# W5 partial readout tile: NOT an ARRAY-PORT replacement; decoder/phase/mux external.
VERSION 5.8 ;
BUSBITCHARS "[]" ;
DIVIDERCHAR "/" ;
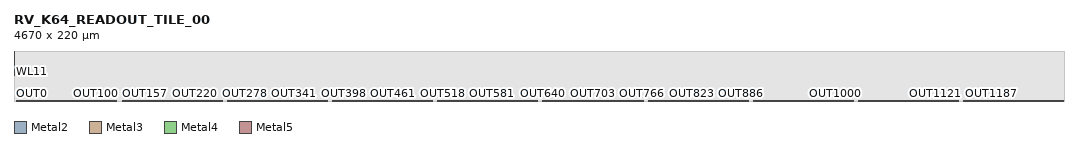
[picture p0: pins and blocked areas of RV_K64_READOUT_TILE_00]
MACRO RV_K64_READOUT_TILE_00
  CLASS BLOCK ;
  ORIGIN 0 0 ;
  SIZE 4670 BY 220 ;
  SYMMETRY X Y ;
  PIN OUT0
    DIRECTION OUTPUT ;
    USE SIGNAL ;
    PORT
      LAYER Metal2 ;
      RECT 12.720 0.000 13.080 0.500 ;
    END
  END OUT0
  PIN OUT1
    DIRECTION OUTPUT ;
    USE SIGNAL ;
    PORT
      LAYER Metal2 ;
      RECT 16.220 0.000 16.580 0.500 ;
    END
  END OUT1
  PIN OUT2
    DIRECTION OUTPUT ;
    USE SIGNAL ;
    PORT
      LAYER Metal2 ;
      RECT 19.720 0.000 20.080 0.500 ;
    END
  END OUT2
  PIN OUT3
    DIRECTION OUTPUT ;
    USE SIGNAL ;
    PORT
      LAYER Metal2 ;
      RECT 23.220 0.000 23.580 0.500 ;
    END
  END OUT3
  PIN OUT4
    DIRECTION OUTPUT ;
    USE SIGNAL ;
    PORT
      LAYER Metal2 ;
      RECT 26.720 0.000 27.080 0.500 ;
    END
  END OUT4
  PIN OUT5
    DIRECTION OUTPUT ;
    USE SIGNAL ;
    PORT
      LAYER Metal2 ;
      RECT 30.220 0.000 30.580 0.500 ;
    END
  END OUT5
  PIN OUT6
    DIRECTION OUTPUT ;
    USE SIGNAL ;
    PORT
      LAYER Metal2 ;
      RECT 33.720 0.000 34.080 0.500 ;
    END
  END OUT6
  PIN OUT7
    DIRECTION OUTPUT ;
    USE SIGNAL ;
    PORT
      LAYER Metal2 ;
      RECT 37.220 0.000 37.580 0.500 ;
    END
  END OUT7
  PIN OUT8
    DIRECTION OUTPUT ;
    USE SIGNAL ;
    PORT
      LAYER Metal2 ;
      RECT 40.720 0.000 41.080 0.500 ;
    END
  END OUT8
  PIN OUT9
    DIRECTION OUTPUT ;
    USE SIGNAL ;
    PORT
      LAYER Metal2 ;
      RECT 44.220 0.000 44.580 0.500 ;
    END
  END OUT9
  PIN OUT10
    DIRECTION OUTPUT ;
    USE SIGNAL ;
    PORT
      LAYER Metal2 ;
      RECT 47.720 0.000 48.080 0.500 ;
    END
  END OUT10
  PIN OUT11
    DIRECTION OUTPUT ;
    USE SIGNAL ;
    PORT
      LAYER Metal2 ;
      RECT 51.220 0.000 51.580 0.500 ;
    END
  END OUT11
  PIN OUT12
    DIRECTION OUTPUT ;
    USE SIGNAL ;
    PORT
      LAYER Metal2 ;
      RECT 54.720 0.000 55.080 0.500 ;
    END
  END OUT12
  PIN OUT13
    DIRECTION OUTPUT ;
    USE SIGNAL ;
    PORT
      LAYER Metal2 ;
      RECT 58.220 0.000 58.580 0.500 ;
    END
  END OUT13
  PIN OUT14
    DIRECTION OUTPUT ;
    USE SIGNAL ;
    PORT
      LAYER Metal2 ;
      RECT 61.720 0.000 62.080 0.500 ;
    END
  END OUT14
  PIN OUT15
    DIRECTION OUTPUT ;
    USE SIGNAL ;
    PORT
      LAYER Metal2 ;
      RECT 65.220 0.000 65.580 0.500 ;
    END
  END OUT15
  PIN OUT16
    DIRECTION OUTPUT ;
    USE SIGNAL ;
    PORT
      LAYER Metal2 ;
      RECT 68.720 0.000 69.080 0.500 ;
    END
  END OUT16
  PIN OUT17
    DIRECTION OUTPUT ;
    USE SIGNAL ;
    PORT
      LAYER Metal2 ;
      RECT 72.220 0.000 72.580 0.500 ;
    END
  END OUT17
  PIN OUT18
    DIRECTION OUTPUT ;
    USE SIGNAL ;
    PORT
      LAYER Metal2 ;
      RECT 75.720 0.000 76.080 0.500 ;
    END
  END OUT18
  PIN OUT19
    DIRECTION OUTPUT ;
    USE SIGNAL ;
    PORT
      LAYER Metal2 ;
      RECT 79.220 0.000 79.580 0.500 ;
    END
  END OUT19
  PIN OUT20
    DIRECTION OUTPUT ;
    USE SIGNAL ;
    PORT
      LAYER Metal2 ;
      RECT 82.720 0.000 83.080 0.500 ;
    END
  END OUT20
  PIN OUT21
    DIRECTION OUTPUT ;
    USE SIGNAL ;
    PORT
      LAYER Metal2 ;
      RECT 86.220 0.000 86.580 0.500 ;
    END
  END OUT21
  PIN OUT22
    DIRECTION OUTPUT ;
    USE SIGNAL ;
    PORT
      LAYER Metal2 ;
      RECT 89.720 0.000 90.080 0.500 ;
    END
  END OUT22
  PIN OUT23
    DIRECTION OUTPUT ;
    USE SIGNAL ;
    PORT
      LAYER Metal2 ;
      RECT 93.220 0.000 93.580 0.500 ;
    END
  END OUT23
  PIN OUT24
    DIRECTION OUTPUT ;
    USE SIGNAL ;
    PORT
      LAYER Metal2 ;
      RECT 96.720 0.000 97.080 0.500 ;
    END
  END OUT24
  PIN OUT25
    DIRECTION OUTPUT ;
    USE SIGNAL ;
    PORT
      LAYER Metal2 ;
      RECT 100.220 0.000 100.580 0.500 ;
    END
  END OUT25
  PIN OUT26
    DIRECTION OUTPUT ;
    USE SIGNAL ;
    PORT
      LAYER Metal2 ;
      RECT 103.720 0.000 104.080 0.500 ;
    END
  END OUT26
  PIN OUT27
    DIRECTION OUTPUT ;
    USE SIGNAL ;
    PORT
      LAYER Metal2 ;
      RECT 107.220 0.000 107.580 0.500 ;
    END
  END OUT27
  PIN OUT28
    DIRECTION OUTPUT ;
    USE SIGNAL ;
    PORT
      LAYER Metal2 ;
      RECT 110.720 0.000 111.080 0.500 ;
    END
  END OUT28
  PIN OUT29
    DIRECTION OUTPUT ;
    USE SIGNAL ;
    PORT
      LAYER Metal2 ;
      RECT 114.220 0.000 114.580 0.500 ;
    END
  END OUT29
  PIN OUT30
    DIRECTION OUTPUT ;
    USE SIGNAL ;
    PORT
      LAYER Metal2 ;
      RECT 117.720 0.000 118.080 0.500 ;
    END
  END OUT30
  PIN OUT31
    DIRECTION OUTPUT ;
    USE SIGNAL ;
    PORT
      LAYER Metal2 ;
      RECT 121.220 0.000 121.580 0.500 ;
    END
  END OUT31
  PIN OUT32
    DIRECTION OUTPUT ;
    USE SIGNAL ;
    PORT
      LAYER Metal2 ;
      RECT 124.720 0.000 125.080 0.500 ;
    END
  END OUT32
  PIN OUT33
    DIRECTION OUTPUT ;
    USE SIGNAL ;
    PORT
      LAYER Metal2 ;
      RECT 128.220 0.000 128.580 0.500 ;
    END
  END OUT33
  PIN OUT34
    DIRECTION OUTPUT ;
    USE SIGNAL ;
    PORT
      LAYER Metal2 ;
      RECT 131.720 0.000 132.080 0.500 ;
    END
  END OUT34
  PIN OUT35
    DIRECTION OUTPUT ;
    USE SIGNAL ;
    PORT
      LAYER Metal2 ;
      RECT 135.220 0.000 135.580 0.500 ;
    END
  END OUT35
  PIN OUT36
    DIRECTION OUTPUT ;
    USE SIGNAL ;
    PORT
      LAYER Metal2 ;
      RECT 138.720 0.000 139.080 0.500 ;
    END
  END OUT36
  PIN OUT37
    DIRECTION OUTPUT ;
    USE SIGNAL ;
    PORT
      LAYER Metal2 ;
      RECT 142.220 0.000 142.580 0.500 ;
    END
  END OUT37
  PIN OUT38
    DIRECTION OUTPUT ;
    USE SIGNAL ;
    PORT
      LAYER Metal2 ;
      RECT 145.720 0.000 146.080 0.500 ;
    END
  END OUT38
  PIN OUT39
    DIRECTION OUTPUT ;
    USE SIGNAL ;
    PORT
      LAYER Metal2 ;
      RECT 149.220 0.000 149.580 0.500 ;
    END
  END OUT39
  PIN OUT40
    DIRECTION OUTPUT ;
    USE SIGNAL ;
    PORT
      LAYER Metal2 ;
      RECT 152.720 0.000 153.080 0.500 ;
    END
  END OUT40
  PIN OUT41
    DIRECTION OUTPUT ;
    USE SIGNAL ;
    PORT
      LAYER Metal2 ;
      RECT 156.220 0.000 156.580 0.500 ;
    END
  END OUT41
  PIN OUT42
    DIRECTION OUTPUT ;
    USE SIGNAL ;
    PORT
      LAYER Metal2 ;
      RECT 159.720 0.000 160.080 0.500 ;
    END
  END OUT42
  PIN OUT43
    DIRECTION OUTPUT ;
    USE SIGNAL ;
    PORT
      LAYER Metal2 ;
      RECT 163.220 0.000 163.580 0.500 ;
    END
  END OUT43
  PIN OUT44
    DIRECTION OUTPUT ;
    USE SIGNAL ;
    PORT
      LAYER Metal2 ;
      RECT 166.720 0.000 167.080 0.500 ;
    END
  END OUT44
  PIN OUT45
    DIRECTION OUTPUT ;
    USE SIGNAL ;
    PORT
      LAYER Metal2 ;
      RECT 170.220 0.000 170.580 0.500 ;
    END
  END OUT45
  PIN OUT46
    DIRECTION OUTPUT ;
    USE SIGNAL ;
    PORT
      LAYER Metal2 ;
      RECT 173.720 0.000 174.080 0.500 ;
    END
  END OUT46
  PIN OUT47
    DIRECTION OUTPUT ;
    USE SIGNAL ;
    PORT
      LAYER Metal2 ;
      RECT 177.220 0.000 177.580 0.500 ;
    END
  END OUT47
  PIN OUT48
    DIRECTION OUTPUT ;
    USE SIGNAL ;
    PORT
      LAYER Metal2 ;
      RECT 180.720 0.000 181.080 0.500 ;
    END
  END OUT48
  PIN OUT49
    DIRECTION OUTPUT ;
    USE SIGNAL ;
    PORT
      LAYER Metal2 ;
      RECT 184.220 0.000 184.580 0.500 ;
    END
  END OUT49
  PIN OUT50
    DIRECTION OUTPUT ;
    USE SIGNAL ;
    PORT
      LAYER Metal2 ;
      RECT 187.720 0.000 188.080 0.500 ;
    END
  END OUT50
  PIN OUT51
    DIRECTION OUTPUT ;
    USE SIGNAL ;
    PORT
      LAYER Metal2 ;
      RECT 191.220 0.000 191.580 0.500 ;
    END
  END OUT51
  PIN OUT52
    DIRECTION OUTPUT ;
    USE SIGNAL ;
    PORT
      LAYER Metal2 ;
      RECT 194.720 0.000 195.080 0.500 ;
    END
  END OUT52
  PIN OUT53
    DIRECTION OUTPUT ;
    USE SIGNAL ;
    PORT
      LAYER Metal2 ;
      RECT 198.220 0.000 198.580 0.500 ;
    END
  END OUT53
  PIN OUT54
    DIRECTION OUTPUT ;
    USE SIGNAL ;
    PORT
      LAYER Metal2 ;
      RECT 201.720 0.000 202.080 0.500 ;
    END
  END OUT54
  PIN OUT55
    DIRECTION OUTPUT ;
    USE SIGNAL ;
    PORT
      LAYER Metal2 ;
      RECT 205.220 0.000 205.580 0.500 ;
    END
  END OUT55
  PIN OUT56
    DIRECTION OUTPUT ;
    USE SIGNAL ;
    PORT
      LAYER Metal2 ;
      RECT 208.720 0.000 209.080 0.500 ;
    END
  END OUT56
  PIN OUT57
    DIRECTION OUTPUT ;
    USE SIGNAL ;
    PORT
      LAYER Metal2 ;
      RECT 212.220 0.000 212.580 0.500 ;
    END
  END OUT57
  PIN OUT58
    DIRECTION OUTPUT ;
    USE SIGNAL ;
    PORT
      LAYER Metal2 ;
      RECT 215.720 0.000 216.080 0.500 ;
    END
  END OUT58
  PIN OUT59
    DIRECTION OUTPUT ;
    USE SIGNAL ;
    PORT
      LAYER Metal2 ;
      RECT 219.220 0.000 219.580 0.500 ;
    END
  END OUT59
  PIN OUT60
    DIRECTION OUTPUT ;
    USE SIGNAL ;
    PORT
      LAYER Metal2 ;
      RECT 222.720 0.000 223.080 0.500 ;
    END
  END OUT60
  PIN OUT61
    DIRECTION OUTPUT ;
    USE SIGNAL ;
    PORT
      LAYER Metal2 ;
      RECT 226.220 0.000 226.580 0.500 ;
    END
  END OUT61
  PIN OUT62
    DIRECTION OUTPUT ;
    USE SIGNAL ;
    PORT
      LAYER Metal2 ;
      RECT 229.720 0.000 230.080 0.500 ;
    END
  END OUT62
  PIN OUT63
    DIRECTION OUTPUT ;
    USE SIGNAL ;
    PORT
      LAYER Metal2 ;
      RECT 233.220 0.000 233.580 0.500 ;
    END
  END OUT63
  PIN OUT64
    DIRECTION OUTPUT ;
    USE SIGNAL ;
    PORT
      LAYER Metal2 ;
      RECT 236.720 0.000 237.080 0.500 ;
    END
  END OUT64
  PIN OUT65
    DIRECTION OUTPUT ;
    USE SIGNAL ;
    PORT
      LAYER Metal2 ;
      RECT 240.220 0.000 240.580 0.500 ;
    END
  END OUT65
  PIN OUT66
    DIRECTION OUTPUT ;
    USE SIGNAL ;
    PORT
      LAYER Metal2 ;
      RECT 243.720 0.000 244.080 0.500 ;
    END
  END OUT66
  PIN OUT67
    DIRECTION OUTPUT ;
    USE SIGNAL ;
    PORT
      LAYER Metal2 ;
      RECT 247.220 0.000 247.580 0.500 ;
    END
  END OUT67
  PIN OUT68
    DIRECTION OUTPUT ;
    USE SIGNAL ;
    PORT
      LAYER Metal2 ;
      RECT 250.720 0.000 251.080 0.500 ;
    END
  END OUT68
  PIN OUT69
    DIRECTION OUTPUT ;
    USE SIGNAL ;
    PORT
      LAYER Metal2 ;
      RECT 254.220 0.000 254.580 0.500 ;
    END
  END OUT69
  PIN OUT70
    DIRECTION OUTPUT ;
    USE SIGNAL ;
    PORT
      LAYER Metal2 ;
      RECT 257.720 0.000 258.080 0.500 ;
    END
  END OUT70
  PIN OUT71
    DIRECTION OUTPUT ;
    USE SIGNAL ;
    PORT
      LAYER Metal2 ;
      RECT 261.220 0.000 261.580 0.500 ;
    END
  END OUT71
  PIN OUT72
    DIRECTION OUTPUT ;
    USE SIGNAL ;
    PORT
      LAYER Metal2 ;
      RECT 264.720 0.000 265.080 0.500 ;
    END
  END OUT72
  PIN OUT73
    DIRECTION OUTPUT ;
    USE SIGNAL ;
    PORT
      LAYER Metal2 ;
      RECT 268.220 0.000 268.580 0.500 ;
    END
  END OUT73
  PIN OUT74
    DIRECTION OUTPUT ;
    USE SIGNAL ;
    PORT
      LAYER Metal2 ;
      RECT 271.720 0.000 272.080 0.500 ;
    END
  END OUT74
  PIN OUT75
    DIRECTION OUTPUT ;
    USE SIGNAL ;
    PORT
      LAYER Metal2 ;
      RECT 275.220 0.000 275.580 0.500 ;
    END
  END OUT75
  PIN OUT76
    DIRECTION OUTPUT ;
    USE SIGNAL ;
    PORT
      LAYER Metal2 ;
      RECT 278.720 0.000 279.080 0.500 ;
    END
  END OUT76
  PIN OUT77
    DIRECTION OUTPUT ;
    USE SIGNAL ;
    PORT
      LAYER Metal2 ;
      RECT 282.220 0.000 282.580 0.500 ;
    END
  END OUT77
  PIN OUT78
    DIRECTION OUTPUT ;
    USE SIGNAL ;
    PORT
      LAYER Metal2 ;
      RECT 285.720 0.000 286.080 0.500 ;
    END
  END OUT78
  PIN OUT79
    DIRECTION OUTPUT ;
    USE SIGNAL ;
    PORT
      LAYER Metal2 ;
      RECT 289.220 0.000 289.580 0.500 ;
    END
  END OUT79
  PIN OUT80
    DIRECTION OUTPUT ;
    USE SIGNAL ;
    PORT
      LAYER Metal2 ;
      RECT 292.720 0.000 293.080 0.500 ;
    END
  END OUT80
  PIN OUT81
    DIRECTION OUTPUT ;
    USE SIGNAL ;
    PORT
      LAYER Metal2 ;
      RECT 296.220 0.000 296.580 0.500 ;
    END
  END OUT81
  PIN OUT82
    DIRECTION OUTPUT ;
    USE SIGNAL ;
    PORT
      LAYER Metal2 ;
      RECT 299.720 0.000 300.080 0.500 ;
    END
  END OUT82
  PIN OUT83
    DIRECTION OUTPUT ;
    USE SIGNAL ;
    PORT
      LAYER Metal2 ;
      RECT 303.220 0.000 303.580 0.500 ;
    END
  END OUT83
  PIN OUT84
    DIRECTION OUTPUT ;
    USE SIGNAL ;
    PORT
      LAYER Metal2 ;
      RECT 306.720 0.000 307.080 0.500 ;
    END
  END OUT84
  PIN OUT85
    DIRECTION OUTPUT ;
    USE SIGNAL ;
    PORT
      LAYER Metal2 ;
      RECT 310.220 0.000 310.580 0.500 ;
    END
  END OUT85
  PIN OUT86
    DIRECTION OUTPUT ;
    USE SIGNAL ;
    PORT
      LAYER Metal2 ;
      RECT 313.720 0.000 314.080 0.500 ;
    END
  END OUT86
  PIN OUT87
    DIRECTION OUTPUT ;
    USE SIGNAL ;
    PORT
      LAYER Metal2 ;
      RECT 317.220 0.000 317.580 0.500 ;
    END
  END OUT87
  PIN OUT88
    DIRECTION OUTPUT ;
    USE SIGNAL ;
    PORT
      LAYER Metal2 ;
      RECT 320.720 0.000 321.080 0.500 ;
    END
  END OUT88
  PIN OUT89
    DIRECTION OUTPUT ;
    USE SIGNAL ;
    PORT
      LAYER Metal2 ;
      RECT 324.220 0.000 324.580 0.500 ;
    END
  END OUT89
  PIN OUT90
    DIRECTION OUTPUT ;
    USE SIGNAL ;
    PORT
      LAYER Metal2 ;
      RECT 327.720 0.000 328.080 0.500 ;
    END
  END OUT90
  PIN OUT91
    DIRECTION OUTPUT ;
    USE SIGNAL ;
    PORT
      LAYER Metal2 ;
      RECT 331.220 0.000 331.580 0.500 ;
    END
  END OUT91
  PIN OUT92
    DIRECTION OUTPUT ;
    USE SIGNAL ;
    PORT
      LAYER Metal2 ;
      RECT 334.720 0.000 335.080 0.500 ;
    END
  END OUT92
  PIN OUT93
    DIRECTION OUTPUT ;
    USE SIGNAL ;
    PORT
      LAYER Metal2 ;
      RECT 338.220 0.000 338.580 0.500 ;
    END
  END OUT93
  PIN OUT94
    DIRECTION OUTPUT ;
    USE SIGNAL ;
    PORT
      LAYER Metal2 ;
      RECT 341.720 0.000 342.080 0.500 ;
    END
  END OUT94
  PIN OUT95
    DIRECTION OUTPUT ;
    USE SIGNAL ;
    PORT
      LAYER Metal2 ;
      RECT 345.220 0.000 345.580 0.500 ;
    END
  END OUT95
  PIN OUT96
    DIRECTION OUTPUT ;
    USE SIGNAL ;
    PORT
      LAYER Metal2 ;
      RECT 348.720 0.000 349.080 0.500 ;
    END
  END OUT96
  PIN OUT97
    DIRECTION OUTPUT ;
    USE SIGNAL ;
    PORT
      LAYER Metal2 ;
      RECT 352.220 0.000 352.580 0.500 ;
    END
  END OUT97
  PIN OUT98
    DIRECTION OUTPUT ;
    USE SIGNAL ;
    PORT
      LAYER Metal2 ;
      RECT 355.720 0.000 356.080 0.500 ;
    END
  END OUT98
  PIN OUT99
    DIRECTION OUTPUT ;
    USE SIGNAL ;
    PORT
      LAYER Metal2 ;
      RECT 359.220 0.000 359.580 0.500 ;
    END
  END OUT99
  PIN OUT100
    DIRECTION OUTPUT ;
    USE SIGNAL ;
    PORT
      LAYER Metal2 ;
      RECT 362.720 0.000 363.080 0.500 ;
    END
  END OUT100
  PIN OUT101
    DIRECTION OUTPUT ;
    USE SIGNAL ;
    PORT
      LAYER Metal2 ;
      RECT 366.220 0.000 366.580 0.500 ;
    END
  END OUT101
  PIN OUT102
    DIRECTION OUTPUT ;
    USE SIGNAL ;
    PORT
      LAYER Metal2 ;
      RECT 369.720 0.000 370.080 0.500 ;
    END
  END OUT102
  PIN OUT103
    DIRECTION OUTPUT ;
    USE SIGNAL ;
    PORT
      LAYER Metal2 ;
      RECT 373.220 0.000 373.580 0.500 ;
    END
  END OUT103
  PIN OUT104
    DIRECTION OUTPUT ;
    USE SIGNAL ;
    PORT
      LAYER Metal2 ;
      RECT 376.720 0.000 377.080 0.500 ;
    END
  END OUT104
  PIN OUT105
    DIRECTION OUTPUT ;
    USE SIGNAL ;
    PORT
      LAYER Metal2 ;
      RECT 380.220 0.000 380.580 0.500 ;
    END
  END OUT105
  PIN OUT106
    DIRECTION OUTPUT ;
    USE SIGNAL ;
    PORT
      LAYER Metal2 ;
      RECT 383.720 0.000 384.080 0.500 ;
    END
  END OUT106
  PIN OUT107
    DIRECTION OUTPUT ;
    USE SIGNAL ;
    PORT
      LAYER Metal2 ;
      RECT 387.220 0.000 387.580 0.500 ;
    END
  END OUT107
  PIN OUT108
    DIRECTION OUTPUT ;
    USE SIGNAL ;
    PORT
      LAYER Metal2 ;
      RECT 390.720 0.000 391.080 0.500 ;
    END
  END OUT108
  PIN OUT109
    DIRECTION OUTPUT ;
    USE SIGNAL ;
    PORT
      LAYER Metal2 ;
      RECT 394.220 0.000 394.580 0.500 ;
    END
  END OUT109
  PIN OUT110
    DIRECTION OUTPUT ;
    USE SIGNAL ;
    PORT
      LAYER Metal2 ;
      RECT 397.720 0.000 398.080 0.500 ;
    END
  END OUT110
  PIN OUT111
    DIRECTION OUTPUT ;
    USE SIGNAL ;
    PORT
      LAYER Metal2 ;
      RECT 401.220 0.000 401.580 0.500 ;
    END
  END OUT111
  PIN OUT112
    DIRECTION OUTPUT ;
    USE SIGNAL ;
    PORT
      LAYER Metal2 ;
      RECT 404.720 0.000 405.080 0.500 ;
    END
  END OUT112
  PIN OUT113
    DIRECTION OUTPUT ;
    USE SIGNAL ;
    PORT
      LAYER Metal2 ;
      RECT 408.220 0.000 408.580 0.500 ;
    END
  END OUT113
  PIN OUT114
    DIRECTION OUTPUT ;
    USE SIGNAL ;
    PORT
      LAYER Metal2 ;
      RECT 411.720 0.000 412.080 0.500 ;
    END
  END OUT114
  PIN OUT115
    DIRECTION OUTPUT ;
    USE SIGNAL ;
    PORT
      LAYER Metal2 ;
      RECT 415.220 0.000 415.580 0.500 ;
    END
  END OUT115
  PIN OUT116
    DIRECTION OUTPUT ;
    USE SIGNAL ;
    PORT
      LAYER Metal2 ;
      RECT 418.720 0.000 419.080 0.500 ;
    END
  END OUT116
  PIN OUT117
    DIRECTION OUTPUT ;
    USE SIGNAL ;
    PORT
      LAYER Metal2 ;
      RECT 422.220 0.000 422.580 0.500 ;
    END
  END OUT117
  PIN OUT118
    DIRECTION OUTPUT ;
    USE SIGNAL ;
    PORT
      LAYER Metal2 ;
      RECT 425.720 0.000 426.080 0.500 ;
    END
  END OUT118
  PIN OUT119
    DIRECTION OUTPUT ;
    USE SIGNAL ;
    PORT
      LAYER Metal2 ;
      RECT 429.220 0.000 429.580 0.500 ;
    END
  END OUT119
  PIN OUT120
    DIRECTION OUTPUT ;
    USE SIGNAL ;
    PORT
      LAYER Metal2 ;
      RECT 432.720 0.000 433.080 0.500 ;
    END
  END OUT120
  PIN OUT121
    DIRECTION OUTPUT ;
    USE SIGNAL ;
    PORT
      LAYER Metal2 ;
      RECT 436.220 0.000 436.580 0.500 ;
    END
  END OUT121
  PIN OUT122
    DIRECTION OUTPUT ;
    USE SIGNAL ;
    PORT
      LAYER Metal2 ;
      RECT 439.720 0.000 440.080 0.500 ;
    END
  END OUT122
  PIN OUT123
    DIRECTION OUTPUT ;
    USE SIGNAL ;
    PORT
      LAYER Metal2 ;
      RECT 443.220 0.000 443.580 0.500 ;
    END
  END OUT123
  PIN OUT124
    DIRECTION OUTPUT ;
    USE SIGNAL ;
    PORT
      LAYER Metal2 ;
      RECT 446.720 0.000 447.080 0.500 ;
    END
  END OUT124
  PIN OUT125
    DIRECTION OUTPUT ;
    USE SIGNAL ;
    PORT
      LAYER Metal2 ;
      RECT 450.220 0.000 450.580 0.500 ;
    END
  END OUT125
  PIN OUT126
    DIRECTION OUTPUT ;
    USE SIGNAL ;
    PORT
      LAYER Metal2 ;
      RECT 453.720 0.000 454.080 0.500 ;
    END
  END OUT126
  PIN OUT127
    DIRECTION OUTPUT ;
    USE SIGNAL ;
    PORT
      LAYER Metal2 ;
      RECT 457.220 0.000 457.580 0.500 ;
    END
  END OUT127
  PIN OUT128
    DIRECTION OUTPUT ;
    USE SIGNAL ;
    PORT
      LAYER Metal2 ;
      RECT 480.720 0.000 481.080 0.500 ;
    END
  END OUT128
  PIN OUT129
    DIRECTION OUTPUT ;
    USE SIGNAL ;
    PORT
      LAYER Metal2 ;
      RECT 484.220 0.000 484.580 0.500 ;
    END
  END OUT129
  PIN OUT130
    DIRECTION OUTPUT ;
    USE SIGNAL ;
    PORT
      LAYER Metal2 ;
      RECT 487.720 0.000 488.080 0.500 ;
    END
  END OUT130
  PIN OUT131
    DIRECTION OUTPUT ;
    USE SIGNAL ;
    PORT
      LAYER Metal2 ;
      RECT 491.220 0.000 491.580 0.500 ;
    END
  END OUT131
  PIN OUT132
    DIRECTION OUTPUT ;
    USE SIGNAL ;
    PORT
      LAYER Metal2 ;
      RECT 494.720 0.000 495.080 0.500 ;
    END
  END OUT132
  PIN OUT133
    DIRECTION OUTPUT ;
    USE SIGNAL ;
    PORT
      LAYER Metal2 ;
      RECT 498.220 0.000 498.580 0.500 ;
    END
  END OUT133
  PIN OUT134
    DIRECTION OUTPUT ;
    USE SIGNAL ;
    PORT
      LAYER Metal2 ;
      RECT 501.720 0.000 502.080 0.500 ;
    END
  END OUT134
  PIN OUT135
    DIRECTION OUTPUT ;
    USE SIGNAL ;
    PORT
      LAYER Metal2 ;
      RECT 505.220 0.000 505.580 0.500 ;
    END
  END OUT135
  PIN OUT136
    DIRECTION OUTPUT ;
    USE SIGNAL ;
    PORT
      LAYER Metal2 ;
      RECT 508.720 0.000 509.080 0.500 ;
    END
  END OUT136
  PIN OUT137
    DIRECTION OUTPUT ;
    USE SIGNAL ;
    PORT
      LAYER Metal2 ;
      RECT 512.220 0.000 512.580 0.500 ;
    END
  END OUT137
  PIN OUT138
    DIRECTION OUTPUT ;
    USE SIGNAL ;
    PORT
      LAYER Metal2 ;
      RECT 515.720 0.000 516.080 0.500 ;
    END
  END OUT138
  PIN OUT139
    DIRECTION OUTPUT ;
    USE SIGNAL ;
    PORT
      LAYER Metal2 ;
      RECT 519.220 0.000 519.580 0.500 ;
    END
  END OUT139
  PIN OUT140
    DIRECTION OUTPUT ;
    USE SIGNAL ;
    PORT
      LAYER Metal2 ;
      RECT 522.720 0.000 523.080 0.500 ;
    END
  END OUT140
  PIN OUT141
    DIRECTION OUTPUT ;
    USE SIGNAL ;
    PORT
      LAYER Metal2 ;
      RECT 526.220 0.000 526.580 0.500 ;
    END
  END OUT141
  PIN OUT142
    DIRECTION OUTPUT ;
    USE SIGNAL ;
    PORT
      LAYER Metal2 ;
      RECT 529.720 0.000 530.080 0.500 ;
    END
  END OUT142
  PIN OUT143
    DIRECTION OUTPUT ;
    USE SIGNAL ;
    PORT
      LAYER Metal2 ;
      RECT 533.220 0.000 533.580 0.500 ;
    END
  END OUT143
  PIN OUT144
    DIRECTION OUTPUT ;
    USE SIGNAL ;
    PORT
      LAYER Metal2 ;
      RECT 536.720 0.000 537.080 0.500 ;
    END
  END OUT144
  PIN OUT145
    DIRECTION OUTPUT ;
    USE SIGNAL ;
    PORT
      LAYER Metal2 ;
      RECT 540.220 0.000 540.580 0.500 ;
    END
  END OUT145
  PIN OUT146
    DIRECTION OUTPUT ;
    USE SIGNAL ;
    PORT
      LAYER Metal2 ;
      RECT 543.720 0.000 544.080 0.500 ;
    END
  END OUT146
  PIN OUT147
    DIRECTION OUTPUT ;
    USE SIGNAL ;
    PORT
      LAYER Metal2 ;
      RECT 547.220 0.000 547.580 0.500 ;
    END
  END OUT147
  PIN OUT148
    DIRECTION OUTPUT ;
    USE SIGNAL ;
    PORT
      LAYER Metal2 ;
      RECT 550.720 0.000 551.080 0.500 ;
    END
  END OUT148
  PIN OUT149
    DIRECTION OUTPUT ;
    USE SIGNAL ;
    PORT
      LAYER Metal2 ;
      RECT 554.220 0.000 554.580 0.500 ;
    END
  END OUT149
  PIN OUT150
    DIRECTION OUTPUT ;
    USE SIGNAL ;
    PORT
      LAYER Metal2 ;
      RECT 557.720 0.000 558.080 0.500 ;
    END
  END OUT150
  PIN OUT151
    DIRECTION OUTPUT ;
    USE SIGNAL ;
    PORT
      LAYER Metal2 ;
      RECT 561.220 0.000 561.580 0.500 ;
    END
  END OUT151
  PIN OUT152
    DIRECTION OUTPUT ;
    USE SIGNAL ;
    PORT
      LAYER Metal2 ;
      RECT 564.720 0.000 565.080 0.500 ;
    END
  END OUT152
  PIN OUT153
    DIRECTION OUTPUT ;
    USE SIGNAL ;
    PORT
      LAYER Metal2 ;
      RECT 568.220 0.000 568.580 0.500 ;
    END
  END OUT153
  PIN OUT154
    DIRECTION OUTPUT ;
    USE SIGNAL ;
    PORT
      LAYER Metal2 ;
      RECT 571.720 0.000 572.080 0.500 ;
    END
  END OUT154
  PIN OUT155
    DIRECTION OUTPUT ;
    USE SIGNAL ;
    PORT
      LAYER Metal2 ;
      RECT 575.220 0.000 575.580 0.500 ;
    END
  END OUT155
  PIN OUT156
    DIRECTION OUTPUT ;
    USE SIGNAL ;
    PORT
      LAYER Metal2 ;
      RECT 578.720 0.000 579.080 0.500 ;
    END
  END OUT156
  PIN OUT157
    DIRECTION OUTPUT ;
    USE SIGNAL ;
    PORT
      LAYER Metal2 ;
      RECT 582.220 0.000 582.580 0.500 ;
    END
  END OUT157
  PIN OUT158
    DIRECTION OUTPUT ;
    USE SIGNAL ;
    PORT
      LAYER Metal2 ;
      RECT 585.720 0.000 586.080 0.500 ;
    END
  END OUT158
  PIN OUT159
    DIRECTION OUTPUT ;
    USE SIGNAL ;
    PORT
      LAYER Metal2 ;
      RECT 589.220 0.000 589.580 0.500 ;
    END
  END OUT159
  PIN OUT160
    DIRECTION OUTPUT ;
    USE SIGNAL ;
    PORT
      LAYER Metal2 ;
      RECT 592.720 0.000 593.080 0.500 ;
    END
  END OUT160
  PIN OUT161
    DIRECTION OUTPUT ;
    USE SIGNAL ;
    PORT
      LAYER Metal2 ;
      RECT 596.220 0.000 596.580 0.500 ;
    END
  END OUT161
  PIN OUT162
    DIRECTION OUTPUT ;
    USE SIGNAL ;
    PORT
      LAYER Metal2 ;
      RECT 599.720 0.000 600.080 0.500 ;
    END
  END OUT162
  PIN OUT163
    DIRECTION OUTPUT ;
    USE SIGNAL ;
    PORT
      LAYER Metal2 ;
      RECT 603.220 0.000 603.580 0.500 ;
    END
  END OUT163
  PIN OUT164
    DIRECTION OUTPUT ;
    USE SIGNAL ;
    PORT
      LAYER Metal2 ;
      RECT 606.720 0.000 607.080 0.500 ;
    END
  END OUT164
  PIN OUT165
    DIRECTION OUTPUT ;
    USE SIGNAL ;
    PORT
      LAYER Metal2 ;
      RECT 610.220 0.000 610.580 0.500 ;
    END
  END OUT165
  PIN OUT166
    DIRECTION OUTPUT ;
    USE SIGNAL ;
    PORT
      LAYER Metal2 ;
      RECT 613.720 0.000 614.080 0.500 ;
    END
  END OUT166
  PIN OUT167
    DIRECTION OUTPUT ;
    USE SIGNAL ;
    PORT
      LAYER Metal2 ;
      RECT 617.220 0.000 617.580 0.500 ;
    END
  END OUT167
  PIN OUT168
    DIRECTION OUTPUT ;
    USE SIGNAL ;
    PORT
      LAYER Metal2 ;
      RECT 620.720 0.000 621.080 0.500 ;
    END
  END OUT168
  PIN OUT169
    DIRECTION OUTPUT ;
    USE SIGNAL ;
    PORT
      LAYER Metal2 ;
      RECT 624.220 0.000 624.580 0.500 ;
    END
  END OUT169
  PIN OUT170
    DIRECTION OUTPUT ;
    USE SIGNAL ;
    PORT
      LAYER Metal2 ;
      RECT 627.720 0.000 628.080 0.500 ;
    END
  END OUT170
  PIN OUT171
    DIRECTION OUTPUT ;
    USE SIGNAL ;
    PORT
      LAYER Metal2 ;
      RECT 631.220 0.000 631.580 0.500 ;
    END
  END OUT171
  PIN OUT172
    DIRECTION OUTPUT ;
    USE SIGNAL ;
    PORT
      LAYER Metal2 ;
      RECT 634.720 0.000 635.080 0.500 ;
    END
  END OUT172
  PIN OUT173
    DIRECTION OUTPUT ;
    USE SIGNAL ;
    PORT
      LAYER Metal2 ;
      RECT 638.220 0.000 638.580 0.500 ;
    END
  END OUT173
  PIN OUT174
    DIRECTION OUTPUT ;
    USE SIGNAL ;
    PORT
      LAYER Metal2 ;
      RECT 641.720 0.000 642.080 0.500 ;
    END
  END OUT174
  PIN OUT175
    DIRECTION OUTPUT ;
    USE SIGNAL ;
    PORT
      LAYER Metal2 ;
      RECT 645.220 0.000 645.580 0.500 ;
    END
  END OUT175
  PIN OUT176
    DIRECTION OUTPUT ;
    USE SIGNAL ;
    PORT
      LAYER Metal2 ;
      RECT 648.720 0.000 649.080 0.500 ;
    END
  END OUT176
  PIN OUT177
    DIRECTION OUTPUT ;
    USE SIGNAL ;
    PORT
      LAYER Metal2 ;
      RECT 652.220 0.000 652.580 0.500 ;
    END
  END OUT177
  PIN OUT178
    DIRECTION OUTPUT ;
    USE SIGNAL ;
    PORT
      LAYER Metal2 ;
      RECT 655.720 0.000 656.080 0.500 ;
    END
  END OUT178
  PIN OUT179
    DIRECTION OUTPUT ;
    USE SIGNAL ;
    PORT
      LAYER Metal2 ;
      RECT 659.220 0.000 659.580 0.500 ;
    END
  END OUT179
  PIN OUT180
    DIRECTION OUTPUT ;
    USE SIGNAL ;
    PORT
      LAYER Metal2 ;
      RECT 662.720 0.000 663.080 0.500 ;
    END
  END OUT180
  PIN OUT181
    DIRECTION OUTPUT ;
    USE SIGNAL ;
    PORT
      LAYER Metal2 ;
      RECT 666.220 0.000 666.580 0.500 ;
    END
  END OUT181
  PIN OUT182
    DIRECTION OUTPUT ;
    USE SIGNAL ;
    PORT
      LAYER Metal2 ;
      RECT 669.720 0.000 670.080 0.500 ;
    END
  END OUT182
  PIN OUT183
    DIRECTION OUTPUT ;
    USE SIGNAL ;
    PORT
      LAYER Metal2 ;
      RECT 673.220 0.000 673.580 0.500 ;
    END
  END OUT183
  PIN OUT184
    DIRECTION OUTPUT ;
    USE SIGNAL ;
    PORT
      LAYER Metal2 ;
      RECT 676.720 0.000 677.080 0.500 ;
    END
  END OUT184
  PIN OUT185
    DIRECTION OUTPUT ;
    USE SIGNAL ;
    PORT
      LAYER Metal2 ;
      RECT 680.220 0.000 680.580 0.500 ;
    END
  END OUT185
  PIN OUT186
    DIRECTION OUTPUT ;
    USE SIGNAL ;
    PORT
      LAYER Metal2 ;
      RECT 683.720 0.000 684.080 0.500 ;
    END
  END OUT186
  PIN OUT187
    DIRECTION OUTPUT ;
    USE SIGNAL ;
    PORT
      LAYER Metal2 ;
      RECT 687.220 0.000 687.580 0.500 ;
    END
  END OUT187
  PIN OUT188
    DIRECTION OUTPUT ;
    USE SIGNAL ;
    PORT
      LAYER Metal2 ;
      RECT 690.720 0.000 691.080 0.500 ;
    END
  END OUT188
  PIN OUT189
    DIRECTION OUTPUT ;
    USE SIGNAL ;
    PORT
      LAYER Metal2 ;
      RECT 694.220 0.000 694.580 0.500 ;
    END
  END OUT189
  PIN OUT190
    DIRECTION OUTPUT ;
    USE SIGNAL ;
    PORT
      LAYER Metal2 ;
      RECT 697.720 0.000 698.080 0.500 ;
    END
  END OUT190
  PIN OUT191
    DIRECTION OUTPUT ;
    USE SIGNAL ;
    PORT
      LAYER Metal2 ;
      RECT 701.220 0.000 701.580 0.500 ;
    END
  END OUT191
  PIN OUT192
    DIRECTION OUTPUT ;
    USE SIGNAL ;
    PORT
      LAYER Metal2 ;
      RECT 704.720 0.000 705.080 0.500 ;
    END
  END OUT192
  PIN OUT193
    DIRECTION OUTPUT ;
    USE SIGNAL ;
    PORT
      LAYER Metal2 ;
      RECT 708.220 0.000 708.580 0.500 ;
    END
  END OUT193
  PIN OUT194
    DIRECTION OUTPUT ;
    USE SIGNAL ;
    PORT
      LAYER Metal2 ;
      RECT 711.720 0.000 712.080 0.500 ;
    END
  END OUT194
  PIN OUT195
    DIRECTION OUTPUT ;
    USE SIGNAL ;
    PORT
      LAYER Metal2 ;
      RECT 715.220 0.000 715.580 0.500 ;
    END
  END OUT195
  PIN OUT196
    DIRECTION OUTPUT ;
    USE SIGNAL ;
    PORT
      LAYER Metal2 ;
      RECT 718.720 0.000 719.080 0.500 ;
    END
  END OUT196
  PIN OUT197
    DIRECTION OUTPUT ;
    USE SIGNAL ;
    PORT
      LAYER Metal2 ;
      RECT 722.220 0.000 722.580 0.500 ;
    END
  END OUT197
  PIN OUT198
    DIRECTION OUTPUT ;
    USE SIGNAL ;
    PORT
      LAYER Metal2 ;
      RECT 725.720 0.000 726.080 0.500 ;
    END
  END OUT198
  PIN OUT199
    DIRECTION OUTPUT ;
    USE SIGNAL ;
    PORT
      LAYER Metal2 ;
      RECT 729.220 0.000 729.580 0.500 ;
    END
  END OUT199
  PIN OUT200
    DIRECTION OUTPUT ;
    USE SIGNAL ;
    PORT
      LAYER Metal2 ;
      RECT 732.720 0.000 733.080 0.500 ;
    END
  END OUT200
  PIN OUT201
    DIRECTION OUTPUT ;
    USE SIGNAL ;
    PORT
      LAYER Metal2 ;
      RECT 736.220 0.000 736.580 0.500 ;
    END
  END OUT201
  PIN OUT202
    DIRECTION OUTPUT ;
    USE SIGNAL ;
    PORT
      LAYER Metal2 ;
      RECT 739.720 0.000 740.080 0.500 ;
    END
  END OUT202
  PIN OUT203
    DIRECTION OUTPUT ;
    USE SIGNAL ;
    PORT
      LAYER Metal2 ;
      RECT 743.220 0.000 743.580 0.500 ;
    END
  END OUT203
  PIN OUT204
    DIRECTION OUTPUT ;
    USE SIGNAL ;
    PORT
      LAYER Metal2 ;
      RECT 746.720 0.000 747.080 0.500 ;
    END
  END OUT204
  PIN OUT205
    DIRECTION OUTPUT ;
    USE SIGNAL ;
    PORT
      LAYER Metal2 ;
      RECT 750.220 0.000 750.580 0.500 ;
    END
  END OUT205
  PIN OUT206
    DIRECTION OUTPUT ;
    USE SIGNAL ;
    PORT
      LAYER Metal2 ;
      RECT 753.720 0.000 754.080 0.500 ;
    END
  END OUT206
  PIN OUT207
    DIRECTION OUTPUT ;
    USE SIGNAL ;
    PORT
      LAYER Metal2 ;
      RECT 757.220 0.000 757.580 0.500 ;
    END
  END OUT207
  PIN OUT208
    DIRECTION OUTPUT ;
    USE SIGNAL ;
    PORT
      LAYER Metal2 ;
      RECT 760.720 0.000 761.080 0.500 ;
    END
  END OUT208
  PIN OUT209
    DIRECTION OUTPUT ;
    USE SIGNAL ;
    PORT
      LAYER Metal2 ;
      RECT 764.220 0.000 764.580 0.500 ;
    END
  END OUT209
  PIN OUT210
    DIRECTION OUTPUT ;
    USE SIGNAL ;
    PORT
      LAYER Metal2 ;
      RECT 767.720 0.000 768.080 0.500 ;
    END
  END OUT210
  PIN OUT211
    DIRECTION OUTPUT ;
    USE SIGNAL ;
    PORT
      LAYER Metal2 ;
      RECT 771.220 0.000 771.580 0.500 ;
    END
  END OUT211
  PIN OUT212
    DIRECTION OUTPUT ;
    USE SIGNAL ;
    PORT
      LAYER Metal2 ;
      RECT 774.720 0.000 775.080 0.500 ;
    END
  END OUT212
  PIN OUT213
    DIRECTION OUTPUT ;
    USE SIGNAL ;
    PORT
      LAYER Metal2 ;
      RECT 778.220 0.000 778.580 0.500 ;
    END
  END OUT213
  PIN OUT214
    DIRECTION OUTPUT ;
    USE SIGNAL ;
    PORT
      LAYER Metal2 ;
      RECT 781.720 0.000 782.080 0.500 ;
    END
  END OUT214
  PIN OUT215
    DIRECTION OUTPUT ;
    USE SIGNAL ;
    PORT
      LAYER Metal2 ;
      RECT 785.220 0.000 785.580 0.500 ;
    END
  END OUT215
  PIN OUT216
    DIRECTION OUTPUT ;
    USE SIGNAL ;
    PORT
      LAYER Metal2 ;
      RECT 788.720 0.000 789.080 0.500 ;
    END
  END OUT216
  PIN OUT217
    DIRECTION OUTPUT ;
    USE SIGNAL ;
    PORT
      LAYER Metal2 ;
      RECT 792.220 0.000 792.580 0.500 ;
    END
  END OUT217
  PIN OUT218
    DIRECTION OUTPUT ;
    USE SIGNAL ;
    PORT
      LAYER Metal2 ;
      RECT 795.720 0.000 796.080 0.500 ;
    END
  END OUT218
  PIN OUT219
    DIRECTION OUTPUT ;
    USE SIGNAL ;
    PORT
      LAYER Metal2 ;
      RECT 799.220 0.000 799.580 0.500 ;
    END
  END OUT219
  PIN OUT220
    DIRECTION OUTPUT ;
    USE SIGNAL ;
    PORT
      LAYER Metal2 ;
      RECT 802.720 0.000 803.080 0.500 ;
    END
  END OUT220
  PIN OUT221
    DIRECTION OUTPUT ;
    USE SIGNAL ;
    PORT
      LAYER Metal2 ;
      RECT 806.220 0.000 806.580 0.500 ;
    END
  END OUT221
  PIN OUT222
    DIRECTION OUTPUT ;
    USE SIGNAL ;
    PORT
      LAYER Metal2 ;
      RECT 809.720 0.000 810.080 0.500 ;
    END
  END OUT222
  PIN OUT223
    DIRECTION OUTPUT ;
    USE SIGNAL ;
    PORT
      LAYER Metal2 ;
      RECT 813.220 0.000 813.580 0.500 ;
    END
  END OUT223
  PIN OUT224
    DIRECTION OUTPUT ;
    USE SIGNAL ;
    PORT
      LAYER Metal2 ;
      RECT 816.720 0.000 817.080 0.500 ;
    END
  END OUT224
  PIN OUT225
    DIRECTION OUTPUT ;
    USE SIGNAL ;
    PORT
      LAYER Metal2 ;
      RECT 820.220 0.000 820.580 0.500 ;
    END
  END OUT225
  PIN OUT226
    DIRECTION OUTPUT ;
    USE SIGNAL ;
    PORT
      LAYER Metal2 ;
      RECT 823.720 0.000 824.080 0.500 ;
    END
  END OUT226
  PIN OUT227
    DIRECTION OUTPUT ;
    USE SIGNAL ;
    PORT
      LAYER Metal2 ;
      RECT 827.220 0.000 827.580 0.500 ;
    END
  END OUT227
  PIN OUT228
    DIRECTION OUTPUT ;
    USE SIGNAL ;
    PORT
      LAYER Metal2 ;
      RECT 830.720 0.000 831.080 0.500 ;
    END
  END OUT228
  PIN OUT229
    DIRECTION OUTPUT ;
    USE SIGNAL ;
    PORT
      LAYER Metal2 ;
      RECT 834.220 0.000 834.580 0.500 ;
    END
  END OUT229
  PIN OUT230
    DIRECTION OUTPUT ;
    USE SIGNAL ;
    PORT
      LAYER Metal2 ;
      RECT 837.720 0.000 838.080 0.500 ;
    END
  END OUT230
  PIN OUT231
    DIRECTION OUTPUT ;
    USE SIGNAL ;
    PORT
      LAYER Metal2 ;
      RECT 841.220 0.000 841.580 0.500 ;
    END
  END OUT231
  PIN OUT232
    DIRECTION OUTPUT ;
    USE SIGNAL ;
    PORT
      LAYER Metal2 ;
      RECT 844.720 0.000 845.080 0.500 ;
    END
  END OUT232
  PIN OUT233
    DIRECTION OUTPUT ;
    USE SIGNAL ;
    PORT
      LAYER Metal2 ;
      RECT 848.220 0.000 848.580 0.500 ;
    END
  END OUT233
  PIN OUT234
    DIRECTION OUTPUT ;
    USE SIGNAL ;
    PORT
      LAYER Metal2 ;
      RECT 851.720 0.000 852.080 0.500 ;
    END
  END OUT234
  PIN OUT235
    DIRECTION OUTPUT ;
    USE SIGNAL ;
    PORT
      LAYER Metal2 ;
      RECT 855.220 0.000 855.580 0.500 ;
    END
  END OUT235
  PIN OUT236
    DIRECTION OUTPUT ;
    USE SIGNAL ;
    PORT
      LAYER Metal2 ;
      RECT 858.720 0.000 859.080 0.500 ;
    END
  END OUT236
  PIN OUT237
    DIRECTION OUTPUT ;
    USE SIGNAL ;
    PORT
      LAYER Metal2 ;
      RECT 862.220 0.000 862.580 0.500 ;
    END
  END OUT237
  PIN OUT238
    DIRECTION OUTPUT ;
    USE SIGNAL ;
    PORT
      LAYER Metal2 ;
      RECT 865.720 0.000 866.080 0.500 ;
    END
  END OUT238
  PIN OUT239
    DIRECTION OUTPUT ;
    USE SIGNAL ;
    PORT
      LAYER Metal2 ;
      RECT 869.220 0.000 869.580 0.500 ;
    END
  END OUT239
  PIN OUT240
    DIRECTION OUTPUT ;
    USE SIGNAL ;
    PORT
      LAYER Metal2 ;
      RECT 872.720 0.000 873.080 0.500 ;
    END
  END OUT240
  PIN OUT241
    DIRECTION OUTPUT ;
    USE SIGNAL ;
    PORT
      LAYER Metal2 ;
      RECT 876.220 0.000 876.580 0.500 ;
    END
  END OUT241
  PIN OUT242
    DIRECTION OUTPUT ;
    USE SIGNAL ;
    PORT
      LAYER Metal2 ;
      RECT 879.720 0.000 880.080 0.500 ;
    END
  END OUT242
  PIN OUT243
    DIRECTION OUTPUT ;
    USE SIGNAL ;
    PORT
      LAYER Metal2 ;
      RECT 883.220 0.000 883.580 0.500 ;
    END
  END OUT243
  PIN OUT244
    DIRECTION OUTPUT ;
    USE SIGNAL ;
    PORT
      LAYER Metal2 ;
      RECT 886.720 0.000 887.080 0.500 ;
    END
  END OUT244
  PIN OUT245
    DIRECTION OUTPUT ;
    USE SIGNAL ;
    PORT
      LAYER Metal2 ;
      RECT 890.220 0.000 890.580 0.500 ;
    END
  END OUT245
  PIN OUT246
    DIRECTION OUTPUT ;
    USE SIGNAL ;
    PORT
      LAYER Metal2 ;
      RECT 893.720 0.000 894.080 0.500 ;
    END
  END OUT246
  PIN OUT247
    DIRECTION OUTPUT ;
    USE SIGNAL ;
    PORT
      LAYER Metal2 ;
      RECT 897.220 0.000 897.580 0.500 ;
    END
  END OUT247
  PIN OUT248
    DIRECTION OUTPUT ;
    USE SIGNAL ;
    PORT
      LAYER Metal2 ;
      RECT 900.720 0.000 901.080 0.500 ;
    END
  END OUT248
  PIN OUT249
    DIRECTION OUTPUT ;
    USE SIGNAL ;
    PORT
      LAYER Metal2 ;
      RECT 904.220 0.000 904.580 0.500 ;
    END
  END OUT249
  PIN OUT250
    DIRECTION OUTPUT ;
    USE SIGNAL ;
    PORT
      LAYER Metal2 ;
      RECT 907.720 0.000 908.080 0.500 ;
    END
  END OUT250
  PIN OUT251
    DIRECTION OUTPUT ;
    USE SIGNAL ;
    PORT
      LAYER Metal2 ;
      RECT 911.220 0.000 911.580 0.500 ;
    END
  END OUT251
  PIN OUT252
    DIRECTION OUTPUT ;
    USE SIGNAL ;
    PORT
      LAYER Metal2 ;
      RECT 914.720 0.000 915.080 0.500 ;
    END
  END OUT252
  PIN OUT253
    DIRECTION OUTPUT ;
    USE SIGNAL ;
    PORT
      LAYER Metal2 ;
      RECT 918.220 0.000 918.580 0.500 ;
    END
  END OUT253
  PIN OUT254
    DIRECTION OUTPUT ;
    USE SIGNAL ;
    PORT
      LAYER Metal2 ;
      RECT 921.720 0.000 922.080 0.500 ;
    END
  END OUT254
  PIN OUT255
    DIRECTION OUTPUT ;
    USE SIGNAL ;
    PORT
      LAYER Metal2 ;
      RECT 925.220 0.000 925.580 0.500 ;
    END
  END OUT255
  PIN OUT256
    DIRECTION OUTPUT ;
    USE SIGNAL ;
    PORT
      LAYER Metal2 ;
      RECT 948.720 0.000 949.080 0.500 ;
    END
  END OUT256
  PIN OUT257
    DIRECTION OUTPUT ;
    USE SIGNAL ;
    PORT
      LAYER Metal2 ;
      RECT 952.220 0.000 952.580 0.500 ;
    END
  END OUT257
  PIN OUT258
    DIRECTION OUTPUT ;
    USE SIGNAL ;
    PORT
      LAYER Metal2 ;
      RECT 955.720 0.000 956.080 0.500 ;
    END
  END OUT258
  PIN OUT259
    DIRECTION OUTPUT ;
    USE SIGNAL ;
    PORT
      LAYER Metal2 ;
      RECT 959.220 0.000 959.580 0.500 ;
    END
  END OUT259
  PIN OUT260
    DIRECTION OUTPUT ;
    USE SIGNAL ;
    PORT
      LAYER Metal2 ;
      RECT 962.720 0.000 963.080 0.500 ;
    END
  END OUT260
  PIN OUT261
    DIRECTION OUTPUT ;
    USE SIGNAL ;
    PORT
      LAYER Metal2 ;
      RECT 966.220 0.000 966.580 0.500 ;
    END
  END OUT261
  PIN OUT262
    DIRECTION OUTPUT ;
    USE SIGNAL ;
    PORT
      LAYER Metal2 ;
      RECT 969.720 0.000 970.080 0.500 ;
    END
  END OUT262
  PIN OUT263
    DIRECTION OUTPUT ;
    USE SIGNAL ;
    PORT
      LAYER Metal2 ;
      RECT 973.220 0.000 973.580 0.500 ;
    END
  END OUT263
  PIN OUT264
    DIRECTION OUTPUT ;
    USE SIGNAL ;
    PORT
      LAYER Metal2 ;
      RECT 976.720 0.000 977.080 0.500 ;
    END
  END OUT264
  PIN OUT265
    DIRECTION OUTPUT ;
    USE SIGNAL ;
    PORT
      LAYER Metal2 ;
      RECT 980.220 0.000 980.580 0.500 ;
    END
  END OUT265
  PIN OUT266
    DIRECTION OUTPUT ;
    USE SIGNAL ;
    PORT
      LAYER Metal2 ;
      RECT 983.720 0.000 984.080 0.500 ;
    END
  END OUT266
  PIN OUT267
    DIRECTION OUTPUT ;
    USE SIGNAL ;
    PORT
      LAYER Metal2 ;
      RECT 987.220 0.000 987.580 0.500 ;
    END
  END OUT267
  PIN OUT268
    DIRECTION OUTPUT ;
    USE SIGNAL ;
    PORT
      LAYER Metal2 ;
      RECT 990.720 0.000 991.080 0.500 ;
    END
  END OUT268
  PIN OUT269
    DIRECTION OUTPUT ;
    USE SIGNAL ;
    PORT
      LAYER Metal2 ;
      RECT 994.220 0.000 994.580 0.500 ;
    END
  END OUT269
  PIN OUT270
    DIRECTION OUTPUT ;
    USE SIGNAL ;
    PORT
      LAYER Metal2 ;
      RECT 997.720 0.000 998.080 0.500 ;
    END
  END OUT270
  PIN OUT271
    DIRECTION OUTPUT ;
    USE SIGNAL ;
    PORT
      LAYER Metal2 ;
      RECT 1001.220 0.000 1001.580 0.500 ;
    END
  END OUT271
  PIN OUT272
    DIRECTION OUTPUT ;
    USE SIGNAL ;
    PORT
      LAYER Metal2 ;
      RECT 1004.720 0.000 1005.080 0.500 ;
    END
  END OUT272
  PIN OUT273
    DIRECTION OUTPUT ;
    USE SIGNAL ;
    PORT
      LAYER Metal2 ;
      RECT 1008.220 0.000 1008.580 0.500 ;
    END
  END OUT273
  PIN OUT274
    DIRECTION OUTPUT ;
    USE SIGNAL ;
    PORT
      LAYER Metal2 ;
      RECT 1011.720 0.000 1012.080 0.500 ;
    END
  END OUT274
  PIN OUT275
    DIRECTION OUTPUT ;
    USE SIGNAL ;
    PORT
      LAYER Metal2 ;
      RECT 1015.220 0.000 1015.580 0.500 ;
    END
  END OUT275
  PIN OUT276
    DIRECTION OUTPUT ;
    USE SIGNAL ;
    PORT
      LAYER Metal2 ;
      RECT 1018.720 0.000 1019.080 0.500 ;
    END
  END OUT276
  PIN OUT277
    DIRECTION OUTPUT ;
    USE SIGNAL ;
    PORT
      LAYER Metal2 ;
      RECT 1022.220 0.000 1022.580 0.500 ;
    END
  END OUT277
  PIN OUT278
    DIRECTION OUTPUT ;
    USE SIGNAL ;
    PORT
      LAYER Metal2 ;
      RECT 1025.720 0.000 1026.080 0.500 ;
    END
  END OUT278
  PIN OUT279
    DIRECTION OUTPUT ;
    USE SIGNAL ;
    PORT
      LAYER Metal2 ;
      RECT 1029.220 0.000 1029.580 0.500 ;
    END
  END OUT279
  PIN OUT280
    DIRECTION OUTPUT ;
    USE SIGNAL ;
    PORT
      LAYER Metal2 ;
      RECT 1032.720 0.000 1033.080 0.500 ;
    END
  END OUT280
  PIN OUT281
    DIRECTION OUTPUT ;
    USE SIGNAL ;
    PORT
      LAYER Metal2 ;
      RECT 1036.220 0.000 1036.580 0.500 ;
    END
  END OUT281
  PIN OUT282
    DIRECTION OUTPUT ;
    USE SIGNAL ;
    PORT
      LAYER Metal2 ;
      RECT 1039.720 0.000 1040.080 0.500 ;
    END
  END OUT282
  PIN OUT283
    DIRECTION OUTPUT ;
    USE SIGNAL ;
    PORT
      LAYER Metal2 ;
      RECT 1043.220 0.000 1043.580 0.500 ;
    END
  END OUT283
  PIN OUT284
    DIRECTION OUTPUT ;
    USE SIGNAL ;
    PORT
      LAYER Metal2 ;
      RECT 1046.720 0.000 1047.080 0.500 ;
    END
  END OUT284
  PIN OUT285
    DIRECTION OUTPUT ;
    USE SIGNAL ;
    PORT
      LAYER Metal2 ;
      RECT 1050.220 0.000 1050.580 0.500 ;
    END
  END OUT285
  PIN OUT286
    DIRECTION OUTPUT ;
    USE SIGNAL ;
    PORT
      LAYER Metal2 ;
      RECT 1053.720 0.000 1054.080 0.500 ;
    END
  END OUT286
  PIN OUT287
    DIRECTION OUTPUT ;
    USE SIGNAL ;
    PORT
      LAYER Metal2 ;
      RECT 1057.220 0.000 1057.580 0.500 ;
    END
  END OUT287
  PIN OUT288
    DIRECTION OUTPUT ;
    USE SIGNAL ;
    PORT
      LAYER Metal2 ;
      RECT 1060.720 0.000 1061.080 0.500 ;
    END
  END OUT288
  PIN OUT289
    DIRECTION OUTPUT ;
    USE SIGNAL ;
    PORT
      LAYER Metal2 ;
      RECT 1064.220 0.000 1064.580 0.500 ;
    END
  END OUT289
  PIN OUT290
    DIRECTION OUTPUT ;
    USE SIGNAL ;
    PORT
      LAYER Metal2 ;
      RECT 1067.720 0.000 1068.080 0.500 ;
    END
  END OUT290
  PIN OUT291
    DIRECTION OUTPUT ;
    USE SIGNAL ;
    PORT
      LAYER Metal2 ;
      RECT 1071.220 0.000 1071.580 0.500 ;
    END
  END OUT291
  PIN OUT292
    DIRECTION OUTPUT ;
    USE SIGNAL ;
    PORT
      LAYER Metal2 ;
      RECT 1074.720 0.000 1075.080 0.500 ;
    END
  END OUT292
  PIN OUT293
    DIRECTION OUTPUT ;
    USE SIGNAL ;
    PORT
      LAYER Metal2 ;
      RECT 1078.220 0.000 1078.580 0.500 ;
    END
  END OUT293
  PIN OUT294
    DIRECTION OUTPUT ;
    USE SIGNAL ;
    PORT
      LAYER Metal2 ;
      RECT 1081.720 0.000 1082.080 0.500 ;
    END
  END OUT294
  PIN OUT295
    DIRECTION OUTPUT ;
    USE SIGNAL ;
    PORT
      LAYER Metal2 ;
      RECT 1085.220 0.000 1085.580 0.500 ;
    END
  END OUT295
  PIN OUT296
    DIRECTION OUTPUT ;
    USE SIGNAL ;
    PORT
      LAYER Metal2 ;
      RECT 1088.720 0.000 1089.080 0.500 ;
    END
  END OUT296
  PIN OUT297
    DIRECTION OUTPUT ;
    USE SIGNAL ;
    PORT
      LAYER Metal2 ;
      RECT 1092.220 0.000 1092.580 0.500 ;
    END
  END OUT297
  PIN OUT298
    DIRECTION OUTPUT ;
    USE SIGNAL ;
    PORT
      LAYER Metal2 ;
      RECT 1095.720 0.000 1096.080 0.500 ;
    END
  END OUT298
  PIN OUT299
    DIRECTION OUTPUT ;
    USE SIGNAL ;
    PORT
      LAYER Metal2 ;
      RECT 1099.220 0.000 1099.580 0.500 ;
    END
  END OUT299
  PIN OUT300
    DIRECTION OUTPUT ;
    USE SIGNAL ;
    PORT
      LAYER Metal2 ;
      RECT 1102.720 0.000 1103.080 0.500 ;
    END
  END OUT300
  PIN OUT301
    DIRECTION OUTPUT ;
    USE SIGNAL ;
    PORT
      LAYER Metal2 ;
      RECT 1106.220 0.000 1106.580 0.500 ;
    END
  END OUT301
  PIN OUT302
    DIRECTION OUTPUT ;
    USE SIGNAL ;
    PORT
      LAYER Metal2 ;
      RECT 1109.720 0.000 1110.080 0.500 ;
    END
  END OUT302
  PIN OUT303
    DIRECTION OUTPUT ;
    USE SIGNAL ;
    PORT
      LAYER Metal2 ;
      RECT 1113.220 0.000 1113.580 0.500 ;
    END
  END OUT303
  PIN OUT304
    DIRECTION OUTPUT ;
    USE SIGNAL ;
    PORT
      LAYER Metal2 ;
      RECT 1116.720 0.000 1117.080 0.500 ;
    END
  END OUT304
  PIN OUT305
    DIRECTION OUTPUT ;
    USE SIGNAL ;
    PORT
      LAYER Metal2 ;
      RECT 1120.220 0.000 1120.580 0.500 ;
    END
  END OUT305
  PIN OUT306
    DIRECTION OUTPUT ;
    USE SIGNAL ;
    PORT
      LAYER Metal2 ;
      RECT 1123.720 0.000 1124.080 0.500 ;
    END
  END OUT306
  PIN OUT307
    DIRECTION OUTPUT ;
    USE SIGNAL ;
    PORT
      LAYER Metal2 ;
      RECT 1127.220 0.000 1127.580 0.500 ;
    END
  END OUT307
  PIN OUT308
    DIRECTION OUTPUT ;
    USE SIGNAL ;
    PORT
      LAYER Metal2 ;
      RECT 1130.720 0.000 1131.080 0.500 ;
    END
  END OUT308
  PIN OUT309
    DIRECTION OUTPUT ;
    USE SIGNAL ;
    PORT
      LAYER Metal2 ;
      RECT 1134.220 0.000 1134.580 0.500 ;
    END
  END OUT309
  PIN OUT310
    DIRECTION OUTPUT ;
    USE SIGNAL ;
    PORT
      LAYER Metal2 ;
      RECT 1137.720 0.000 1138.080 0.500 ;
    END
  END OUT310
  PIN OUT311
    DIRECTION OUTPUT ;
    USE SIGNAL ;
    PORT
      LAYER Metal2 ;
      RECT 1141.220 0.000 1141.580 0.500 ;
    END
  END OUT311
  PIN OUT312
    DIRECTION OUTPUT ;
    USE SIGNAL ;
    PORT
      LAYER Metal2 ;
      RECT 1144.720 0.000 1145.080 0.500 ;
    END
  END OUT312
  PIN OUT313
    DIRECTION OUTPUT ;
    USE SIGNAL ;
    PORT
      LAYER Metal2 ;
      RECT 1148.220 0.000 1148.580 0.500 ;
    END
  END OUT313
  PIN OUT314
    DIRECTION OUTPUT ;
    USE SIGNAL ;
    PORT
      LAYER Metal2 ;
      RECT 1151.720 0.000 1152.080 0.500 ;
    END
  END OUT314
  PIN OUT315
    DIRECTION OUTPUT ;
    USE SIGNAL ;
    PORT
      LAYER Metal2 ;
      RECT 1155.220 0.000 1155.580 0.500 ;
    END
  END OUT315
  PIN OUT316
    DIRECTION OUTPUT ;
    USE SIGNAL ;
    PORT
      LAYER Metal2 ;
      RECT 1158.720 0.000 1159.080 0.500 ;
    END
  END OUT316
  PIN OUT317
    DIRECTION OUTPUT ;
    USE SIGNAL ;
    PORT
      LAYER Metal2 ;
      RECT 1162.220 0.000 1162.580 0.500 ;
    END
  END OUT317
  PIN OUT318
    DIRECTION OUTPUT ;
    USE SIGNAL ;
    PORT
      LAYER Metal2 ;
      RECT 1165.720 0.000 1166.080 0.500 ;
    END
  END OUT318
  PIN OUT319
    DIRECTION OUTPUT ;
    USE SIGNAL ;
    PORT
      LAYER Metal2 ;
      RECT 1169.220 0.000 1169.580 0.500 ;
    END
  END OUT319
  PIN OUT320
    DIRECTION OUTPUT ;
    USE SIGNAL ;
    PORT
      LAYER Metal2 ;
      RECT 1172.720 0.000 1173.080 0.500 ;
    END
  END OUT320
  PIN OUT321
    DIRECTION OUTPUT ;
    USE SIGNAL ;
    PORT
      LAYER Metal2 ;
      RECT 1176.220 0.000 1176.580 0.500 ;
    END
  END OUT321
  PIN OUT322
    DIRECTION OUTPUT ;
    USE SIGNAL ;
    PORT
      LAYER Metal2 ;
      RECT 1179.720 0.000 1180.080 0.500 ;
    END
  END OUT322
  PIN OUT323
    DIRECTION OUTPUT ;
    USE SIGNAL ;
    PORT
      LAYER Metal2 ;
      RECT 1183.220 0.000 1183.580 0.500 ;
    END
  END OUT323
  PIN OUT324
    DIRECTION OUTPUT ;
    USE SIGNAL ;
    PORT
      LAYER Metal2 ;
      RECT 1186.720 0.000 1187.080 0.500 ;
    END
  END OUT324
  PIN OUT325
    DIRECTION OUTPUT ;
    USE SIGNAL ;
    PORT
      LAYER Metal2 ;
      RECT 1190.220 0.000 1190.580 0.500 ;
    END
  END OUT325
  PIN OUT326
    DIRECTION OUTPUT ;
    USE SIGNAL ;
    PORT
      LAYER Metal2 ;
      RECT 1193.720 0.000 1194.080 0.500 ;
    END
  END OUT326
  PIN OUT327
    DIRECTION OUTPUT ;
    USE SIGNAL ;
    PORT
      LAYER Metal2 ;
      RECT 1197.220 0.000 1197.580 0.500 ;
    END
  END OUT327
  PIN OUT328
    DIRECTION OUTPUT ;
    USE SIGNAL ;
    PORT
      LAYER Metal2 ;
      RECT 1200.720 0.000 1201.080 0.500 ;
    END
  END OUT328
  PIN OUT329
    DIRECTION OUTPUT ;
    USE SIGNAL ;
    PORT
      LAYER Metal2 ;
      RECT 1204.220 0.000 1204.580 0.500 ;
    END
  END OUT329
  PIN OUT330
    DIRECTION OUTPUT ;
    USE SIGNAL ;
    PORT
      LAYER Metal2 ;
      RECT 1207.720 0.000 1208.080 0.500 ;
    END
  END OUT330
  PIN OUT331
    DIRECTION OUTPUT ;
    USE SIGNAL ;
    PORT
      LAYER Metal2 ;
      RECT 1211.220 0.000 1211.580 0.500 ;
    END
  END OUT331
  PIN OUT332
    DIRECTION OUTPUT ;
    USE SIGNAL ;
    PORT
      LAYER Metal2 ;
      RECT 1214.720 0.000 1215.080 0.500 ;
    END
  END OUT332
  PIN OUT333
    DIRECTION OUTPUT ;
    USE SIGNAL ;
    PORT
      LAYER Metal2 ;
      RECT 1218.220 0.000 1218.580 0.500 ;
    END
  END OUT333
  PIN OUT334
    DIRECTION OUTPUT ;
    USE SIGNAL ;
    PORT
      LAYER Metal2 ;
      RECT 1221.720 0.000 1222.080 0.500 ;
    END
  END OUT334
  PIN OUT335
    DIRECTION OUTPUT ;
    USE SIGNAL ;
    PORT
      LAYER Metal2 ;
      RECT 1225.220 0.000 1225.580 0.500 ;
    END
  END OUT335
  PIN OUT336
    DIRECTION OUTPUT ;
    USE SIGNAL ;
    PORT
      LAYER Metal2 ;
      RECT 1228.720 0.000 1229.080 0.500 ;
    END
  END OUT336
  PIN OUT337
    DIRECTION OUTPUT ;
    USE SIGNAL ;
    PORT
      LAYER Metal2 ;
      RECT 1232.220 0.000 1232.580 0.500 ;
    END
  END OUT337
  PIN OUT338
    DIRECTION OUTPUT ;
    USE SIGNAL ;
    PORT
      LAYER Metal2 ;
      RECT 1235.720 0.000 1236.080 0.500 ;
    END
  END OUT338
  PIN OUT339
    DIRECTION OUTPUT ;
    USE SIGNAL ;
    PORT
      LAYER Metal2 ;
      RECT 1239.220 0.000 1239.580 0.500 ;
    END
  END OUT339
  PIN OUT340
    DIRECTION OUTPUT ;
    USE SIGNAL ;
    PORT
      LAYER Metal2 ;
      RECT 1242.720 0.000 1243.080 0.500 ;
    END
  END OUT340
  PIN OUT341
    DIRECTION OUTPUT ;
    USE SIGNAL ;
    PORT
      LAYER Metal2 ;
      RECT 1246.220 0.000 1246.580 0.500 ;
    END
  END OUT341
  PIN OUT342
    DIRECTION OUTPUT ;
    USE SIGNAL ;
    PORT
      LAYER Metal2 ;
      RECT 1249.720 0.000 1250.080 0.500 ;
    END
  END OUT342
  PIN OUT343
    DIRECTION OUTPUT ;
    USE SIGNAL ;
    PORT
      LAYER Metal2 ;
      RECT 1253.220 0.000 1253.580 0.500 ;
    END
  END OUT343
  PIN OUT344
    DIRECTION OUTPUT ;
    USE SIGNAL ;
    PORT
      LAYER Metal2 ;
      RECT 1256.720 0.000 1257.080 0.500 ;
    END
  END OUT344
  PIN OUT345
    DIRECTION OUTPUT ;
    USE SIGNAL ;
    PORT
      LAYER Metal2 ;
      RECT 1260.220 0.000 1260.580 0.500 ;
    END
  END OUT345
  PIN OUT346
    DIRECTION OUTPUT ;
    USE SIGNAL ;
    PORT
      LAYER Metal2 ;
      RECT 1263.720 0.000 1264.080 0.500 ;
    END
  END OUT346
  PIN OUT347
    DIRECTION OUTPUT ;
    USE SIGNAL ;
    PORT
      LAYER Metal2 ;
      RECT 1267.220 0.000 1267.580 0.500 ;
    END
  END OUT347
  PIN OUT348
    DIRECTION OUTPUT ;
    USE SIGNAL ;
    PORT
      LAYER Metal2 ;
      RECT 1270.720 0.000 1271.080 0.500 ;
    END
  END OUT348
  PIN OUT349
    DIRECTION OUTPUT ;
    USE SIGNAL ;
    PORT
      LAYER Metal2 ;
      RECT 1274.220 0.000 1274.580 0.500 ;
    END
  END OUT349
  PIN OUT350
    DIRECTION OUTPUT ;
    USE SIGNAL ;
    PORT
      LAYER Metal2 ;
      RECT 1277.720 0.000 1278.080 0.500 ;
    END
  END OUT350
  PIN OUT351
    DIRECTION OUTPUT ;
    USE SIGNAL ;
    PORT
      LAYER Metal2 ;
      RECT 1281.220 0.000 1281.580 0.500 ;
    END
  END OUT351
  PIN OUT352
    DIRECTION OUTPUT ;
    USE SIGNAL ;
    PORT
      LAYER Metal2 ;
      RECT 1284.720 0.000 1285.080 0.500 ;
    END
  END OUT352
  PIN OUT353
    DIRECTION OUTPUT ;
    USE SIGNAL ;
    PORT
      LAYER Metal2 ;
      RECT 1288.220 0.000 1288.580 0.500 ;
    END
  END OUT353
  PIN OUT354
    DIRECTION OUTPUT ;
    USE SIGNAL ;
    PORT
      LAYER Metal2 ;
      RECT 1291.720 0.000 1292.080 0.500 ;
    END
  END OUT354
  PIN OUT355
    DIRECTION OUTPUT ;
    USE SIGNAL ;
    PORT
      LAYER Metal2 ;
      RECT 1295.220 0.000 1295.580 0.500 ;
    END
  END OUT355
  PIN OUT356
    DIRECTION OUTPUT ;
    USE SIGNAL ;
    PORT
      LAYER Metal2 ;
      RECT 1298.720 0.000 1299.080 0.500 ;
    END
  END OUT356
  PIN OUT357
    DIRECTION OUTPUT ;
    USE SIGNAL ;
    PORT
      LAYER Metal2 ;
      RECT 1302.220 0.000 1302.580 0.500 ;
    END
  END OUT357
  PIN OUT358
    DIRECTION OUTPUT ;
    USE SIGNAL ;
    PORT
      LAYER Metal2 ;
      RECT 1305.720 0.000 1306.080 0.500 ;
    END
  END OUT358
  PIN OUT359
    DIRECTION OUTPUT ;
    USE SIGNAL ;
    PORT
      LAYER Metal2 ;
      RECT 1309.220 0.000 1309.580 0.500 ;
    END
  END OUT359
  PIN OUT360
    DIRECTION OUTPUT ;
    USE SIGNAL ;
    PORT
      LAYER Metal2 ;
      RECT 1312.720 0.000 1313.080 0.500 ;
    END
  END OUT360
  PIN OUT361
    DIRECTION OUTPUT ;
    USE SIGNAL ;
    PORT
      LAYER Metal2 ;
      RECT 1316.220 0.000 1316.580 0.500 ;
    END
  END OUT361
  PIN OUT362
    DIRECTION OUTPUT ;
    USE SIGNAL ;
    PORT
      LAYER Metal2 ;
      RECT 1319.720 0.000 1320.080 0.500 ;
    END
  END OUT362
  PIN OUT363
    DIRECTION OUTPUT ;
    USE SIGNAL ;
    PORT
      LAYER Metal2 ;
      RECT 1323.220 0.000 1323.580 0.500 ;
    END
  END OUT363
  PIN OUT364
    DIRECTION OUTPUT ;
    USE SIGNAL ;
    PORT
      LAYER Metal2 ;
      RECT 1326.720 0.000 1327.080 0.500 ;
    END
  END OUT364
  PIN OUT365
    DIRECTION OUTPUT ;
    USE SIGNAL ;
    PORT
      LAYER Metal2 ;
      RECT 1330.220 0.000 1330.580 0.500 ;
    END
  END OUT365
  PIN OUT366
    DIRECTION OUTPUT ;
    USE SIGNAL ;
    PORT
      LAYER Metal2 ;
      RECT 1333.720 0.000 1334.080 0.500 ;
    END
  END OUT366
  PIN OUT367
    DIRECTION OUTPUT ;
    USE SIGNAL ;
    PORT
      LAYER Metal2 ;
      RECT 1337.220 0.000 1337.580 0.500 ;
    END
  END OUT367
  PIN OUT368
    DIRECTION OUTPUT ;
    USE SIGNAL ;
    PORT
      LAYER Metal2 ;
      RECT 1340.720 0.000 1341.080 0.500 ;
    END
  END OUT368
  PIN OUT369
    DIRECTION OUTPUT ;
    USE SIGNAL ;
    PORT
      LAYER Metal2 ;
      RECT 1344.220 0.000 1344.580 0.500 ;
    END
  END OUT369
  PIN OUT370
    DIRECTION OUTPUT ;
    USE SIGNAL ;
    PORT
      LAYER Metal2 ;
      RECT 1347.720 0.000 1348.080 0.500 ;
    END
  END OUT370
  PIN OUT371
    DIRECTION OUTPUT ;
    USE SIGNAL ;
    PORT
      LAYER Metal2 ;
      RECT 1351.220 0.000 1351.580 0.500 ;
    END
  END OUT371
  PIN OUT372
    DIRECTION OUTPUT ;
    USE SIGNAL ;
    PORT
      LAYER Metal2 ;
      RECT 1354.720 0.000 1355.080 0.500 ;
    END
  END OUT372
  PIN OUT373
    DIRECTION OUTPUT ;
    USE SIGNAL ;
    PORT
      LAYER Metal2 ;
      RECT 1358.220 0.000 1358.580 0.500 ;
    END
  END OUT373
  PIN OUT374
    DIRECTION OUTPUT ;
    USE SIGNAL ;
    PORT
      LAYER Metal2 ;
      RECT 1361.720 0.000 1362.080 0.500 ;
    END
  END OUT374
  PIN OUT375
    DIRECTION OUTPUT ;
    USE SIGNAL ;
    PORT
      LAYER Metal2 ;
      RECT 1365.220 0.000 1365.580 0.500 ;
    END
  END OUT375
  PIN OUT376
    DIRECTION OUTPUT ;
    USE SIGNAL ;
    PORT
      LAYER Metal2 ;
      RECT 1368.720 0.000 1369.080 0.500 ;
    END
  END OUT376
  PIN OUT377
    DIRECTION OUTPUT ;
    USE SIGNAL ;
    PORT
      LAYER Metal2 ;
      RECT 1372.220 0.000 1372.580 0.500 ;
    END
  END OUT377
  PIN OUT378
    DIRECTION OUTPUT ;
    USE SIGNAL ;
    PORT
      LAYER Metal2 ;
      RECT 1375.720 0.000 1376.080 0.500 ;
    END
  END OUT378
  PIN OUT379
    DIRECTION OUTPUT ;
    USE SIGNAL ;
    PORT
      LAYER Metal2 ;
      RECT 1379.220 0.000 1379.580 0.500 ;
    END
  END OUT379
  PIN OUT380
    DIRECTION OUTPUT ;
    USE SIGNAL ;
    PORT
      LAYER Metal2 ;
      RECT 1382.720 0.000 1383.080 0.500 ;
    END
  END OUT380
  PIN OUT381
    DIRECTION OUTPUT ;
    USE SIGNAL ;
    PORT
      LAYER Metal2 ;
      RECT 1386.220 0.000 1386.580 0.500 ;
    END
  END OUT381
  PIN OUT382
    DIRECTION OUTPUT ;
    USE SIGNAL ;
    PORT
      LAYER Metal2 ;
      RECT 1389.720 0.000 1390.080 0.500 ;
    END
  END OUT382
  PIN OUT383
    DIRECTION OUTPUT ;
    USE SIGNAL ;
    PORT
      LAYER Metal2 ;
      RECT 1393.220 0.000 1393.580 0.500 ;
    END
  END OUT383
  PIN OUT384
    DIRECTION OUTPUT ;
    USE SIGNAL ;
    PORT
      LAYER Metal2 ;
      RECT 1416.720 0.000 1417.080 0.500 ;
    END
  END OUT384
  PIN OUT385
    DIRECTION OUTPUT ;
    USE SIGNAL ;
    PORT
      LAYER Metal2 ;
      RECT 1420.220 0.000 1420.580 0.500 ;
    END
  END OUT385
  PIN OUT386
    DIRECTION OUTPUT ;
    USE SIGNAL ;
    PORT
      LAYER Metal2 ;
      RECT 1423.720 0.000 1424.080 0.500 ;
    END
  END OUT386
  PIN OUT387
    DIRECTION OUTPUT ;
    USE SIGNAL ;
    PORT
      LAYER Metal2 ;
      RECT 1427.220 0.000 1427.580 0.500 ;
    END
  END OUT387
  PIN OUT388
    DIRECTION OUTPUT ;
    USE SIGNAL ;
    PORT
      LAYER Metal2 ;
      RECT 1430.720 0.000 1431.080 0.500 ;
    END
  END OUT388
  PIN OUT389
    DIRECTION OUTPUT ;
    USE SIGNAL ;
    PORT
      LAYER Metal2 ;
      RECT 1434.220 0.000 1434.580 0.500 ;
    END
  END OUT389
  PIN OUT390
    DIRECTION OUTPUT ;
    USE SIGNAL ;
    PORT
      LAYER Metal2 ;
      RECT 1437.720 0.000 1438.080 0.500 ;
    END
  END OUT390
  PIN OUT391
    DIRECTION OUTPUT ;
    USE SIGNAL ;
    PORT
      LAYER Metal2 ;
      RECT 1441.220 0.000 1441.580 0.500 ;
    END
  END OUT391
  PIN OUT392
    DIRECTION OUTPUT ;
    USE SIGNAL ;
    PORT
      LAYER Metal2 ;
      RECT 1444.720 0.000 1445.080 0.500 ;
    END
  END OUT392
  PIN OUT393
    DIRECTION OUTPUT ;
    USE SIGNAL ;
    PORT
      LAYER Metal2 ;
      RECT 1448.220 0.000 1448.580 0.500 ;
    END
  END OUT393
  PIN OUT394
    DIRECTION OUTPUT ;
    USE SIGNAL ;
    PORT
      LAYER Metal2 ;
      RECT 1451.720 0.000 1452.080 0.500 ;
    END
  END OUT394
  PIN OUT395
    DIRECTION OUTPUT ;
    USE SIGNAL ;
    PORT
      LAYER Metal2 ;
      RECT 1455.220 0.000 1455.580 0.500 ;
    END
  END OUT395
  PIN OUT396
    DIRECTION OUTPUT ;
    USE SIGNAL ;
    PORT
      LAYER Metal2 ;
      RECT 1458.720 0.000 1459.080 0.500 ;
    END
  END OUT396
  PIN OUT397
    DIRECTION OUTPUT ;
    USE SIGNAL ;
    PORT
      LAYER Metal2 ;
      RECT 1462.220 0.000 1462.580 0.500 ;
    END
  END OUT397
  PIN OUT398
    DIRECTION OUTPUT ;
    USE SIGNAL ;
    PORT
      LAYER Metal2 ;
      RECT 1465.720 0.000 1466.080 0.500 ;
    END
  END OUT398
  PIN OUT399
    DIRECTION OUTPUT ;
    USE SIGNAL ;
    PORT
      LAYER Metal2 ;
      RECT 1469.220 0.000 1469.580 0.500 ;
    END
  END OUT399
  PIN OUT400
    DIRECTION OUTPUT ;
    USE SIGNAL ;
    PORT
      LAYER Metal2 ;
      RECT 1472.720 0.000 1473.080 0.500 ;
    END
  END OUT400
  PIN OUT401
    DIRECTION OUTPUT ;
    USE SIGNAL ;
    PORT
      LAYER Metal2 ;
      RECT 1476.220 0.000 1476.580 0.500 ;
    END
  END OUT401
  PIN OUT402
    DIRECTION OUTPUT ;
    USE SIGNAL ;
    PORT
      LAYER Metal2 ;
      RECT 1479.720 0.000 1480.080 0.500 ;
    END
  END OUT402
  PIN OUT403
    DIRECTION OUTPUT ;
    USE SIGNAL ;
    PORT
      LAYER Metal2 ;
      RECT 1483.220 0.000 1483.580 0.500 ;
    END
  END OUT403
  PIN OUT404
    DIRECTION OUTPUT ;
    USE SIGNAL ;
    PORT
      LAYER Metal2 ;
      RECT 1486.720 0.000 1487.080 0.500 ;
    END
  END OUT404
  PIN OUT405
    DIRECTION OUTPUT ;
    USE SIGNAL ;
    PORT
      LAYER Metal2 ;
      RECT 1490.220 0.000 1490.580 0.500 ;
    END
  END OUT405
  PIN OUT406
    DIRECTION OUTPUT ;
    USE SIGNAL ;
    PORT
      LAYER Metal2 ;
      RECT 1493.720 0.000 1494.080 0.500 ;
    END
  END OUT406
  PIN OUT407
    DIRECTION OUTPUT ;
    USE SIGNAL ;
    PORT
      LAYER Metal2 ;
      RECT 1497.220 0.000 1497.580 0.500 ;
    END
  END OUT407
  PIN OUT408
    DIRECTION OUTPUT ;
    USE SIGNAL ;
    PORT
      LAYER Metal2 ;
      RECT 1500.720 0.000 1501.080 0.500 ;
    END
  END OUT408
  PIN OUT409
    DIRECTION OUTPUT ;
    USE SIGNAL ;
    PORT
      LAYER Metal2 ;
      RECT 1504.220 0.000 1504.580 0.500 ;
    END
  END OUT409
  PIN OUT410
    DIRECTION OUTPUT ;
    USE SIGNAL ;
    PORT
      LAYER Metal2 ;
      RECT 1507.720 0.000 1508.080 0.500 ;
    END
  END OUT410
  PIN OUT411
    DIRECTION OUTPUT ;
    USE SIGNAL ;
    PORT
      LAYER Metal2 ;
      RECT 1511.220 0.000 1511.580 0.500 ;
    END
  END OUT411
  PIN OUT412
    DIRECTION OUTPUT ;
    USE SIGNAL ;
    PORT
      LAYER Metal2 ;
      RECT 1514.720 0.000 1515.080 0.500 ;
    END
  END OUT412
  PIN OUT413
    DIRECTION OUTPUT ;
    USE SIGNAL ;
    PORT
      LAYER Metal2 ;
      RECT 1518.220 0.000 1518.580 0.500 ;
    END
  END OUT413
  PIN OUT414
    DIRECTION OUTPUT ;
    USE SIGNAL ;
    PORT
      LAYER Metal2 ;
      RECT 1521.720 0.000 1522.080 0.500 ;
    END
  END OUT414
  PIN OUT415
    DIRECTION OUTPUT ;
    USE SIGNAL ;
    PORT
      LAYER Metal2 ;
      RECT 1525.220 0.000 1525.580 0.500 ;
    END
  END OUT415
  PIN OUT416
    DIRECTION OUTPUT ;
    USE SIGNAL ;
    PORT
      LAYER Metal2 ;
      RECT 1528.720 0.000 1529.080 0.500 ;
    END
  END OUT416
  PIN OUT417
    DIRECTION OUTPUT ;
    USE SIGNAL ;
    PORT
      LAYER Metal2 ;
      RECT 1532.220 0.000 1532.580 0.500 ;
    END
  END OUT417
  PIN OUT418
    DIRECTION OUTPUT ;
    USE SIGNAL ;
    PORT
      LAYER Metal2 ;
      RECT 1535.720 0.000 1536.080 0.500 ;
    END
  END OUT418
  PIN OUT419
    DIRECTION OUTPUT ;
    USE SIGNAL ;
    PORT
      LAYER Metal2 ;
      RECT 1539.220 0.000 1539.580 0.500 ;
    END
  END OUT419
  PIN OUT420
    DIRECTION OUTPUT ;
    USE SIGNAL ;
    PORT
      LAYER Metal2 ;
      RECT 1542.720 0.000 1543.080 0.500 ;
    END
  END OUT420
  PIN OUT421
    DIRECTION OUTPUT ;
    USE SIGNAL ;
    PORT
      LAYER Metal2 ;
      RECT 1546.220 0.000 1546.580 0.500 ;
    END
  END OUT421
  PIN OUT422
    DIRECTION OUTPUT ;
    USE SIGNAL ;
    PORT
      LAYER Metal2 ;
      RECT 1549.720 0.000 1550.080 0.500 ;
    END
  END OUT422
  PIN OUT423
    DIRECTION OUTPUT ;
    USE SIGNAL ;
    PORT
      LAYER Metal2 ;
      RECT 1553.220 0.000 1553.580 0.500 ;
    END
  END OUT423
  PIN OUT424
    DIRECTION OUTPUT ;
    USE SIGNAL ;
    PORT
      LAYER Metal2 ;
      RECT 1556.720 0.000 1557.080 0.500 ;
    END
  END OUT424
  PIN OUT425
    DIRECTION OUTPUT ;
    USE SIGNAL ;
    PORT
      LAYER Metal2 ;
      RECT 1560.220 0.000 1560.580 0.500 ;
    END
  END OUT425
  PIN OUT426
    DIRECTION OUTPUT ;
    USE SIGNAL ;
    PORT
      LAYER Metal2 ;
      RECT 1563.720 0.000 1564.080 0.500 ;
    END
  END OUT426
  PIN OUT427
    DIRECTION OUTPUT ;
    USE SIGNAL ;
    PORT
      LAYER Metal2 ;
      RECT 1567.220 0.000 1567.580 0.500 ;
    END
  END OUT427
  PIN OUT428
    DIRECTION OUTPUT ;
    USE SIGNAL ;
    PORT
      LAYER Metal2 ;
      RECT 1570.720 0.000 1571.080 0.500 ;
    END
  END OUT428
  PIN OUT429
    DIRECTION OUTPUT ;
    USE SIGNAL ;
    PORT
      LAYER Metal2 ;
      RECT 1574.220 0.000 1574.580 0.500 ;
    END
  END OUT429
  PIN OUT430
    DIRECTION OUTPUT ;
    USE SIGNAL ;
    PORT
      LAYER Metal2 ;
      RECT 1577.720 0.000 1578.080 0.500 ;
    END
  END OUT430
  PIN OUT431
    DIRECTION OUTPUT ;
    USE SIGNAL ;
    PORT
      LAYER Metal2 ;
      RECT 1581.220 0.000 1581.580 0.500 ;
    END
  END OUT431
  PIN OUT432
    DIRECTION OUTPUT ;
    USE SIGNAL ;
    PORT
      LAYER Metal2 ;
      RECT 1584.720 0.000 1585.080 0.500 ;
    END
  END OUT432
  PIN OUT433
    DIRECTION OUTPUT ;
    USE SIGNAL ;
    PORT
      LAYER Metal2 ;
      RECT 1588.220 0.000 1588.580 0.500 ;
    END
  END OUT433
  PIN OUT434
    DIRECTION OUTPUT ;
    USE SIGNAL ;
    PORT
      LAYER Metal2 ;
      RECT 1591.720 0.000 1592.080 0.500 ;
    END
  END OUT434
  PIN OUT435
    DIRECTION OUTPUT ;
    USE SIGNAL ;
    PORT
      LAYER Metal2 ;
      RECT 1595.220 0.000 1595.580 0.500 ;
    END
  END OUT435
  PIN OUT436
    DIRECTION OUTPUT ;
    USE SIGNAL ;
    PORT
      LAYER Metal2 ;
      RECT 1598.720 0.000 1599.080 0.500 ;
    END
  END OUT436
  PIN OUT437
    DIRECTION OUTPUT ;
    USE SIGNAL ;
    PORT
      LAYER Metal2 ;
      RECT 1602.220 0.000 1602.580 0.500 ;
    END
  END OUT437
  PIN OUT438
    DIRECTION OUTPUT ;
    USE SIGNAL ;
    PORT
      LAYER Metal2 ;
      RECT 1605.720 0.000 1606.080 0.500 ;
    END
  END OUT438
  PIN OUT439
    DIRECTION OUTPUT ;
    USE SIGNAL ;
    PORT
      LAYER Metal2 ;
      RECT 1609.220 0.000 1609.580 0.500 ;
    END
  END OUT439
  PIN OUT440
    DIRECTION OUTPUT ;
    USE SIGNAL ;
    PORT
      LAYER Metal2 ;
      RECT 1612.720 0.000 1613.080 0.500 ;
    END
  END OUT440
  PIN OUT441
    DIRECTION OUTPUT ;
    USE SIGNAL ;
    PORT
      LAYER Metal2 ;
      RECT 1616.220 0.000 1616.580 0.500 ;
    END
  END OUT441
  PIN OUT442
    DIRECTION OUTPUT ;
    USE SIGNAL ;
    PORT
      LAYER Metal2 ;
      RECT 1619.720 0.000 1620.080 0.500 ;
    END
  END OUT442
  PIN OUT443
    DIRECTION OUTPUT ;
    USE SIGNAL ;
    PORT
      LAYER Metal2 ;
      RECT 1623.220 0.000 1623.580 0.500 ;
    END
  END OUT443
  PIN OUT444
    DIRECTION OUTPUT ;
    USE SIGNAL ;
    PORT
      LAYER Metal2 ;
      RECT 1626.720 0.000 1627.080 0.500 ;
    END
  END OUT444
  PIN OUT445
    DIRECTION OUTPUT ;
    USE SIGNAL ;
    PORT
      LAYER Metal2 ;
      RECT 1630.220 0.000 1630.580 0.500 ;
    END
  END OUT445
  PIN OUT446
    DIRECTION OUTPUT ;
    USE SIGNAL ;
    PORT
      LAYER Metal2 ;
      RECT 1633.720 0.000 1634.080 0.500 ;
    END
  END OUT446
  PIN OUT447
    DIRECTION OUTPUT ;
    USE SIGNAL ;
    PORT
      LAYER Metal2 ;
      RECT 1637.220 0.000 1637.580 0.500 ;
    END
  END OUT447
  PIN OUT448
    DIRECTION OUTPUT ;
    USE SIGNAL ;
    PORT
      LAYER Metal2 ;
      RECT 1640.720 0.000 1641.080 0.500 ;
    END
  END OUT448
  PIN OUT449
    DIRECTION OUTPUT ;
    USE SIGNAL ;
    PORT
      LAYER Metal2 ;
      RECT 1644.220 0.000 1644.580 0.500 ;
    END
  END OUT449
  PIN OUT450
    DIRECTION OUTPUT ;
    USE SIGNAL ;
    PORT
      LAYER Metal2 ;
      RECT 1647.720 0.000 1648.080 0.500 ;
    END
  END OUT450
  PIN OUT451
    DIRECTION OUTPUT ;
    USE SIGNAL ;
    PORT
      LAYER Metal2 ;
      RECT 1651.220 0.000 1651.580 0.500 ;
    END
  END OUT451
  PIN OUT452
    DIRECTION OUTPUT ;
    USE SIGNAL ;
    PORT
      LAYER Metal2 ;
      RECT 1654.720 0.000 1655.080 0.500 ;
    END
  END OUT452
  PIN OUT453
    DIRECTION OUTPUT ;
    USE SIGNAL ;
    PORT
      LAYER Metal2 ;
      RECT 1658.220 0.000 1658.580 0.500 ;
    END
  END OUT453
  PIN OUT454
    DIRECTION OUTPUT ;
    USE SIGNAL ;
    PORT
      LAYER Metal2 ;
      RECT 1661.720 0.000 1662.080 0.500 ;
    END
  END OUT454
  PIN OUT455
    DIRECTION OUTPUT ;
    USE SIGNAL ;
    PORT
      LAYER Metal2 ;
      RECT 1665.220 0.000 1665.580 0.500 ;
    END
  END OUT455
  PIN OUT456
    DIRECTION OUTPUT ;
    USE SIGNAL ;
    PORT
      LAYER Metal2 ;
      RECT 1668.720 0.000 1669.080 0.500 ;
    END
  END OUT456
  PIN OUT457
    DIRECTION OUTPUT ;
    USE SIGNAL ;
    PORT
      LAYER Metal2 ;
      RECT 1672.220 0.000 1672.580 0.500 ;
    END
  END OUT457
  PIN OUT458
    DIRECTION OUTPUT ;
    USE SIGNAL ;
    PORT
      LAYER Metal2 ;
      RECT 1675.720 0.000 1676.080 0.500 ;
    END
  END OUT458
  PIN OUT459
    DIRECTION OUTPUT ;
    USE SIGNAL ;
    PORT
      LAYER Metal2 ;
      RECT 1679.220 0.000 1679.580 0.500 ;
    END
  END OUT459
  PIN OUT460
    DIRECTION OUTPUT ;
    USE SIGNAL ;
    PORT
      LAYER Metal2 ;
      RECT 1682.720 0.000 1683.080 0.500 ;
    END
  END OUT460
  PIN OUT461
    DIRECTION OUTPUT ;
    USE SIGNAL ;
    PORT
      LAYER Metal2 ;
      RECT 1686.220 0.000 1686.580 0.500 ;
    END
  END OUT461
  PIN OUT462
    DIRECTION OUTPUT ;
    USE SIGNAL ;
    PORT
      LAYER Metal2 ;
      RECT 1689.720 0.000 1690.080 0.500 ;
    END
  END OUT462
  PIN OUT463
    DIRECTION OUTPUT ;
    USE SIGNAL ;
    PORT
      LAYER Metal2 ;
      RECT 1693.220 0.000 1693.580 0.500 ;
    END
  END OUT463
  PIN OUT464
    DIRECTION OUTPUT ;
    USE SIGNAL ;
    PORT
      LAYER Metal2 ;
      RECT 1696.720 0.000 1697.080 0.500 ;
    END
  END OUT464
  PIN OUT465
    DIRECTION OUTPUT ;
    USE SIGNAL ;
    PORT
      LAYER Metal2 ;
      RECT 1700.220 0.000 1700.580 0.500 ;
    END
  END OUT465
  PIN OUT466
    DIRECTION OUTPUT ;
    USE SIGNAL ;
    PORT
      LAYER Metal2 ;
      RECT 1703.720 0.000 1704.080 0.500 ;
    END
  END OUT466
  PIN OUT467
    DIRECTION OUTPUT ;
    USE SIGNAL ;
    PORT
      LAYER Metal2 ;
      RECT 1707.220 0.000 1707.580 0.500 ;
    END
  END OUT467
  PIN OUT468
    DIRECTION OUTPUT ;
    USE SIGNAL ;
    PORT
      LAYER Metal2 ;
      RECT 1710.720 0.000 1711.080 0.500 ;
    END
  END OUT468
  PIN OUT469
    DIRECTION OUTPUT ;
    USE SIGNAL ;
    PORT
      LAYER Metal2 ;
      RECT 1714.220 0.000 1714.580 0.500 ;
    END
  END OUT469
  PIN OUT470
    DIRECTION OUTPUT ;
    USE SIGNAL ;
    PORT
      LAYER Metal2 ;
      RECT 1717.720 0.000 1718.080 0.500 ;
    END
  END OUT470
  PIN OUT471
    DIRECTION OUTPUT ;
    USE SIGNAL ;
    PORT
      LAYER Metal2 ;
      RECT 1721.220 0.000 1721.580 0.500 ;
    END
  END OUT471
  PIN OUT472
    DIRECTION OUTPUT ;
    USE SIGNAL ;
    PORT
      LAYER Metal2 ;
      RECT 1724.720 0.000 1725.080 0.500 ;
    END
  END OUT472
  PIN OUT473
    DIRECTION OUTPUT ;
    USE SIGNAL ;
    PORT
      LAYER Metal2 ;
      RECT 1728.220 0.000 1728.580 0.500 ;
    END
  END OUT473
  PIN OUT474
    DIRECTION OUTPUT ;
    USE SIGNAL ;
    PORT
      LAYER Metal2 ;
      RECT 1731.720 0.000 1732.080 0.500 ;
    END
  END OUT474
  PIN OUT475
    DIRECTION OUTPUT ;
    USE SIGNAL ;
    PORT
      LAYER Metal2 ;
      RECT 1735.220 0.000 1735.580 0.500 ;
    END
  END OUT475
  PIN OUT476
    DIRECTION OUTPUT ;
    USE SIGNAL ;
    PORT
      LAYER Metal2 ;
      RECT 1738.720 0.000 1739.080 0.500 ;
    END
  END OUT476
  PIN OUT477
    DIRECTION OUTPUT ;
    USE SIGNAL ;
    PORT
      LAYER Metal2 ;
      RECT 1742.220 0.000 1742.580 0.500 ;
    END
  END OUT477
  PIN OUT478
    DIRECTION OUTPUT ;
    USE SIGNAL ;
    PORT
      LAYER Metal2 ;
      RECT 1745.720 0.000 1746.080 0.500 ;
    END
  END OUT478
  PIN OUT479
    DIRECTION OUTPUT ;
    USE SIGNAL ;
    PORT
      LAYER Metal2 ;
      RECT 1749.220 0.000 1749.580 0.500 ;
    END
  END OUT479
  PIN OUT480
    DIRECTION OUTPUT ;
    USE SIGNAL ;
    PORT
      LAYER Metal2 ;
      RECT 1752.720 0.000 1753.080 0.500 ;
    END
  END OUT480
  PIN OUT481
    DIRECTION OUTPUT ;
    USE SIGNAL ;
    PORT
      LAYER Metal2 ;
      RECT 1756.220 0.000 1756.580 0.500 ;
    END
  END OUT481
  PIN OUT482
    DIRECTION OUTPUT ;
    USE SIGNAL ;
    PORT
      LAYER Metal2 ;
      RECT 1759.720 0.000 1760.080 0.500 ;
    END
  END OUT482
  PIN OUT483
    DIRECTION OUTPUT ;
    USE SIGNAL ;
    PORT
      LAYER Metal2 ;
      RECT 1763.220 0.000 1763.580 0.500 ;
    END
  END OUT483
  PIN OUT484
    DIRECTION OUTPUT ;
    USE SIGNAL ;
    PORT
      LAYER Metal2 ;
      RECT 1766.720 0.000 1767.080 0.500 ;
    END
  END OUT484
  PIN OUT485
    DIRECTION OUTPUT ;
    USE SIGNAL ;
    PORT
      LAYER Metal2 ;
      RECT 1770.220 0.000 1770.580 0.500 ;
    END
  END OUT485
  PIN OUT486
    DIRECTION OUTPUT ;
    USE SIGNAL ;
    PORT
      LAYER Metal2 ;
      RECT 1773.720 0.000 1774.080 0.500 ;
    END
  END OUT486
  PIN OUT487
    DIRECTION OUTPUT ;
    USE SIGNAL ;
    PORT
      LAYER Metal2 ;
      RECT 1777.220 0.000 1777.580 0.500 ;
    END
  END OUT487
  PIN OUT488
    DIRECTION OUTPUT ;
    USE SIGNAL ;
    PORT
      LAYER Metal2 ;
      RECT 1780.720 0.000 1781.080 0.500 ;
    END
  END OUT488
  PIN OUT489
    DIRECTION OUTPUT ;
    USE SIGNAL ;
    PORT
      LAYER Metal2 ;
      RECT 1784.220 0.000 1784.580 0.500 ;
    END
  END OUT489
  PIN OUT490
    DIRECTION OUTPUT ;
    USE SIGNAL ;
    PORT
      LAYER Metal2 ;
      RECT 1787.720 0.000 1788.080 0.500 ;
    END
  END OUT490
  PIN OUT491
    DIRECTION OUTPUT ;
    USE SIGNAL ;
    PORT
      LAYER Metal2 ;
      RECT 1791.220 0.000 1791.580 0.500 ;
    END
  END OUT491
  PIN OUT492
    DIRECTION OUTPUT ;
    USE SIGNAL ;
    PORT
      LAYER Metal2 ;
      RECT 1794.720 0.000 1795.080 0.500 ;
    END
  END OUT492
  PIN OUT493
    DIRECTION OUTPUT ;
    USE SIGNAL ;
    PORT
      LAYER Metal2 ;
      RECT 1798.220 0.000 1798.580 0.500 ;
    END
  END OUT493
  PIN OUT494
    DIRECTION OUTPUT ;
    USE SIGNAL ;
    PORT
      LAYER Metal2 ;
      RECT 1801.720 0.000 1802.080 0.500 ;
    END
  END OUT494
  PIN OUT495
    DIRECTION OUTPUT ;
    USE SIGNAL ;
    PORT
      LAYER Metal2 ;
      RECT 1805.220 0.000 1805.580 0.500 ;
    END
  END OUT495
  PIN OUT496
    DIRECTION OUTPUT ;
    USE SIGNAL ;
    PORT
      LAYER Metal2 ;
      RECT 1808.720 0.000 1809.080 0.500 ;
    END
  END OUT496
  PIN OUT497
    DIRECTION OUTPUT ;
    USE SIGNAL ;
    PORT
      LAYER Metal2 ;
      RECT 1812.220 0.000 1812.580 0.500 ;
    END
  END OUT497
  PIN OUT498
    DIRECTION OUTPUT ;
    USE SIGNAL ;
    PORT
      LAYER Metal2 ;
      RECT 1815.720 0.000 1816.080 0.500 ;
    END
  END OUT498
  PIN OUT499
    DIRECTION OUTPUT ;
    USE SIGNAL ;
    PORT
      LAYER Metal2 ;
      RECT 1819.220 0.000 1819.580 0.500 ;
    END
  END OUT499
  PIN OUT500
    DIRECTION OUTPUT ;
    USE SIGNAL ;
    PORT
      LAYER Metal2 ;
      RECT 1822.720 0.000 1823.080 0.500 ;
    END
  END OUT500
  PIN OUT501
    DIRECTION OUTPUT ;
    USE SIGNAL ;
    PORT
      LAYER Metal2 ;
      RECT 1826.220 0.000 1826.580 0.500 ;
    END
  END OUT501
  PIN OUT502
    DIRECTION OUTPUT ;
    USE SIGNAL ;
    PORT
      LAYER Metal2 ;
      RECT 1829.720 0.000 1830.080 0.500 ;
    END
  END OUT502
  PIN OUT503
    DIRECTION OUTPUT ;
    USE SIGNAL ;
    PORT
      LAYER Metal2 ;
      RECT 1833.220 0.000 1833.580 0.500 ;
    END
  END OUT503
  PIN OUT504
    DIRECTION OUTPUT ;
    USE SIGNAL ;
    PORT
      LAYER Metal2 ;
      RECT 1836.720 0.000 1837.080 0.500 ;
    END
  END OUT504
  PIN OUT505
    DIRECTION OUTPUT ;
    USE SIGNAL ;
    PORT
      LAYER Metal2 ;
      RECT 1840.220 0.000 1840.580 0.500 ;
    END
  END OUT505
  PIN OUT506
    DIRECTION OUTPUT ;
    USE SIGNAL ;
    PORT
      LAYER Metal2 ;
      RECT 1843.720 0.000 1844.080 0.500 ;
    END
  END OUT506
  PIN OUT507
    DIRECTION OUTPUT ;
    USE SIGNAL ;
    PORT
      LAYER Metal2 ;
      RECT 1847.220 0.000 1847.580 0.500 ;
    END
  END OUT507
  PIN OUT508
    DIRECTION OUTPUT ;
    USE SIGNAL ;
    PORT
      LAYER Metal2 ;
      RECT 1850.720 0.000 1851.080 0.500 ;
    END
  END OUT508
  PIN OUT509
    DIRECTION OUTPUT ;
    USE SIGNAL ;
    PORT
      LAYER Metal2 ;
      RECT 1854.220 0.000 1854.580 0.500 ;
    END
  END OUT509
  PIN OUT510
    DIRECTION OUTPUT ;
    USE SIGNAL ;
    PORT
      LAYER Metal2 ;
      RECT 1857.720 0.000 1858.080 0.500 ;
    END
  END OUT510
  PIN OUT511
    DIRECTION OUTPUT ;
    USE SIGNAL ;
    PORT
      LAYER Metal2 ;
      RECT 1861.220 0.000 1861.580 0.500 ;
    END
  END OUT511
  PIN OUT512
    DIRECTION OUTPUT ;
    USE SIGNAL ;
    PORT
      LAYER Metal2 ;
      RECT 1884.720 0.000 1885.080 0.500 ;
    END
  END OUT512
  PIN OUT513
    DIRECTION OUTPUT ;
    USE SIGNAL ;
    PORT
      LAYER Metal2 ;
      RECT 1888.220 0.000 1888.580 0.500 ;
    END
  END OUT513
  PIN OUT514
    DIRECTION OUTPUT ;
    USE SIGNAL ;
    PORT
      LAYER Metal2 ;
      RECT 1891.720 0.000 1892.080 0.500 ;
    END
  END OUT514
  PIN OUT515
    DIRECTION OUTPUT ;
    USE SIGNAL ;
    PORT
      LAYER Metal2 ;
      RECT 1895.220 0.000 1895.580 0.500 ;
    END
  END OUT515
  PIN OUT516
    DIRECTION OUTPUT ;
    USE SIGNAL ;
    PORT
      LAYER Metal2 ;
      RECT 1898.720 0.000 1899.080 0.500 ;
    END
  END OUT516
  PIN OUT517
    DIRECTION OUTPUT ;
    USE SIGNAL ;
    PORT
      LAYER Metal2 ;
      RECT 1902.220 0.000 1902.580 0.500 ;
    END
  END OUT517
  PIN OUT518
    DIRECTION OUTPUT ;
    USE SIGNAL ;
    PORT
      LAYER Metal2 ;
      RECT 1905.720 0.000 1906.080 0.500 ;
    END
  END OUT518
  PIN OUT519
    DIRECTION OUTPUT ;
    USE SIGNAL ;
    PORT
      LAYER Metal2 ;
      RECT 1909.220 0.000 1909.580 0.500 ;
    END
  END OUT519
  PIN OUT520
    DIRECTION OUTPUT ;
    USE SIGNAL ;
    PORT
      LAYER Metal2 ;
      RECT 1912.720 0.000 1913.080 0.500 ;
    END
  END OUT520
  PIN OUT521
    DIRECTION OUTPUT ;
    USE SIGNAL ;
    PORT
      LAYER Metal2 ;
      RECT 1916.220 0.000 1916.580 0.500 ;
    END
  END OUT521
  PIN OUT522
    DIRECTION OUTPUT ;
    USE SIGNAL ;
    PORT
      LAYER Metal2 ;
      RECT 1919.720 0.000 1920.080 0.500 ;
    END
  END OUT522
  PIN OUT523
    DIRECTION OUTPUT ;
    USE SIGNAL ;
    PORT
      LAYER Metal2 ;
      RECT 1923.220 0.000 1923.580 0.500 ;
    END
  END OUT523
  PIN OUT524
    DIRECTION OUTPUT ;
    USE SIGNAL ;
    PORT
      LAYER Metal2 ;
      RECT 1926.720 0.000 1927.080 0.500 ;
    END
  END OUT524
  PIN OUT525
    DIRECTION OUTPUT ;
    USE SIGNAL ;
    PORT
      LAYER Metal2 ;
      RECT 1930.220 0.000 1930.580 0.500 ;
    END
  END OUT525
  PIN OUT526
    DIRECTION OUTPUT ;
    USE SIGNAL ;
    PORT
      LAYER Metal2 ;
      RECT 1933.720 0.000 1934.080 0.500 ;
    END
  END OUT526
  PIN OUT527
    DIRECTION OUTPUT ;
    USE SIGNAL ;
    PORT
      LAYER Metal2 ;
      RECT 1937.220 0.000 1937.580 0.500 ;
    END
  END OUT527
  PIN OUT528
    DIRECTION OUTPUT ;
    USE SIGNAL ;
    PORT
      LAYER Metal2 ;
      RECT 1940.720 0.000 1941.080 0.500 ;
    END
  END OUT528
  PIN OUT529
    DIRECTION OUTPUT ;
    USE SIGNAL ;
    PORT
      LAYER Metal2 ;
      RECT 1944.220 0.000 1944.580 0.500 ;
    END
  END OUT529
  PIN OUT530
    DIRECTION OUTPUT ;
    USE SIGNAL ;
    PORT
      LAYER Metal2 ;
      RECT 1947.720 0.000 1948.080 0.500 ;
    END
  END OUT530
  PIN OUT531
    DIRECTION OUTPUT ;
    USE SIGNAL ;
    PORT
      LAYER Metal2 ;
      RECT 1951.220 0.000 1951.580 0.500 ;
    END
  END OUT531
  PIN OUT532
    DIRECTION OUTPUT ;
    USE SIGNAL ;
    PORT
      LAYER Metal2 ;
      RECT 1954.720 0.000 1955.080 0.500 ;
    END
  END OUT532
  PIN OUT533
    DIRECTION OUTPUT ;
    USE SIGNAL ;
    PORT
      LAYER Metal2 ;
      RECT 1958.220 0.000 1958.580 0.500 ;
    END
  END OUT533
  PIN OUT534
    DIRECTION OUTPUT ;
    USE SIGNAL ;
    PORT
      LAYER Metal2 ;
      RECT 1961.720 0.000 1962.080 0.500 ;
    END
  END OUT534
  PIN OUT535
    DIRECTION OUTPUT ;
    USE SIGNAL ;
    PORT
      LAYER Metal2 ;
      RECT 1965.220 0.000 1965.580 0.500 ;
    END
  END OUT535
  PIN OUT536
    DIRECTION OUTPUT ;
    USE SIGNAL ;
    PORT
      LAYER Metal2 ;
      RECT 1968.720 0.000 1969.080 0.500 ;
    END
  END OUT536
  PIN OUT537
    DIRECTION OUTPUT ;
    USE SIGNAL ;
    PORT
      LAYER Metal2 ;
      RECT 1972.220 0.000 1972.580 0.500 ;
    END
  END OUT537
  PIN OUT538
    DIRECTION OUTPUT ;
    USE SIGNAL ;
    PORT
      LAYER Metal2 ;
      RECT 1975.720 0.000 1976.080 0.500 ;
    END
  END OUT538
  PIN OUT539
    DIRECTION OUTPUT ;
    USE SIGNAL ;
    PORT
      LAYER Metal2 ;
      RECT 1979.220 0.000 1979.580 0.500 ;
    END
  END OUT539
  PIN OUT540
    DIRECTION OUTPUT ;
    USE SIGNAL ;
    PORT
      LAYER Metal2 ;
      RECT 1982.720 0.000 1983.080 0.500 ;
    END
  END OUT540
  PIN OUT541
    DIRECTION OUTPUT ;
    USE SIGNAL ;
    PORT
      LAYER Metal2 ;
      RECT 1986.220 0.000 1986.580 0.500 ;
    END
  END OUT541
  PIN OUT542
    DIRECTION OUTPUT ;
    USE SIGNAL ;
    PORT
      LAYER Metal2 ;
      RECT 1989.720 0.000 1990.080 0.500 ;
    END
  END OUT542
  PIN OUT543
    DIRECTION OUTPUT ;
    USE SIGNAL ;
    PORT
      LAYER Metal2 ;
      RECT 1993.220 0.000 1993.580 0.500 ;
    END
  END OUT543
  PIN OUT544
    DIRECTION OUTPUT ;
    USE SIGNAL ;
    PORT
      LAYER Metal2 ;
      RECT 1996.720 0.000 1997.080 0.500 ;
    END
  END OUT544
  PIN OUT545
    DIRECTION OUTPUT ;
    USE SIGNAL ;
    PORT
      LAYER Metal2 ;
      RECT 2000.220 0.000 2000.580 0.500 ;
    END
  END OUT545
  PIN OUT546
    DIRECTION OUTPUT ;
    USE SIGNAL ;
    PORT
      LAYER Metal2 ;
      RECT 2003.720 0.000 2004.080 0.500 ;
    END
  END OUT546
  PIN OUT547
    DIRECTION OUTPUT ;
    USE SIGNAL ;
    PORT
      LAYER Metal2 ;
      RECT 2007.220 0.000 2007.580 0.500 ;
    END
  END OUT547
  PIN OUT548
    DIRECTION OUTPUT ;
    USE SIGNAL ;
    PORT
      LAYER Metal2 ;
      RECT 2010.720 0.000 2011.080 0.500 ;
    END
  END OUT548
  PIN OUT549
    DIRECTION OUTPUT ;
    USE SIGNAL ;
    PORT
      LAYER Metal2 ;
      RECT 2014.220 0.000 2014.580 0.500 ;
    END
  END OUT549
  PIN OUT550
    DIRECTION OUTPUT ;
    USE SIGNAL ;
    PORT
      LAYER Metal2 ;
      RECT 2017.720 0.000 2018.080 0.500 ;
    END
  END OUT550
  PIN OUT551
    DIRECTION OUTPUT ;
    USE SIGNAL ;
    PORT
      LAYER Metal2 ;
      RECT 2021.220 0.000 2021.580 0.500 ;
    END
  END OUT551
  PIN OUT552
    DIRECTION OUTPUT ;
    USE SIGNAL ;
    PORT
      LAYER Metal2 ;
      RECT 2024.720 0.000 2025.080 0.500 ;
    END
  END OUT552
  PIN OUT553
    DIRECTION OUTPUT ;
    USE SIGNAL ;
    PORT
      LAYER Metal2 ;
      RECT 2028.220 0.000 2028.580 0.500 ;
    END
  END OUT553
  PIN OUT554
    DIRECTION OUTPUT ;
    USE SIGNAL ;
    PORT
      LAYER Metal2 ;
      RECT 2031.720 0.000 2032.080 0.500 ;
    END
  END OUT554
  PIN OUT555
    DIRECTION OUTPUT ;
    USE SIGNAL ;
    PORT
      LAYER Metal2 ;
      RECT 2035.220 0.000 2035.580 0.500 ;
    END
  END OUT555
  PIN OUT556
    DIRECTION OUTPUT ;
    USE SIGNAL ;
    PORT
      LAYER Metal2 ;
      RECT 2038.720 0.000 2039.080 0.500 ;
    END
  END OUT556
  PIN OUT557
    DIRECTION OUTPUT ;
    USE SIGNAL ;
    PORT
      LAYER Metal2 ;
      RECT 2042.220 0.000 2042.580 0.500 ;
    END
  END OUT557
  PIN OUT558
    DIRECTION OUTPUT ;
    USE SIGNAL ;
    PORT
      LAYER Metal2 ;
      RECT 2045.720 0.000 2046.080 0.500 ;
    END
  END OUT558
  PIN OUT559
    DIRECTION OUTPUT ;
    USE SIGNAL ;
    PORT
      LAYER Metal2 ;
      RECT 2049.220 0.000 2049.580 0.500 ;
    END
  END OUT559
  PIN OUT560
    DIRECTION OUTPUT ;
    USE SIGNAL ;
    PORT
      LAYER Metal2 ;
      RECT 2052.720 0.000 2053.080 0.500 ;
    END
  END OUT560
  PIN OUT561
    DIRECTION OUTPUT ;
    USE SIGNAL ;
    PORT
      LAYER Metal2 ;
      RECT 2056.220 0.000 2056.580 0.500 ;
    END
  END OUT561
  PIN OUT562
    DIRECTION OUTPUT ;
    USE SIGNAL ;
    PORT
      LAYER Metal2 ;
      RECT 2059.720 0.000 2060.080 0.500 ;
    END
  END OUT562
  PIN OUT563
    DIRECTION OUTPUT ;
    USE SIGNAL ;
    PORT
      LAYER Metal2 ;
      RECT 2063.220 0.000 2063.580 0.500 ;
    END
  END OUT563
  PIN OUT564
    DIRECTION OUTPUT ;
    USE SIGNAL ;
    PORT
      LAYER Metal2 ;
      RECT 2066.720 0.000 2067.080 0.500 ;
    END
  END OUT564
  PIN OUT565
    DIRECTION OUTPUT ;
    USE SIGNAL ;
    PORT
      LAYER Metal2 ;
      RECT 2070.220 0.000 2070.580 0.500 ;
    END
  END OUT565
  PIN OUT566
    DIRECTION OUTPUT ;
    USE SIGNAL ;
    PORT
      LAYER Metal2 ;
      RECT 2073.720 0.000 2074.080 0.500 ;
    END
  END OUT566
  PIN OUT567
    DIRECTION OUTPUT ;
    USE SIGNAL ;
    PORT
      LAYER Metal2 ;
      RECT 2077.220 0.000 2077.580 0.500 ;
    END
  END OUT567
  PIN OUT568
    DIRECTION OUTPUT ;
    USE SIGNAL ;
    PORT
      LAYER Metal2 ;
      RECT 2080.720 0.000 2081.080 0.500 ;
    END
  END OUT568
  PIN OUT569
    DIRECTION OUTPUT ;
    USE SIGNAL ;
    PORT
      LAYER Metal2 ;
      RECT 2084.220 0.000 2084.580 0.500 ;
    END
  END OUT569
  PIN OUT570
    DIRECTION OUTPUT ;
    USE SIGNAL ;
    PORT
      LAYER Metal2 ;
      RECT 2087.720 0.000 2088.080 0.500 ;
    END
  END OUT570
  PIN OUT571
    DIRECTION OUTPUT ;
    USE SIGNAL ;
    PORT
      LAYER Metal2 ;
      RECT 2091.220 0.000 2091.580 0.500 ;
    END
  END OUT571
  PIN OUT572
    DIRECTION OUTPUT ;
    USE SIGNAL ;
    PORT
      LAYER Metal2 ;
      RECT 2094.720 0.000 2095.080 0.500 ;
    END
  END OUT572
  PIN OUT573
    DIRECTION OUTPUT ;
    USE SIGNAL ;
    PORT
      LAYER Metal2 ;
      RECT 2098.220 0.000 2098.580 0.500 ;
    END
  END OUT573
  PIN OUT574
    DIRECTION OUTPUT ;
    USE SIGNAL ;
    PORT
      LAYER Metal2 ;
      RECT 2101.720 0.000 2102.080 0.500 ;
    END
  END OUT574
  PIN OUT575
    DIRECTION OUTPUT ;
    USE SIGNAL ;
    PORT
      LAYER Metal2 ;
      RECT 2105.220 0.000 2105.580 0.500 ;
    END
  END OUT575
  PIN OUT576
    DIRECTION OUTPUT ;
    USE SIGNAL ;
    PORT
      LAYER Metal2 ;
      RECT 2108.720 0.000 2109.080 0.500 ;
    END
  END OUT576
  PIN OUT577
    DIRECTION OUTPUT ;
    USE SIGNAL ;
    PORT
      LAYER Metal2 ;
      RECT 2112.220 0.000 2112.580 0.500 ;
    END
  END OUT577
  PIN OUT578
    DIRECTION OUTPUT ;
    USE SIGNAL ;
    PORT
      LAYER Metal2 ;
      RECT 2115.720 0.000 2116.080 0.500 ;
    END
  END OUT578
  PIN OUT579
    DIRECTION OUTPUT ;
    USE SIGNAL ;
    PORT
      LAYER Metal2 ;
      RECT 2119.220 0.000 2119.580 0.500 ;
    END
  END OUT579
  PIN OUT580
    DIRECTION OUTPUT ;
    USE SIGNAL ;
    PORT
      LAYER Metal2 ;
      RECT 2122.720 0.000 2123.080 0.500 ;
    END
  END OUT580
  PIN OUT581
    DIRECTION OUTPUT ;
    USE SIGNAL ;
    PORT
      LAYER Metal2 ;
      RECT 2126.220 0.000 2126.580 0.500 ;
    END
  END OUT581
  PIN OUT582
    DIRECTION OUTPUT ;
    USE SIGNAL ;
    PORT
      LAYER Metal2 ;
      RECT 2129.720 0.000 2130.080 0.500 ;
    END
  END OUT582
  PIN OUT583
    DIRECTION OUTPUT ;
    USE SIGNAL ;
    PORT
      LAYER Metal2 ;
      RECT 2133.220 0.000 2133.580 0.500 ;
    END
  END OUT583
  PIN OUT584
    DIRECTION OUTPUT ;
    USE SIGNAL ;
    PORT
      LAYER Metal2 ;
      RECT 2136.720 0.000 2137.080 0.500 ;
    END
  END OUT584
  PIN OUT585
    DIRECTION OUTPUT ;
    USE SIGNAL ;
    PORT
      LAYER Metal2 ;
      RECT 2140.220 0.000 2140.580 0.500 ;
    END
  END OUT585
  PIN OUT586
    DIRECTION OUTPUT ;
    USE SIGNAL ;
    PORT
      LAYER Metal2 ;
      RECT 2143.720 0.000 2144.080 0.500 ;
    END
  END OUT586
  PIN OUT587
    DIRECTION OUTPUT ;
    USE SIGNAL ;
    PORT
      LAYER Metal2 ;
      RECT 2147.220 0.000 2147.580 0.500 ;
    END
  END OUT587
  PIN OUT588
    DIRECTION OUTPUT ;
    USE SIGNAL ;
    PORT
      LAYER Metal2 ;
      RECT 2150.720 0.000 2151.080 0.500 ;
    END
  END OUT588
  PIN OUT589
    DIRECTION OUTPUT ;
    USE SIGNAL ;
    PORT
      LAYER Metal2 ;
      RECT 2154.220 0.000 2154.580 0.500 ;
    END
  END OUT589
  PIN OUT590
    DIRECTION OUTPUT ;
    USE SIGNAL ;
    PORT
      LAYER Metal2 ;
      RECT 2157.720 0.000 2158.080 0.500 ;
    END
  END OUT590
  PIN OUT591
    DIRECTION OUTPUT ;
    USE SIGNAL ;
    PORT
      LAYER Metal2 ;
      RECT 2161.220 0.000 2161.580 0.500 ;
    END
  END OUT591
  PIN OUT592
    DIRECTION OUTPUT ;
    USE SIGNAL ;
    PORT
      LAYER Metal2 ;
      RECT 2164.720 0.000 2165.080 0.500 ;
    END
  END OUT592
  PIN OUT593
    DIRECTION OUTPUT ;
    USE SIGNAL ;
    PORT
      LAYER Metal2 ;
      RECT 2168.220 0.000 2168.580 0.500 ;
    END
  END OUT593
  PIN OUT594
    DIRECTION OUTPUT ;
    USE SIGNAL ;
    PORT
      LAYER Metal2 ;
      RECT 2171.720 0.000 2172.080 0.500 ;
    END
  END OUT594
  PIN OUT595
    DIRECTION OUTPUT ;
    USE SIGNAL ;
    PORT
      LAYER Metal2 ;
      RECT 2175.220 0.000 2175.580 0.500 ;
    END
  END OUT595
  PIN OUT596
    DIRECTION OUTPUT ;
    USE SIGNAL ;
    PORT
      LAYER Metal2 ;
      RECT 2178.720 0.000 2179.080 0.500 ;
    END
  END OUT596
  PIN OUT597
    DIRECTION OUTPUT ;
    USE SIGNAL ;
    PORT
      LAYER Metal2 ;
      RECT 2182.220 0.000 2182.580 0.500 ;
    END
  END OUT597
  PIN OUT598
    DIRECTION OUTPUT ;
    USE SIGNAL ;
    PORT
      LAYER Metal2 ;
      RECT 2185.720 0.000 2186.080 0.500 ;
    END
  END OUT598
  PIN OUT599
    DIRECTION OUTPUT ;
    USE SIGNAL ;
    PORT
      LAYER Metal2 ;
      RECT 2189.220 0.000 2189.580 0.500 ;
    END
  END OUT599
  PIN OUT600
    DIRECTION OUTPUT ;
    USE SIGNAL ;
    PORT
      LAYER Metal2 ;
      RECT 2192.720 0.000 2193.080 0.500 ;
    END
  END OUT600
  PIN OUT601
    DIRECTION OUTPUT ;
    USE SIGNAL ;
    PORT
      LAYER Metal2 ;
      RECT 2196.220 0.000 2196.580 0.500 ;
    END
  END OUT601
  PIN OUT602
    DIRECTION OUTPUT ;
    USE SIGNAL ;
    PORT
      LAYER Metal2 ;
      RECT 2199.720 0.000 2200.080 0.500 ;
    END
  END OUT602
  PIN OUT603
    DIRECTION OUTPUT ;
    USE SIGNAL ;
    PORT
      LAYER Metal2 ;
      RECT 2203.220 0.000 2203.580 0.500 ;
    END
  END OUT603
  PIN OUT604
    DIRECTION OUTPUT ;
    USE SIGNAL ;
    PORT
      LAYER Metal2 ;
      RECT 2206.720 0.000 2207.080 0.500 ;
    END
  END OUT604
  PIN OUT605
    DIRECTION OUTPUT ;
    USE SIGNAL ;
    PORT
      LAYER Metal2 ;
      RECT 2210.220 0.000 2210.580 0.500 ;
    END
  END OUT605
  PIN OUT606
    DIRECTION OUTPUT ;
    USE SIGNAL ;
    PORT
      LAYER Metal2 ;
      RECT 2213.720 0.000 2214.080 0.500 ;
    END
  END OUT606
  PIN OUT607
    DIRECTION OUTPUT ;
    USE SIGNAL ;
    PORT
      LAYER Metal2 ;
      RECT 2217.220 0.000 2217.580 0.500 ;
    END
  END OUT607
  PIN OUT608
    DIRECTION OUTPUT ;
    USE SIGNAL ;
    PORT
      LAYER Metal2 ;
      RECT 2220.720 0.000 2221.080 0.500 ;
    END
  END OUT608
  PIN OUT609
    DIRECTION OUTPUT ;
    USE SIGNAL ;
    PORT
      LAYER Metal2 ;
      RECT 2224.220 0.000 2224.580 0.500 ;
    END
  END OUT609
  PIN OUT610
    DIRECTION OUTPUT ;
    USE SIGNAL ;
    PORT
      LAYER Metal2 ;
      RECT 2227.720 0.000 2228.080 0.500 ;
    END
  END OUT610
  PIN OUT611
    DIRECTION OUTPUT ;
    USE SIGNAL ;
    PORT
      LAYER Metal2 ;
      RECT 2231.220 0.000 2231.580 0.500 ;
    END
  END OUT611
  PIN OUT612
    DIRECTION OUTPUT ;
    USE SIGNAL ;
    PORT
      LAYER Metal2 ;
      RECT 2234.720 0.000 2235.080 0.500 ;
    END
  END OUT612
  PIN OUT613
    DIRECTION OUTPUT ;
    USE SIGNAL ;
    PORT
      LAYER Metal2 ;
      RECT 2238.220 0.000 2238.580 0.500 ;
    END
  END OUT613
  PIN OUT614
    DIRECTION OUTPUT ;
    USE SIGNAL ;
    PORT
      LAYER Metal2 ;
      RECT 2241.720 0.000 2242.080 0.500 ;
    END
  END OUT614
  PIN OUT615
    DIRECTION OUTPUT ;
    USE SIGNAL ;
    PORT
      LAYER Metal2 ;
      RECT 2245.220 0.000 2245.580 0.500 ;
    END
  END OUT615
  PIN OUT616
    DIRECTION OUTPUT ;
    USE SIGNAL ;
    PORT
      LAYER Metal2 ;
      RECT 2248.720 0.000 2249.080 0.500 ;
    END
  END OUT616
  PIN OUT617
    DIRECTION OUTPUT ;
    USE SIGNAL ;
    PORT
      LAYER Metal2 ;
      RECT 2252.220 0.000 2252.580 0.500 ;
    END
  END OUT617
  PIN OUT618
    DIRECTION OUTPUT ;
    USE SIGNAL ;
    PORT
      LAYER Metal2 ;
      RECT 2255.720 0.000 2256.080 0.500 ;
    END
  END OUT618
  PIN OUT619
    DIRECTION OUTPUT ;
    USE SIGNAL ;
    PORT
      LAYER Metal2 ;
      RECT 2259.220 0.000 2259.580 0.500 ;
    END
  END OUT619
  PIN OUT620
    DIRECTION OUTPUT ;
    USE SIGNAL ;
    PORT
      LAYER Metal2 ;
      RECT 2262.720 0.000 2263.080 0.500 ;
    END
  END OUT620
  PIN OUT621
    DIRECTION OUTPUT ;
    USE SIGNAL ;
    PORT
      LAYER Metal2 ;
      RECT 2266.220 0.000 2266.580 0.500 ;
    END
  END OUT621
  PIN OUT622
    DIRECTION OUTPUT ;
    USE SIGNAL ;
    PORT
      LAYER Metal2 ;
      RECT 2269.720 0.000 2270.080 0.500 ;
    END
  END OUT622
  PIN OUT623
    DIRECTION OUTPUT ;
    USE SIGNAL ;
    PORT
      LAYER Metal2 ;
      RECT 2273.220 0.000 2273.580 0.500 ;
    END
  END OUT623
  PIN OUT624
    DIRECTION OUTPUT ;
    USE SIGNAL ;
    PORT
      LAYER Metal2 ;
      RECT 2276.720 0.000 2277.080 0.500 ;
    END
  END OUT624
  PIN OUT625
    DIRECTION OUTPUT ;
    USE SIGNAL ;
    PORT
      LAYER Metal2 ;
      RECT 2280.220 0.000 2280.580 0.500 ;
    END
  END OUT625
  PIN OUT626
    DIRECTION OUTPUT ;
    USE SIGNAL ;
    PORT
      LAYER Metal2 ;
      RECT 2283.720 0.000 2284.080 0.500 ;
    END
  END OUT626
  PIN OUT627
    DIRECTION OUTPUT ;
    USE SIGNAL ;
    PORT
      LAYER Metal2 ;
      RECT 2287.220 0.000 2287.580 0.500 ;
    END
  END OUT627
  PIN OUT628
    DIRECTION OUTPUT ;
    USE SIGNAL ;
    PORT
      LAYER Metal2 ;
      RECT 2290.720 0.000 2291.080 0.500 ;
    END
  END OUT628
  PIN OUT629
    DIRECTION OUTPUT ;
    USE SIGNAL ;
    PORT
      LAYER Metal2 ;
      RECT 2294.220 0.000 2294.580 0.500 ;
    END
  END OUT629
  PIN OUT630
    DIRECTION OUTPUT ;
    USE SIGNAL ;
    PORT
      LAYER Metal2 ;
      RECT 2297.720 0.000 2298.080 0.500 ;
    END
  END OUT630
  PIN OUT631
    DIRECTION OUTPUT ;
    USE SIGNAL ;
    PORT
      LAYER Metal2 ;
      RECT 2301.220 0.000 2301.580 0.500 ;
    END
  END OUT631
  PIN OUT632
    DIRECTION OUTPUT ;
    USE SIGNAL ;
    PORT
      LAYER Metal2 ;
      RECT 2304.720 0.000 2305.080 0.500 ;
    END
  END OUT632
  PIN OUT633
    DIRECTION OUTPUT ;
    USE SIGNAL ;
    PORT
      LAYER Metal2 ;
      RECT 2308.220 0.000 2308.580 0.500 ;
    END
  END OUT633
  PIN OUT634
    DIRECTION OUTPUT ;
    USE SIGNAL ;
    PORT
      LAYER Metal2 ;
      RECT 2311.720 0.000 2312.080 0.500 ;
    END
  END OUT634
  PIN OUT635
    DIRECTION OUTPUT ;
    USE SIGNAL ;
    PORT
      LAYER Metal2 ;
      RECT 2315.220 0.000 2315.580 0.500 ;
    END
  END OUT635
  PIN OUT636
    DIRECTION OUTPUT ;
    USE SIGNAL ;
    PORT
      LAYER Metal2 ;
      RECT 2318.720 0.000 2319.080 0.500 ;
    END
  END OUT636
  PIN OUT637
    DIRECTION OUTPUT ;
    USE SIGNAL ;
    PORT
      LAYER Metal2 ;
      RECT 2322.220 0.000 2322.580 0.500 ;
    END
  END OUT637
  PIN OUT638
    DIRECTION OUTPUT ;
    USE SIGNAL ;
    PORT
      LAYER Metal2 ;
      RECT 2325.720 0.000 2326.080 0.500 ;
    END
  END OUT638
  PIN OUT639
    DIRECTION OUTPUT ;
    USE SIGNAL ;
    PORT
      LAYER Metal2 ;
      RECT 2329.220 0.000 2329.580 0.500 ;
    END
  END OUT639
  PIN OUT640
    DIRECTION OUTPUT ;
    USE SIGNAL ;
    PORT
      LAYER Metal2 ;
      RECT 2352.720 0.000 2353.080 0.500 ;
    END
  END OUT640
  PIN OUT641
    DIRECTION OUTPUT ;
    USE SIGNAL ;
    PORT
      LAYER Metal2 ;
      RECT 2356.220 0.000 2356.580 0.500 ;
    END
  END OUT641
  PIN OUT642
    DIRECTION OUTPUT ;
    USE SIGNAL ;
    PORT
      LAYER Metal2 ;
      RECT 2359.720 0.000 2360.080 0.500 ;
    END
  END OUT642
  PIN OUT643
    DIRECTION OUTPUT ;
    USE SIGNAL ;
    PORT
      LAYER Metal2 ;
      RECT 2363.220 0.000 2363.580 0.500 ;
    END
  END OUT643
  PIN OUT644
    DIRECTION OUTPUT ;
    USE SIGNAL ;
    PORT
      LAYER Metal2 ;
      RECT 2366.720 0.000 2367.080 0.500 ;
    END
  END OUT644
  PIN OUT645
    DIRECTION OUTPUT ;
    USE SIGNAL ;
    PORT
      LAYER Metal2 ;
      RECT 2370.220 0.000 2370.580 0.500 ;
    END
  END OUT645
  PIN OUT646
    DIRECTION OUTPUT ;
    USE SIGNAL ;
    PORT
      LAYER Metal2 ;
      RECT 2373.720 0.000 2374.080 0.500 ;
    END
  END OUT646
  PIN OUT647
    DIRECTION OUTPUT ;
    USE SIGNAL ;
    PORT
      LAYER Metal2 ;
      RECT 2377.220 0.000 2377.580 0.500 ;
    END
  END OUT647
  PIN OUT648
    DIRECTION OUTPUT ;
    USE SIGNAL ;
    PORT
      LAYER Metal2 ;
      RECT 2380.720 0.000 2381.080 0.500 ;
    END
  END OUT648
  PIN OUT649
    DIRECTION OUTPUT ;
    USE SIGNAL ;
    PORT
      LAYER Metal2 ;
      RECT 2384.220 0.000 2384.580 0.500 ;
    END
  END OUT649
  PIN OUT650
    DIRECTION OUTPUT ;
    USE SIGNAL ;
    PORT
      LAYER Metal2 ;
      RECT 2387.720 0.000 2388.080 0.500 ;
    END
  END OUT650
  PIN OUT651
    DIRECTION OUTPUT ;
    USE SIGNAL ;
    PORT
      LAYER Metal2 ;
      RECT 2391.220 0.000 2391.580 0.500 ;
    END
  END OUT651
  PIN OUT652
    DIRECTION OUTPUT ;
    USE SIGNAL ;
    PORT
      LAYER Metal2 ;
      RECT 2394.720 0.000 2395.080 0.500 ;
    END
  END OUT652
  PIN OUT653
    DIRECTION OUTPUT ;
    USE SIGNAL ;
    PORT
      LAYER Metal2 ;
      RECT 2398.220 0.000 2398.580 0.500 ;
    END
  END OUT653
  PIN OUT654
    DIRECTION OUTPUT ;
    USE SIGNAL ;
    PORT
      LAYER Metal2 ;
      RECT 2401.720 0.000 2402.080 0.500 ;
    END
  END OUT654
  PIN OUT655
    DIRECTION OUTPUT ;
    USE SIGNAL ;
    PORT
      LAYER Metal2 ;
      RECT 2405.220 0.000 2405.580 0.500 ;
    END
  END OUT655
  PIN OUT656
    DIRECTION OUTPUT ;
    USE SIGNAL ;
    PORT
      LAYER Metal2 ;
      RECT 2408.720 0.000 2409.080 0.500 ;
    END
  END OUT656
  PIN OUT657
    DIRECTION OUTPUT ;
    USE SIGNAL ;
    PORT
      LAYER Metal2 ;
      RECT 2412.220 0.000 2412.580 0.500 ;
    END
  END OUT657
  PIN OUT658
    DIRECTION OUTPUT ;
    USE SIGNAL ;
    PORT
      LAYER Metal2 ;
      RECT 2415.720 0.000 2416.080 0.500 ;
    END
  END OUT658
  PIN OUT659
    DIRECTION OUTPUT ;
    USE SIGNAL ;
    PORT
      LAYER Metal2 ;
      RECT 2419.220 0.000 2419.580 0.500 ;
    END
  END OUT659
  PIN OUT660
    DIRECTION OUTPUT ;
    USE SIGNAL ;
    PORT
      LAYER Metal2 ;
      RECT 2422.720 0.000 2423.080 0.500 ;
    END
  END OUT660
  PIN OUT661
    DIRECTION OUTPUT ;
    USE SIGNAL ;
    PORT
      LAYER Metal2 ;
      RECT 2426.220 0.000 2426.580 0.500 ;
    END
  END OUT661
  PIN OUT662
    DIRECTION OUTPUT ;
    USE SIGNAL ;
    PORT
      LAYER Metal2 ;
      RECT 2429.720 0.000 2430.080 0.500 ;
    END
  END OUT662
  PIN OUT663
    DIRECTION OUTPUT ;
    USE SIGNAL ;
    PORT
      LAYER Metal2 ;
      RECT 2433.220 0.000 2433.580 0.500 ;
    END
  END OUT663
  PIN OUT664
    DIRECTION OUTPUT ;
    USE SIGNAL ;
    PORT
      LAYER Metal2 ;
      RECT 2436.720 0.000 2437.080 0.500 ;
    END
  END OUT664
  PIN OUT665
    DIRECTION OUTPUT ;
    USE SIGNAL ;
    PORT
      LAYER Metal2 ;
      RECT 2440.220 0.000 2440.580 0.500 ;
    END
  END OUT665
  PIN OUT666
    DIRECTION OUTPUT ;
    USE SIGNAL ;
    PORT
      LAYER Metal2 ;
      RECT 2443.720 0.000 2444.080 0.500 ;
    END
  END OUT666
  PIN OUT667
    DIRECTION OUTPUT ;
    USE SIGNAL ;
    PORT
      LAYER Metal2 ;
      RECT 2447.220 0.000 2447.580 0.500 ;
    END
  END OUT667
  PIN OUT668
    DIRECTION OUTPUT ;
    USE SIGNAL ;
    PORT
      LAYER Metal2 ;
      RECT 2450.720 0.000 2451.080 0.500 ;
    END
  END OUT668
  PIN OUT669
    DIRECTION OUTPUT ;
    USE SIGNAL ;
    PORT
      LAYER Metal2 ;
      RECT 2454.220 0.000 2454.580 0.500 ;
    END
  END OUT669
  PIN OUT670
    DIRECTION OUTPUT ;
    USE SIGNAL ;
    PORT
      LAYER Metal2 ;
      RECT 2457.720 0.000 2458.080 0.500 ;
    END
  END OUT670
  PIN OUT671
    DIRECTION OUTPUT ;
    USE SIGNAL ;
    PORT
      LAYER Metal2 ;
      RECT 2461.220 0.000 2461.580 0.500 ;
    END
  END OUT671
  PIN OUT672
    DIRECTION OUTPUT ;
    USE SIGNAL ;
    PORT
      LAYER Metal2 ;
      RECT 2464.720 0.000 2465.080 0.500 ;
    END
  END OUT672
  PIN OUT673
    DIRECTION OUTPUT ;
    USE SIGNAL ;
    PORT
      LAYER Metal2 ;
      RECT 2468.220 0.000 2468.580 0.500 ;
    END
  END OUT673
  PIN OUT674
    DIRECTION OUTPUT ;
    USE SIGNAL ;
    PORT
      LAYER Metal2 ;
      RECT 2471.720 0.000 2472.080 0.500 ;
    END
  END OUT674
  PIN OUT675
    DIRECTION OUTPUT ;
    USE SIGNAL ;
    PORT
      LAYER Metal2 ;
      RECT 2475.220 0.000 2475.580 0.500 ;
    END
  END OUT675
  PIN OUT676
    DIRECTION OUTPUT ;
    USE SIGNAL ;
    PORT
      LAYER Metal2 ;
      RECT 2478.720 0.000 2479.080 0.500 ;
    END
  END OUT676
  PIN OUT677
    DIRECTION OUTPUT ;
    USE SIGNAL ;
    PORT
      LAYER Metal2 ;
      RECT 2482.220 0.000 2482.580 0.500 ;
    END
  END OUT677
  PIN OUT678
    DIRECTION OUTPUT ;
    USE SIGNAL ;
    PORT
      LAYER Metal2 ;
      RECT 2485.720 0.000 2486.080 0.500 ;
    END
  END OUT678
  PIN OUT679
    DIRECTION OUTPUT ;
    USE SIGNAL ;
    PORT
      LAYER Metal2 ;
      RECT 2489.220 0.000 2489.580 0.500 ;
    END
  END OUT679
  PIN OUT680
    DIRECTION OUTPUT ;
    USE SIGNAL ;
    PORT
      LAYER Metal2 ;
      RECT 2492.720 0.000 2493.080 0.500 ;
    END
  END OUT680
  PIN OUT681
    DIRECTION OUTPUT ;
    USE SIGNAL ;
    PORT
      LAYER Metal2 ;
      RECT 2496.220 0.000 2496.580 0.500 ;
    END
  END OUT681
  PIN OUT682
    DIRECTION OUTPUT ;
    USE SIGNAL ;
    PORT
      LAYER Metal2 ;
      RECT 2499.720 0.000 2500.080 0.500 ;
    END
  END OUT682
  PIN OUT683
    DIRECTION OUTPUT ;
    USE SIGNAL ;
    PORT
      LAYER Metal2 ;
      RECT 2503.220 0.000 2503.580 0.500 ;
    END
  END OUT683
  PIN OUT684
    DIRECTION OUTPUT ;
    USE SIGNAL ;
    PORT
      LAYER Metal2 ;
      RECT 2506.720 0.000 2507.080 0.500 ;
    END
  END OUT684
  PIN OUT685
    DIRECTION OUTPUT ;
    USE SIGNAL ;
    PORT
      LAYER Metal2 ;
      RECT 2510.220 0.000 2510.580 0.500 ;
    END
  END OUT685
  PIN OUT686
    DIRECTION OUTPUT ;
    USE SIGNAL ;
    PORT
      LAYER Metal2 ;
      RECT 2513.720 0.000 2514.080 0.500 ;
    END
  END OUT686
  PIN OUT687
    DIRECTION OUTPUT ;
    USE SIGNAL ;
    PORT
      LAYER Metal2 ;
      RECT 2517.220 0.000 2517.580 0.500 ;
    END
  END OUT687
  PIN OUT688
    DIRECTION OUTPUT ;
    USE SIGNAL ;
    PORT
      LAYER Metal2 ;
      RECT 2520.720 0.000 2521.080 0.500 ;
    END
  END OUT688
  PIN OUT689
    DIRECTION OUTPUT ;
    USE SIGNAL ;
    PORT
      LAYER Metal2 ;
      RECT 2524.220 0.000 2524.580 0.500 ;
    END
  END OUT689
  PIN OUT690
    DIRECTION OUTPUT ;
    USE SIGNAL ;
    PORT
      LAYER Metal2 ;
      RECT 2527.720 0.000 2528.080 0.500 ;
    END
  END OUT690
  PIN OUT691
    DIRECTION OUTPUT ;
    USE SIGNAL ;
    PORT
      LAYER Metal2 ;
      RECT 2531.220 0.000 2531.580 0.500 ;
    END
  END OUT691
  PIN OUT692
    DIRECTION OUTPUT ;
    USE SIGNAL ;
    PORT
      LAYER Metal2 ;
      RECT 2534.720 0.000 2535.080 0.500 ;
    END
  END OUT692
  PIN OUT693
    DIRECTION OUTPUT ;
    USE SIGNAL ;
    PORT
      LAYER Metal2 ;
      RECT 2538.220 0.000 2538.580 0.500 ;
    END
  END OUT693
  PIN OUT694
    DIRECTION OUTPUT ;
    USE SIGNAL ;
    PORT
      LAYER Metal2 ;
      RECT 2541.720 0.000 2542.080 0.500 ;
    END
  END OUT694
  PIN OUT695
    DIRECTION OUTPUT ;
    USE SIGNAL ;
    PORT
      LAYER Metal2 ;
      RECT 2545.220 0.000 2545.580 0.500 ;
    END
  END OUT695
  PIN OUT696
    DIRECTION OUTPUT ;
    USE SIGNAL ;
    PORT
      LAYER Metal2 ;
      RECT 2548.720 0.000 2549.080 0.500 ;
    END
  END OUT696
  PIN OUT697
    DIRECTION OUTPUT ;
    USE SIGNAL ;
    PORT
      LAYER Metal2 ;
      RECT 2552.220 0.000 2552.580 0.500 ;
    END
  END OUT697
  PIN OUT698
    DIRECTION OUTPUT ;
    USE SIGNAL ;
    PORT
      LAYER Metal2 ;
      RECT 2555.720 0.000 2556.080 0.500 ;
    END
  END OUT698
  PIN OUT699
    DIRECTION OUTPUT ;
    USE SIGNAL ;
    PORT
      LAYER Metal2 ;
      RECT 2559.220 0.000 2559.580 0.500 ;
    END
  END OUT699
  PIN OUT700
    DIRECTION OUTPUT ;
    USE SIGNAL ;
    PORT
      LAYER Metal2 ;
      RECT 2562.720 0.000 2563.080 0.500 ;
    END
  END OUT700
  PIN OUT701
    DIRECTION OUTPUT ;
    USE SIGNAL ;
    PORT
      LAYER Metal2 ;
      RECT 2566.220 0.000 2566.580 0.500 ;
    END
  END OUT701
  PIN OUT702
    DIRECTION OUTPUT ;
    USE SIGNAL ;
    PORT
      LAYER Metal2 ;
      RECT 2569.720 0.000 2570.080 0.500 ;
    END
  END OUT702
  PIN OUT703
    DIRECTION OUTPUT ;
    USE SIGNAL ;
    PORT
      LAYER Metal2 ;
      RECT 2573.220 0.000 2573.580 0.500 ;
    END
  END OUT703
  PIN OUT704
    DIRECTION OUTPUT ;
    USE SIGNAL ;
    PORT
      LAYER Metal2 ;
      RECT 2576.720 0.000 2577.080 0.500 ;
    END
  END OUT704
  PIN OUT705
    DIRECTION OUTPUT ;
    USE SIGNAL ;
    PORT
      LAYER Metal2 ;
      RECT 2580.220 0.000 2580.580 0.500 ;
    END
  END OUT705
  PIN OUT706
    DIRECTION OUTPUT ;
    USE SIGNAL ;
    PORT
      LAYER Metal2 ;
      RECT 2583.720 0.000 2584.080 0.500 ;
    END
  END OUT706
  PIN OUT707
    DIRECTION OUTPUT ;
    USE SIGNAL ;
    PORT
      LAYER Metal2 ;
      RECT 2587.220 0.000 2587.580 0.500 ;
    END
  END OUT707
  PIN OUT708
    DIRECTION OUTPUT ;
    USE SIGNAL ;
    PORT
      LAYER Metal2 ;
      RECT 2590.720 0.000 2591.080 0.500 ;
    END
  END OUT708
  PIN OUT709
    DIRECTION OUTPUT ;
    USE SIGNAL ;
    PORT
      LAYER Metal2 ;
      RECT 2594.220 0.000 2594.580 0.500 ;
    END
  END OUT709
  PIN OUT710
    DIRECTION OUTPUT ;
    USE SIGNAL ;
    PORT
      LAYER Metal2 ;
      RECT 2597.720 0.000 2598.080 0.500 ;
    END
  END OUT710
  PIN OUT711
    DIRECTION OUTPUT ;
    USE SIGNAL ;
    PORT
      LAYER Metal2 ;
      RECT 2601.220 0.000 2601.580 0.500 ;
    END
  END OUT711
  PIN OUT712
    DIRECTION OUTPUT ;
    USE SIGNAL ;
    PORT
      LAYER Metal2 ;
      RECT 2604.720 0.000 2605.080 0.500 ;
    END
  END OUT712
  PIN OUT713
    DIRECTION OUTPUT ;
    USE SIGNAL ;
    PORT
      LAYER Metal2 ;
      RECT 2608.220 0.000 2608.580 0.500 ;
    END
  END OUT713
  PIN OUT714
    DIRECTION OUTPUT ;
    USE SIGNAL ;
    PORT
      LAYER Metal2 ;
      RECT 2611.720 0.000 2612.080 0.500 ;
    END
  END OUT714
  PIN OUT715
    DIRECTION OUTPUT ;
    USE SIGNAL ;
    PORT
      LAYER Metal2 ;
      RECT 2615.220 0.000 2615.580 0.500 ;
    END
  END OUT715
  PIN OUT716
    DIRECTION OUTPUT ;
    USE SIGNAL ;
    PORT
      LAYER Metal2 ;
      RECT 2618.720 0.000 2619.080 0.500 ;
    END
  END OUT716
  PIN OUT717
    DIRECTION OUTPUT ;
    USE SIGNAL ;
    PORT
      LAYER Metal2 ;
      RECT 2622.220 0.000 2622.580 0.500 ;
    END
  END OUT717
  PIN OUT718
    DIRECTION OUTPUT ;
    USE SIGNAL ;
    PORT
      LAYER Metal2 ;
      RECT 2625.720 0.000 2626.080 0.500 ;
    END
  END OUT718
  PIN OUT719
    DIRECTION OUTPUT ;
    USE SIGNAL ;
    PORT
      LAYER Metal2 ;
      RECT 2629.220 0.000 2629.580 0.500 ;
    END
  END OUT719
  PIN OUT720
    DIRECTION OUTPUT ;
    USE SIGNAL ;
    PORT
      LAYER Metal2 ;
      RECT 2632.720 0.000 2633.080 0.500 ;
    END
  END OUT720
  PIN OUT721
    DIRECTION OUTPUT ;
    USE SIGNAL ;
    PORT
      LAYER Metal2 ;
      RECT 2636.220 0.000 2636.580 0.500 ;
    END
  END OUT721
  PIN OUT722
    DIRECTION OUTPUT ;
    USE SIGNAL ;
    PORT
      LAYER Metal2 ;
      RECT 2639.720 0.000 2640.080 0.500 ;
    END
  END OUT722
  PIN OUT723
    DIRECTION OUTPUT ;
    USE SIGNAL ;
    PORT
      LAYER Metal2 ;
      RECT 2643.220 0.000 2643.580 0.500 ;
    END
  END OUT723
  PIN OUT724
    DIRECTION OUTPUT ;
    USE SIGNAL ;
    PORT
      LAYER Metal2 ;
      RECT 2646.720 0.000 2647.080 0.500 ;
    END
  END OUT724
  PIN OUT725
    DIRECTION OUTPUT ;
    USE SIGNAL ;
    PORT
      LAYER Metal2 ;
      RECT 2650.220 0.000 2650.580 0.500 ;
    END
  END OUT725
  PIN OUT726
    DIRECTION OUTPUT ;
    USE SIGNAL ;
    PORT
      LAYER Metal2 ;
      RECT 2653.720 0.000 2654.080 0.500 ;
    END
  END OUT726
  PIN OUT727
    DIRECTION OUTPUT ;
    USE SIGNAL ;
    PORT
      LAYER Metal2 ;
      RECT 2657.220 0.000 2657.580 0.500 ;
    END
  END OUT727
  PIN OUT728
    DIRECTION OUTPUT ;
    USE SIGNAL ;
    PORT
      LAYER Metal2 ;
      RECT 2660.720 0.000 2661.080 0.500 ;
    END
  END OUT728
  PIN OUT729
    DIRECTION OUTPUT ;
    USE SIGNAL ;
    PORT
      LAYER Metal2 ;
      RECT 2664.220 0.000 2664.580 0.500 ;
    END
  END OUT729
  PIN OUT730
    DIRECTION OUTPUT ;
    USE SIGNAL ;
    PORT
      LAYER Metal2 ;
      RECT 2667.720 0.000 2668.080 0.500 ;
    END
  END OUT730
  PIN OUT731
    DIRECTION OUTPUT ;
    USE SIGNAL ;
    PORT
      LAYER Metal2 ;
      RECT 2671.220 0.000 2671.580 0.500 ;
    END
  END OUT731
  PIN OUT732
    DIRECTION OUTPUT ;
    USE SIGNAL ;
    PORT
      LAYER Metal2 ;
      RECT 2674.720 0.000 2675.080 0.500 ;
    END
  END OUT732
  PIN OUT733
    DIRECTION OUTPUT ;
    USE SIGNAL ;
    PORT
      LAYER Metal2 ;
      RECT 2678.220 0.000 2678.580 0.500 ;
    END
  END OUT733
  PIN OUT734
    DIRECTION OUTPUT ;
    USE SIGNAL ;
    PORT
      LAYER Metal2 ;
      RECT 2681.720 0.000 2682.080 0.500 ;
    END
  END OUT734
  PIN OUT735
    DIRECTION OUTPUT ;
    USE SIGNAL ;
    PORT
      LAYER Metal2 ;
      RECT 2685.220 0.000 2685.580 0.500 ;
    END
  END OUT735
  PIN OUT736
    DIRECTION OUTPUT ;
    USE SIGNAL ;
    PORT
      LAYER Metal2 ;
      RECT 2688.720 0.000 2689.080 0.500 ;
    END
  END OUT736
  PIN OUT737
    DIRECTION OUTPUT ;
    USE SIGNAL ;
    PORT
      LAYER Metal2 ;
      RECT 2692.220 0.000 2692.580 0.500 ;
    END
  END OUT737
  PIN OUT738
    DIRECTION OUTPUT ;
    USE SIGNAL ;
    PORT
      LAYER Metal2 ;
      RECT 2695.720 0.000 2696.080 0.500 ;
    END
  END OUT738
  PIN OUT739
    DIRECTION OUTPUT ;
    USE SIGNAL ;
    PORT
      LAYER Metal2 ;
      RECT 2699.220 0.000 2699.580 0.500 ;
    END
  END OUT739
  PIN OUT740
    DIRECTION OUTPUT ;
    USE SIGNAL ;
    PORT
      LAYER Metal2 ;
      RECT 2702.720 0.000 2703.080 0.500 ;
    END
  END OUT740
  PIN OUT741
    DIRECTION OUTPUT ;
    USE SIGNAL ;
    PORT
      LAYER Metal2 ;
      RECT 2706.220 0.000 2706.580 0.500 ;
    END
  END OUT741
  PIN OUT742
    DIRECTION OUTPUT ;
    USE SIGNAL ;
    PORT
      LAYER Metal2 ;
      RECT 2709.720 0.000 2710.080 0.500 ;
    END
  END OUT742
  PIN OUT743
    DIRECTION OUTPUT ;
    USE SIGNAL ;
    PORT
      LAYER Metal2 ;
      RECT 2713.220 0.000 2713.580 0.500 ;
    END
  END OUT743
  PIN OUT744
    DIRECTION OUTPUT ;
    USE SIGNAL ;
    PORT
      LAYER Metal2 ;
      RECT 2716.720 0.000 2717.080 0.500 ;
    END
  END OUT744
  PIN OUT745
    DIRECTION OUTPUT ;
    USE SIGNAL ;
    PORT
      LAYER Metal2 ;
      RECT 2720.220 0.000 2720.580 0.500 ;
    END
  END OUT745
  PIN OUT746
    DIRECTION OUTPUT ;
    USE SIGNAL ;
    PORT
      LAYER Metal2 ;
      RECT 2723.720 0.000 2724.080 0.500 ;
    END
  END OUT746
  PIN OUT747
    DIRECTION OUTPUT ;
    USE SIGNAL ;
    PORT
      LAYER Metal2 ;
      RECT 2727.220 0.000 2727.580 0.500 ;
    END
  END OUT747
  PIN OUT748
    DIRECTION OUTPUT ;
    USE SIGNAL ;
    PORT
      LAYER Metal2 ;
      RECT 2730.720 0.000 2731.080 0.500 ;
    END
  END OUT748
  PIN OUT749
    DIRECTION OUTPUT ;
    USE SIGNAL ;
    PORT
      LAYER Metal2 ;
      RECT 2734.220 0.000 2734.580 0.500 ;
    END
  END OUT749
  PIN OUT750
    DIRECTION OUTPUT ;
    USE SIGNAL ;
    PORT
      LAYER Metal2 ;
      RECT 2737.720 0.000 2738.080 0.500 ;
    END
  END OUT750
  PIN OUT751
    DIRECTION OUTPUT ;
    USE SIGNAL ;
    PORT
      LAYER Metal2 ;
      RECT 2741.220 0.000 2741.580 0.500 ;
    END
  END OUT751
  PIN OUT752
    DIRECTION OUTPUT ;
    USE SIGNAL ;
    PORT
      LAYER Metal2 ;
      RECT 2744.720 0.000 2745.080 0.500 ;
    END
  END OUT752
  PIN OUT753
    DIRECTION OUTPUT ;
    USE SIGNAL ;
    PORT
      LAYER Metal2 ;
      RECT 2748.220 0.000 2748.580 0.500 ;
    END
  END OUT753
  PIN OUT754
    DIRECTION OUTPUT ;
    USE SIGNAL ;
    PORT
      LAYER Metal2 ;
      RECT 2751.720 0.000 2752.080 0.500 ;
    END
  END OUT754
  PIN OUT755
    DIRECTION OUTPUT ;
    USE SIGNAL ;
    PORT
      LAYER Metal2 ;
      RECT 2755.220 0.000 2755.580 0.500 ;
    END
  END OUT755
  PIN OUT756
    DIRECTION OUTPUT ;
    USE SIGNAL ;
    PORT
      LAYER Metal2 ;
      RECT 2758.720 0.000 2759.080 0.500 ;
    END
  END OUT756
  PIN OUT757
    DIRECTION OUTPUT ;
    USE SIGNAL ;
    PORT
      LAYER Metal2 ;
      RECT 2762.220 0.000 2762.580 0.500 ;
    END
  END OUT757
  PIN OUT758
    DIRECTION OUTPUT ;
    USE SIGNAL ;
    PORT
      LAYER Metal2 ;
      RECT 2765.720 0.000 2766.080 0.500 ;
    END
  END OUT758
  PIN OUT759
    DIRECTION OUTPUT ;
    USE SIGNAL ;
    PORT
      LAYER Metal2 ;
      RECT 2769.220 0.000 2769.580 0.500 ;
    END
  END OUT759
  PIN OUT760
    DIRECTION OUTPUT ;
    USE SIGNAL ;
    PORT
      LAYER Metal2 ;
      RECT 2772.720 0.000 2773.080 0.500 ;
    END
  END OUT760
  PIN OUT761
    DIRECTION OUTPUT ;
    USE SIGNAL ;
    PORT
      LAYER Metal2 ;
      RECT 2776.220 0.000 2776.580 0.500 ;
    END
  END OUT761
  PIN OUT762
    DIRECTION OUTPUT ;
    USE SIGNAL ;
    PORT
      LAYER Metal2 ;
      RECT 2779.720 0.000 2780.080 0.500 ;
    END
  END OUT762
  PIN OUT763
    DIRECTION OUTPUT ;
    USE SIGNAL ;
    PORT
      LAYER Metal2 ;
      RECT 2783.220 0.000 2783.580 0.500 ;
    END
  END OUT763
  PIN OUT764
    DIRECTION OUTPUT ;
    USE SIGNAL ;
    PORT
      LAYER Metal2 ;
      RECT 2786.720 0.000 2787.080 0.500 ;
    END
  END OUT764
  PIN OUT765
    DIRECTION OUTPUT ;
    USE SIGNAL ;
    PORT
      LAYER Metal2 ;
      RECT 2790.220 0.000 2790.580 0.500 ;
    END
  END OUT765
  PIN OUT766
    DIRECTION OUTPUT ;
    USE SIGNAL ;
    PORT
      LAYER Metal2 ;
      RECT 2793.720 0.000 2794.080 0.500 ;
    END
  END OUT766
  PIN OUT767
    DIRECTION OUTPUT ;
    USE SIGNAL ;
    PORT
      LAYER Metal2 ;
      RECT 2797.220 0.000 2797.580 0.500 ;
    END
  END OUT767
  PIN OUT768
    DIRECTION OUTPUT ;
    USE SIGNAL ;
    PORT
      LAYER Metal2 ;
      RECT 2820.720 0.000 2821.080 0.500 ;
    END
  END OUT768
  PIN OUT769
    DIRECTION OUTPUT ;
    USE SIGNAL ;
    PORT
      LAYER Metal2 ;
      RECT 2824.220 0.000 2824.580 0.500 ;
    END
  END OUT769
  PIN OUT770
    DIRECTION OUTPUT ;
    USE SIGNAL ;
    PORT
      LAYER Metal2 ;
      RECT 2827.720 0.000 2828.080 0.500 ;
    END
  END OUT770
  PIN OUT771
    DIRECTION OUTPUT ;
    USE SIGNAL ;
    PORT
      LAYER Metal2 ;
      RECT 2831.220 0.000 2831.580 0.500 ;
    END
  END OUT771
  PIN OUT772
    DIRECTION OUTPUT ;
    USE SIGNAL ;
    PORT
      LAYER Metal2 ;
      RECT 2834.720 0.000 2835.080 0.500 ;
    END
  END OUT772
  PIN OUT773
    DIRECTION OUTPUT ;
    USE SIGNAL ;
    PORT
      LAYER Metal2 ;
      RECT 2838.220 0.000 2838.580 0.500 ;
    END
  END OUT773
  PIN OUT774
    DIRECTION OUTPUT ;
    USE SIGNAL ;
    PORT
      LAYER Metal2 ;
      RECT 2841.720 0.000 2842.080 0.500 ;
    END
  END OUT774
  PIN OUT775
    DIRECTION OUTPUT ;
    USE SIGNAL ;
    PORT
      LAYER Metal2 ;
      RECT 2845.220 0.000 2845.580 0.500 ;
    END
  END OUT775
  PIN OUT776
    DIRECTION OUTPUT ;
    USE SIGNAL ;
    PORT
      LAYER Metal2 ;
      RECT 2848.720 0.000 2849.080 0.500 ;
    END
  END OUT776
  PIN OUT777
    DIRECTION OUTPUT ;
    USE SIGNAL ;
    PORT
      LAYER Metal2 ;
      RECT 2852.220 0.000 2852.580 0.500 ;
    END
  END OUT777
  PIN OUT778
    DIRECTION OUTPUT ;
    USE SIGNAL ;
    PORT
      LAYER Metal2 ;
      RECT 2855.720 0.000 2856.080 0.500 ;
    END
  END OUT778
  PIN OUT779
    DIRECTION OUTPUT ;
    USE SIGNAL ;
    PORT
      LAYER Metal2 ;
      RECT 2859.220 0.000 2859.580 0.500 ;
    END
  END OUT779
  PIN OUT780
    DIRECTION OUTPUT ;
    USE SIGNAL ;
    PORT
      LAYER Metal2 ;
      RECT 2862.720 0.000 2863.080 0.500 ;
    END
  END OUT780
  PIN OUT781
    DIRECTION OUTPUT ;
    USE SIGNAL ;
    PORT
      LAYER Metal2 ;
      RECT 2866.220 0.000 2866.580 0.500 ;
    END
  END OUT781
  PIN OUT782
    DIRECTION OUTPUT ;
    USE SIGNAL ;
    PORT
      LAYER Metal2 ;
      RECT 2869.720 0.000 2870.080 0.500 ;
    END
  END OUT782
  PIN OUT783
    DIRECTION OUTPUT ;
    USE SIGNAL ;
    PORT
      LAYER Metal2 ;
      RECT 2873.220 0.000 2873.580 0.500 ;
    END
  END OUT783
  PIN OUT784
    DIRECTION OUTPUT ;
    USE SIGNAL ;
    PORT
      LAYER Metal2 ;
      RECT 2876.720 0.000 2877.080 0.500 ;
    END
  END OUT784
  PIN OUT785
    DIRECTION OUTPUT ;
    USE SIGNAL ;
    PORT
      LAYER Metal2 ;
      RECT 2880.220 0.000 2880.580 0.500 ;
    END
  END OUT785
  PIN OUT786
    DIRECTION OUTPUT ;
    USE SIGNAL ;
    PORT
      LAYER Metal2 ;
      RECT 2883.720 0.000 2884.080 0.500 ;
    END
  END OUT786
  PIN OUT787
    DIRECTION OUTPUT ;
    USE SIGNAL ;
    PORT
      LAYER Metal2 ;
      RECT 2887.220 0.000 2887.580 0.500 ;
    END
  END OUT787
  PIN OUT788
    DIRECTION OUTPUT ;
    USE SIGNAL ;
    PORT
      LAYER Metal2 ;
      RECT 2890.720 0.000 2891.080 0.500 ;
    END
  END OUT788
  PIN OUT789
    DIRECTION OUTPUT ;
    USE SIGNAL ;
    PORT
      LAYER Metal2 ;
      RECT 2894.220 0.000 2894.580 0.500 ;
    END
  END OUT789
  PIN OUT790
    DIRECTION OUTPUT ;
    USE SIGNAL ;
    PORT
      LAYER Metal2 ;
      RECT 2897.720 0.000 2898.080 0.500 ;
    END
  END OUT790
  PIN OUT791
    DIRECTION OUTPUT ;
    USE SIGNAL ;
    PORT
      LAYER Metal2 ;
      RECT 2901.220 0.000 2901.580 0.500 ;
    END
  END OUT791
  PIN OUT792
    DIRECTION OUTPUT ;
    USE SIGNAL ;
    PORT
      LAYER Metal2 ;
      RECT 2904.720 0.000 2905.080 0.500 ;
    END
  END OUT792
  PIN OUT793
    DIRECTION OUTPUT ;
    USE SIGNAL ;
    PORT
      LAYER Metal2 ;
      RECT 2908.220 0.000 2908.580 0.500 ;
    END
  END OUT793
  PIN OUT794
    DIRECTION OUTPUT ;
    USE SIGNAL ;
    PORT
      LAYER Metal2 ;
      RECT 2911.720 0.000 2912.080 0.500 ;
    END
  END OUT794
  PIN OUT795
    DIRECTION OUTPUT ;
    USE SIGNAL ;
    PORT
      LAYER Metal2 ;
      RECT 2915.220 0.000 2915.580 0.500 ;
    END
  END OUT795
  PIN OUT796
    DIRECTION OUTPUT ;
    USE SIGNAL ;
    PORT
      LAYER Metal2 ;
      RECT 2918.720 0.000 2919.080 0.500 ;
    END
  END OUT796
  PIN OUT797
    DIRECTION OUTPUT ;
    USE SIGNAL ;
    PORT
      LAYER Metal2 ;
      RECT 2922.220 0.000 2922.580 0.500 ;
    END
  END OUT797
  PIN OUT798
    DIRECTION OUTPUT ;
    USE SIGNAL ;
    PORT
      LAYER Metal2 ;
      RECT 2925.720 0.000 2926.080 0.500 ;
    END
  END OUT798
  PIN OUT799
    DIRECTION OUTPUT ;
    USE SIGNAL ;
    PORT
      LAYER Metal2 ;
      RECT 2929.220 0.000 2929.580 0.500 ;
    END
  END OUT799
  PIN OUT800
    DIRECTION OUTPUT ;
    USE SIGNAL ;
    PORT
      LAYER Metal2 ;
      RECT 2932.720 0.000 2933.080 0.500 ;
    END
  END OUT800
  PIN OUT801
    DIRECTION OUTPUT ;
    USE SIGNAL ;
    PORT
      LAYER Metal2 ;
      RECT 2936.220 0.000 2936.580 0.500 ;
    END
  END OUT801
  PIN OUT802
    DIRECTION OUTPUT ;
    USE SIGNAL ;
    PORT
      LAYER Metal2 ;
      RECT 2939.720 0.000 2940.080 0.500 ;
    END
  END OUT802
  PIN OUT803
    DIRECTION OUTPUT ;
    USE SIGNAL ;
    PORT
      LAYER Metal2 ;
      RECT 2943.220 0.000 2943.580 0.500 ;
    END
  END OUT803
  PIN OUT804
    DIRECTION OUTPUT ;
    USE SIGNAL ;
    PORT
      LAYER Metal2 ;
      RECT 2946.720 0.000 2947.080 0.500 ;
    END
  END OUT804
  PIN OUT805
    DIRECTION OUTPUT ;
    USE SIGNAL ;
    PORT
      LAYER Metal2 ;
      RECT 2950.220 0.000 2950.580 0.500 ;
    END
  END OUT805
  PIN OUT806
    DIRECTION OUTPUT ;
    USE SIGNAL ;
    PORT
      LAYER Metal2 ;
      RECT 2953.720 0.000 2954.080 0.500 ;
    END
  END OUT806
  PIN OUT807
    DIRECTION OUTPUT ;
    USE SIGNAL ;
    PORT
      LAYER Metal2 ;
      RECT 2957.220 0.000 2957.580 0.500 ;
    END
  END OUT807
  PIN OUT808
    DIRECTION OUTPUT ;
    USE SIGNAL ;
    PORT
      LAYER Metal2 ;
      RECT 2960.720 0.000 2961.080 0.500 ;
    END
  END OUT808
  PIN OUT809
    DIRECTION OUTPUT ;
    USE SIGNAL ;
    PORT
      LAYER Metal2 ;
      RECT 2964.220 0.000 2964.580 0.500 ;
    END
  END OUT809
  PIN OUT810
    DIRECTION OUTPUT ;
    USE SIGNAL ;
    PORT
      LAYER Metal2 ;
      RECT 2967.720 0.000 2968.080 0.500 ;
    END
  END OUT810
  PIN OUT811
    DIRECTION OUTPUT ;
    USE SIGNAL ;
    PORT
      LAYER Metal2 ;
      RECT 2971.220 0.000 2971.580 0.500 ;
    END
  END OUT811
  PIN OUT812
    DIRECTION OUTPUT ;
    USE SIGNAL ;
    PORT
      LAYER Metal2 ;
      RECT 2974.720 0.000 2975.080 0.500 ;
    END
  END OUT812
  PIN OUT813
    DIRECTION OUTPUT ;
    USE SIGNAL ;
    PORT
      LAYER Metal2 ;
      RECT 2978.220 0.000 2978.580 0.500 ;
    END
  END OUT813
  PIN OUT814
    DIRECTION OUTPUT ;
    USE SIGNAL ;
    PORT
      LAYER Metal2 ;
      RECT 2981.720 0.000 2982.080 0.500 ;
    END
  END OUT814
  PIN OUT815
    DIRECTION OUTPUT ;
    USE SIGNAL ;
    PORT
      LAYER Metal2 ;
      RECT 2985.220 0.000 2985.580 0.500 ;
    END
  END OUT815
  PIN OUT816
    DIRECTION OUTPUT ;
    USE SIGNAL ;
    PORT
      LAYER Metal2 ;
      RECT 2988.720 0.000 2989.080 0.500 ;
    END
  END OUT816
  PIN OUT817
    DIRECTION OUTPUT ;
    USE SIGNAL ;
    PORT
      LAYER Metal2 ;
      RECT 2992.220 0.000 2992.580 0.500 ;
    END
  END OUT817
  PIN OUT818
    DIRECTION OUTPUT ;
    USE SIGNAL ;
    PORT
      LAYER Metal2 ;
      RECT 2995.720 0.000 2996.080 0.500 ;
    END
  END OUT818
  PIN OUT819
    DIRECTION OUTPUT ;
    USE SIGNAL ;
    PORT
      LAYER Metal2 ;
      RECT 2999.220 0.000 2999.580 0.500 ;
    END
  END OUT819
  PIN OUT820
    DIRECTION OUTPUT ;
    USE SIGNAL ;
    PORT
      LAYER Metal2 ;
      RECT 3002.720 0.000 3003.080 0.500 ;
    END
  END OUT820
  PIN OUT821
    DIRECTION OUTPUT ;
    USE SIGNAL ;
    PORT
      LAYER Metal2 ;
      RECT 3006.220 0.000 3006.580 0.500 ;
    END
  END OUT821
  PIN OUT822
    DIRECTION OUTPUT ;
    USE SIGNAL ;
    PORT
      LAYER Metal2 ;
      RECT 3009.720 0.000 3010.080 0.500 ;
    END
  END OUT822
  PIN OUT823
    DIRECTION OUTPUT ;
    USE SIGNAL ;
    PORT
      LAYER Metal2 ;
      RECT 3013.220 0.000 3013.580 0.500 ;
    END
  END OUT823
  PIN OUT824
    DIRECTION OUTPUT ;
    USE SIGNAL ;
    PORT
      LAYER Metal2 ;
      RECT 3016.720 0.000 3017.080 0.500 ;
    END
  END OUT824
  PIN OUT825
    DIRECTION OUTPUT ;
    USE SIGNAL ;
    PORT
      LAYER Metal2 ;
      RECT 3020.220 0.000 3020.580 0.500 ;
    END
  END OUT825
  PIN OUT826
    DIRECTION OUTPUT ;
    USE SIGNAL ;
    PORT
      LAYER Metal2 ;
      RECT 3023.720 0.000 3024.080 0.500 ;
    END
  END OUT826
  PIN OUT827
    DIRECTION OUTPUT ;
    USE SIGNAL ;
    PORT
      LAYER Metal2 ;
      RECT 3027.220 0.000 3027.580 0.500 ;
    END
  END OUT827
  PIN OUT828
    DIRECTION OUTPUT ;
    USE SIGNAL ;
    PORT
      LAYER Metal2 ;
      RECT 3030.720 0.000 3031.080 0.500 ;
    END
  END OUT828
  PIN OUT829
    DIRECTION OUTPUT ;
    USE SIGNAL ;
    PORT
      LAYER Metal2 ;
      RECT 3034.220 0.000 3034.580 0.500 ;
    END
  END OUT829
  PIN OUT830
    DIRECTION OUTPUT ;
    USE SIGNAL ;
    PORT
      LAYER Metal2 ;
      RECT 3037.720 0.000 3038.080 0.500 ;
    END
  END OUT830
  PIN OUT831
    DIRECTION OUTPUT ;
    USE SIGNAL ;
    PORT
      LAYER Metal2 ;
      RECT 3041.220 0.000 3041.580 0.500 ;
    END
  END OUT831
  PIN OUT832
    DIRECTION OUTPUT ;
    USE SIGNAL ;
    PORT
      LAYER Metal2 ;
      RECT 3044.720 0.000 3045.080 0.500 ;
    END
  END OUT832
  PIN OUT833
    DIRECTION OUTPUT ;
    USE SIGNAL ;
    PORT
      LAYER Metal2 ;
      RECT 3048.220 0.000 3048.580 0.500 ;
    END
  END OUT833
  PIN OUT834
    DIRECTION OUTPUT ;
    USE SIGNAL ;
    PORT
      LAYER Metal2 ;
      RECT 3051.720 0.000 3052.080 0.500 ;
    END
  END OUT834
  PIN OUT835
    DIRECTION OUTPUT ;
    USE SIGNAL ;
    PORT
      LAYER Metal2 ;
      RECT 3055.220 0.000 3055.580 0.500 ;
    END
  END OUT835
  PIN OUT836
    DIRECTION OUTPUT ;
    USE SIGNAL ;
    PORT
      LAYER Metal2 ;
      RECT 3058.720 0.000 3059.080 0.500 ;
    END
  END OUT836
  PIN OUT837
    DIRECTION OUTPUT ;
    USE SIGNAL ;
    PORT
      LAYER Metal2 ;
      RECT 3062.220 0.000 3062.580 0.500 ;
    END
  END OUT837
  PIN OUT838
    DIRECTION OUTPUT ;
    USE SIGNAL ;
    PORT
      LAYER Metal2 ;
      RECT 3065.720 0.000 3066.080 0.500 ;
    END
  END OUT838
  PIN OUT839
    DIRECTION OUTPUT ;
    USE SIGNAL ;
    PORT
      LAYER Metal2 ;
      RECT 3069.220 0.000 3069.580 0.500 ;
    END
  END OUT839
  PIN OUT840
    DIRECTION OUTPUT ;
    USE SIGNAL ;
    PORT
      LAYER Metal2 ;
      RECT 3072.720 0.000 3073.080 0.500 ;
    END
  END OUT840
  PIN OUT841
    DIRECTION OUTPUT ;
    USE SIGNAL ;
    PORT
      LAYER Metal2 ;
      RECT 3076.220 0.000 3076.580 0.500 ;
    END
  END OUT841
  PIN OUT842
    DIRECTION OUTPUT ;
    USE SIGNAL ;
    PORT
      LAYER Metal2 ;
      RECT 3079.720 0.000 3080.080 0.500 ;
    END
  END OUT842
  PIN OUT843
    DIRECTION OUTPUT ;
    USE SIGNAL ;
    PORT
      LAYER Metal2 ;
      RECT 3083.220 0.000 3083.580 0.500 ;
    END
  END OUT843
  PIN OUT844
    DIRECTION OUTPUT ;
    USE SIGNAL ;
    PORT
      LAYER Metal2 ;
      RECT 3086.720 0.000 3087.080 0.500 ;
    END
  END OUT844
  PIN OUT845
    DIRECTION OUTPUT ;
    USE SIGNAL ;
    PORT
      LAYER Metal2 ;
      RECT 3090.220 0.000 3090.580 0.500 ;
    END
  END OUT845
  PIN OUT846
    DIRECTION OUTPUT ;
    USE SIGNAL ;
    PORT
      LAYER Metal2 ;
      RECT 3093.720 0.000 3094.080 0.500 ;
    END
  END OUT846
  PIN OUT847
    DIRECTION OUTPUT ;
    USE SIGNAL ;
    PORT
      LAYER Metal2 ;
      RECT 3097.220 0.000 3097.580 0.500 ;
    END
  END OUT847
  PIN OUT848
    DIRECTION OUTPUT ;
    USE SIGNAL ;
    PORT
      LAYER Metal2 ;
      RECT 3100.720 0.000 3101.080 0.500 ;
    END
  END OUT848
  PIN OUT849
    DIRECTION OUTPUT ;
    USE SIGNAL ;
    PORT
      LAYER Metal2 ;
      RECT 3104.220 0.000 3104.580 0.500 ;
    END
  END OUT849
  PIN OUT850
    DIRECTION OUTPUT ;
    USE SIGNAL ;
    PORT
      LAYER Metal2 ;
      RECT 3107.720 0.000 3108.080 0.500 ;
    END
  END OUT850
  PIN OUT851
    DIRECTION OUTPUT ;
    USE SIGNAL ;
    PORT
      LAYER Metal2 ;
      RECT 3111.220 0.000 3111.580 0.500 ;
    END
  END OUT851
  PIN OUT852
    DIRECTION OUTPUT ;
    USE SIGNAL ;
    PORT
      LAYER Metal2 ;
      RECT 3114.720 0.000 3115.080 0.500 ;
    END
  END OUT852
  PIN OUT853
    DIRECTION OUTPUT ;
    USE SIGNAL ;
    PORT
      LAYER Metal2 ;
      RECT 3118.220 0.000 3118.580 0.500 ;
    END
  END OUT853
  PIN OUT854
    DIRECTION OUTPUT ;
    USE SIGNAL ;
    PORT
      LAYER Metal2 ;
      RECT 3121.720 0.000 3122.080 0.500 ;
    END
  END OUT854
  PIN OUT855
    DIRECTION OUTPUT ;
    USE SIGNAL ;
    PORT
      LAYER Metal2 ;
      RECT 3125.220 0.000 3125.580 0.500 ;
    END
  END OUT855
  PIN OUT856
    DIRECTION OUTPUT ;
    USE SIGNAL ;
    PORT
      LAYER Metal2 ;
      RECT 3128.720 0.000 3129.080 0.500 ;
    END
  END OUT856
  PIN OUT857
    DIRECTION OUTPUT ;
    USE SIGNAL ;
    PORT
      LAYER Metal2 ;
      RECT 3132.220 0.000 3132.580 0.500 ;
    END
  END OUT857
  PIN OUT858
    DIRECTION OUTPUT ;
    USE SIGNAL ;
    PORT
      LAYER Metal2 ;
      RECT 3135.720 0.000 3136.080 0.500 ;
    END
  END OUT858
  PIN OUT859
    DIRECTION OUTPUT ;
    USE SIGNAL ;
    PORT
      LAYER Metal2 ;
      RECT 3139.220 0.000 3139.580 0.500 ;
    END
  END OUT859
  PIN OUT860
    DIRECTION OUTPUT ;
    USE SIGNAL ;
    PORT
      LAYER Metal2 ;
      RECT 3142.720 0.000 3143.080 0.500 ;
    END
  END OUT860
  PIN OUT861
    DIRECTION OUTPUT ;
    USE SIGNAL ;
    PORT
      LAYER Metal2 ;
      RECT 3146.220 0.000 3146.580 0.500 ;
    END
  END OUT861
  PIN OUT862
    DIRECTION OUTPUT ;
    USE SIGNAL ;
    PORT
      LAYER Metal2 ;
      RECT 3149.720 0.000 3150.080 0.500 ;
    END
  END OUT862
  PIN OUT863
    DIRECTION OUTPUT ;
    USE SIGNAL ;
    PORT
      LAYER Metal2 ;
      RECT 3153.220 0.000 3153.580 0.500 ;
    END
  END OUT863
  PIN OUT864
    DIRECTION OUTPUT ;
    USE SIGNAL ;
    PORT
      LAYER Metal2 ;
      RECT 3156.720 0.000 3157.080 0.500 ;
    END
  END OUT864
  PIN OUT865
    DIRECTION OUTPUT ;
    USE SIGNAL ;
    PORT
      LAYER Metal2 ;
      RECT 3160.220 0.000 3160.580 0.500 ;
    END
  END OUT865
  PIN OUT866
    DIRECTION OUTPUT ;
    USE SIGNAL ;
    PORT
      LAYER Metal2 ;
      RECT 3163.720 0.000 3164.080 0.500 ;
    END
  END OUT866
  PIN OUT867
    DIRECTION OUTPUT ;
    USE SIGNAL ;
    PORT
      LAYER Metal2 ;
      RECT 3167.220 0.000 3167.580 0.500 ;
    END
  END OUT867
  PIN OUT868
    DIRECTION OUTPUT ;
    USE SIGNAL ;
    PORT
      LAYER Metal2 ;
      RECT 3170.720 0.000 3171.080 0.500 ;
    END
  END OUT868
  PIN OUT869
    DIRECTION OUTPUT ;
    USE SIGNAL ;
    PORT
      LAYER Metal2 ;
      RECT 3174.220 0.000 3174.580 0.500 ;
    END
  END OUT869
  PIN OUT870
    DIRECTION OUTPUT ;
    USE SIGNAL ;
    PORT
      LAYER Metal2 ;
      RECT 3177.720 0.000 3178.080 0.500 ;
    END
  END OUT870
  PIN OUT871
    DIRECTION OUTPUT ;
    USE SIGNAL ;
    PORT
      LAYER Metal2 ;
      RECT 3181.220 0.000 3181.580 0.500 ;
    END
  END OUT871
  PIN OUT872
    DIRECTION OUTPUT ;
    USE SIGNAL ;
    PORT
      LAYER Metal2 ;
      RECT 3184.720 0.000 3185.080 0.500 ;
    END
  END OUT872
  PIN OUT873
    DIRECTION OUTPUT ;
    USE SIGNAL ;
    PORT
      LAYER Metal2 ;
      RECT 3188.220 0.000 3188.580 0.500 ;
    END
  END OUT873
  PIN OUT874
    DIRECTION OUTPUT ;
    USE SIGNAL ;
    PORT
      LAYER Metal2 ;
      RECT 3191.720 0.000 3192.080 0.500 ;
    END
  END OUT874
  PIN OUT875
    DIRECTION OUTPUT ;
    USE SIGNAL ;
    PORT
      LAYER Metal2 ;
      RECT 3195.220 0.000 3195.580 0.500 ;
    END
  END OUT875
  PIN OUT876
    DIRECTION OUTPUT ;
    USE SIGNAL ;
    PORT
      LAYER Metal2 ;
      RECT 3198.720 0.000 3199.080 0.500 ;
    END
  END OUT876
  PIN OUT877
    DIRECTION OUTPUT ;
    USE SIGNAL ;
    PORT
      LAYER Metal2 ;
      RECT 3202.220 0.000 3202.580 0.500 ;
    END
  END OUT877
  PIN OUT878
    DIRECTION OUTPUT ;
    USE SIGNAL ;
    PORT
      LAYER Metal2 ;
      RECT 3205.720 0.000 3206.080 0.500 ;
    END
  END OUT878
  PIN OUT879
    DIRECTION OUTPUT ;
    USE SIGNAL ;
    PORT
      LAYER Metal2 ;
      RECT 3209.220 0.000 3209.580 0.500 ;
    END
  END OUT879
  PIN OUT880
    DIRECTION OUTPUT ;
    USE SIGNAL ;
    PORT
      LAYER Metal2 ;
      RECT 3212.720 0.000 3213.080 0.500 ;
    END
  END OUT880
  PIN OUT881
    DIRECTION OUTPUT ;
    USE SIGNAL ;
    PORT
      LAYER Metal2 ;
      RECT 3216.220 0.000 3216.580 0.500 ;
    END
  END OUT881
  PIN OUT882
    DIRECTION OUTPUT ;
    USE SIGNAL ;
    PORT
      LAYER Metal2 ;
      RECT 3219.720 0.000 3220.080 0.500 ;
    END
  END OUT882
  PIN OUT883
    DIRECTION OUTPUT ;
    USE SIGNAL ;
    PORT
      LAYER Metal2 ;
      RECT 3223.220 0.000 3223.580 0.500 ;
    END
  END OUT883
  PIN OUT884
    DIRECTION OUTPUT ;
    USE SIGNAL ;
    PORT
      LAYER Metal2 ;
      RECT 3226.720 0.000 3227.080 0.500 ;
    END
  END OUT884
  PIN OUT885
    DIRECTION OUTPUT ;
    USE SIGNAL ;
    PORT
      LAYER Metal2 ;
      RECT 3230.220 0.000 3230.580 0.500 ;
    END
  END OUT885
  PIN OUT886
    DIRECTION OUTPUT ;
    USE SIGNAL ;
    PORT
      LAYER Metal2 ;
      RECT 3233.720 0.000 3234.080 0.500 ;
    END
  END OUT886
  PIN OUT887
    DIRECTION OUTPUT ;
    USE SIGNAL ;
    PORT
      LAYER Metal2 ;
      RECT 3237.220 0.000 3237.580 0.500 ;
    END
  END OUT887
  PIN OUT888
    DIRECTION OUTPUT ;
    USE SIGNAL ;
    PORT
      LAYER Metal2 ;
      RECT 3240.720 0.000 3241.080 0.500 ;
    END
  END OUT888
  PIN OUT889
    DIRECTION OUTPUT ;
    USE SIGNAL ;
    PORT
      LAYER Metal2 ;
      RECT 3244.220 0.000 3244.580 0.500 ;
    END
  END OUT889
  PIN OUT890
    DIRECTION OUTPUT ;
    USE SIGNAL ;
    PORT
      LAYER Metal2 ;
      RECT 3247.720 0.000 3248.080 0.500 ;
    END
  END OUT890
  PIN OUT891
    DIRECTION OUTPUT ;
    USE SIGNAL ;
    PORT
      LAYER Metal2 ;
      RECT 3251.220 0.000 3251.580 0.500 ;
    END
  END OUT891
  PIN OUT892
    DIRECTION OUTPUT ;
    USE SIGNAL ;
    PORT
      LAYER Metal2 ;
      RECT 3254.720 0.000 3255.080 0.500 ;
    END
  END OUT892
  PIN OUT893
    DIRECTION OUTPUT ;
    USE SIGNAL ;
    PORT
      LAYER Metal2 ;
      RECT 3258.220 0.000 3258.580 0.500 ;
    END
  END OUT893
  PIN OUT894
    DIRECTION OUTPUT ;
    USE SIGNAL ;
    PORT
      LAYER Metal2 ;
      RECT 3261.720 0.000 3262.080 0.500 ;
    END
  END OUT894
  PIN OUT895
    DIRECTION OUTPUT ;
    USE SIGNAL ;
    PORT
      LAYER Metal2 ;
      RECT 3265.220 0.000 3265.580 0.500 ;
    END
  END OUT895
  PIN OUT896
    DIRECTION OUTPUT ;
    USE SIGNAL ;
    PORT
      LAYER Metal2 ;
      RECT 3288.720 0.000 3289.080 0.500 ;
    END
  END OUT896
  PIN OUT897
    DIRECTION OUTPUT ;
    USE SIGNAL ;
    PORT
      LAYER Metal2 ;
      RECT 3292.220 0.000 3292.580 0.500 ;
    END
  END OUT897
  PIN OUT898
    DIRECTION OUTPUT ;
    USE SIGNAL ;
    PORT
      LAYER Metal2 ;
      RECT 3295.720 0.000 3296.080 0.500 ;
    END
  END OUT898
  PIN OUT899
    DIRECTION OUTPUT ;
    USE SIGNAL ;
    PORT
      LAYER Metal2 ;
      RECT 3299.220 0.000 3299.580 0.500 ;
    END
  END OUT899
  PIN OUT900
    DIRECTION OUTPUT ;
    USE SIGNAL ;
    PORT
      LAYER Metal2 ;
      RECT 3302.720 0.000 3303.080 0.500 ;
    END
  END OUT900
  PIN OUT901
    DIRECTION OUTPUT ;
    USE SIGNAL ;
    PORT
      LAYER Metal2 ;
      RECT 3306.220 0.000 3306.580 0.500 ;
    END
  END OUT901
  PIN OUT902
    DIRECTION OUTPUT ;
    USE SIGNAL ;
    PORT
      LAYER Metal2 ;
      RECT 3309.720 0.000 3310.080 0.500 ;
    END
  END OUT902
  PIN OUT903
    DIRECTION OUTPUT ;
    USE SIGNAL ;
    PORT
      LAYER Metal2 ;
      RECT 3313.220 0.000 3313.580 0.500 ;
    END
  END OUT903
  PIN OUT904
    DIRECTION OUTPUT ;
    USE SIGNAL ;
    PORT
      LAYER Metal2 ;
      RECT 3316.720 0.000 3317.080 0.500 ;
    END
  END OUT904
  PIN OUT905
    DIRECTION OUTPUT ;
    USE SIGNAL ;
    PORT
      LAYER Metal2 ;
      RECT 3320.220 0.000 3320.580 0.500 ;
    END
  END OUT905
  PIN OUT906
    DIRECTION OUTPUT ;
    USE SIGNAL ;
    PORT
      LAYER Metal2 ;
      RECT 3323.720 0.000 3324.080 0.500 ;
    END
  END OUT906
  PIN OUT907
    DIRECTION OUTPUT ;
    USE SIGNAL ;
    PORT
      LAYER Metal2 ;
      RECT 3327.220 0.000 3327.580 0.500 ;
    END
  END OUT907
  PIN OUT908
    DIRECTION OUTPUT ;
    USE SIGNAL ;
    PORT
      LAYER Metal2 ;
      RECT 3330.720 0.000 3331.080 0.500 ;
    END
  END OUT908
  PIN OUT909
    DIRECTION OUTPUT ;
    USE SIGNAL ;
    PORT
      LAYER Metal2 ;
      RECT 3334.220 0.000 3334.580 0.500 ;
    END
  END OUT909
  PIN OUT910
    DIRECTION OUTPUT ;
    USE SIGNAL ;
    PORT
      LAYER Metal2 ;
      RECT 3337.720 0.000 3338.080 0.500 ;
    END
  END OUT910
  PIN OUT911
    DIRECTION OUTPUT ;
    USE SIGNAL ;
    PORT
      LAYER Metal2 ;
      RECT 3341.220 0.000 3341.580 0.500 ;
    END
  END OUT911
  PIN OUT912
    DIRECTION OUTPUT ;
    USE SIGNAL ;
    PORT
      LAYER Metal2 ;
      RECT 3344.720 0.000 3345.080 0.500 ;
    END
  END OUT912
  PIN OUT913
    DIRECTION OUTPUT ;
    USE SIGNAL ;
    PORT
      LAYER Metal2 ;
      RECT 3348.220 0.000 3348.580 0.500 ;
    END
  END OUT913
  PIN OUT914
    DIRECTION OUTPUT ;
    USE SIGNAL ;
    PORT
      LAYER Metal2 ;
      RECT 3351.720 0.000 3352.080 0.500 ;
    END
  END OUT914
  PIN OUT915
    DIRECTION OUTPUT ;
    USE SIGNAL ;
    PORT
      LAYER Metal2 ;
      RECT 3355.220 0.000 3355.580 0.500 ;
    END
  END OUT915
  PIN OUT916
    DIRECTION OUTPUT ;
    USE SIGNAL ;
    PORT
      LAYER Metal2 ;
      RECT 3358.720 0.000 3359.080 0.500 ;
    END
  END OUT916
  PIN OUT917
    DIRECTION OUTPUT ;
    USE SIGNAL ;
    PORT
      LAYER Metal2 ;
      RECT 3362.220 0.000 3362.580 0.500 ;
    END
  END OUT917
  PIN OUT918
    DIRECTION OUTPUT ;
    USE SIGNAL ;
    PORT
      LAYER Metal2 ;
      RECT 3365.720 0.000 3366.080 0.500 ;
    END
  END OUT918
  PIN OUT919
    DIRECTION OUTPUT ;
    USE SIGNAL ;
    PORT
      LAYER Metal2 ;
      RECT 3369.220 0.000 3369.580 0.500 ;
    END
  END OUT919
  PIN OUT920
    DIRECTION OUTPUT ;
    USE SIGNAL ;
    PORT
      LAYER Metal2 ;
      RECT 3372.720 0.000 3373.080 0.500 ;
    END
  END OUT920
  PIN OUT921
    DIRECTION OUTPUT ;
    USE SIGNAL ;
    PORT
      LAYER Metal2 ;
      RECT 3376.220 0.000 3376.580 0.500 ;
    END
  END OUT921
  PIN OUT922
    DIRECTION OUTPUT ;
    USE SIGNAL ;
    PORT
      LAYER Metal2 ;
      RECT 3379.720 0.000 3380.080 0.500 ;
    END
  END OUT922
  PIN OUT923
    DIRECTION OUTPUT ;
    USE SIGNAL ;
    PORT
      LAYER Metal2 ;
      RECT 3383.220 0.000 3383.580 0.500 ;
    END
  END OUT923
  PIN OUT924
    DIRECTION OUTPUT ;
    USE SIGNAL ;
    PORT
      LAYER Metal2 ;
      RECT 3386.720 0.000 3387.080 0.500 ;
    END
  END OUT924
  PIN OUT925
    DIRECTION OUTPUT ;
    USE SIGNAL ;
    PORT
      LAYER Metal2 ;
      RECT 3390.220 0.000 3390.580 0.500 ;
    END
  END OUT925
  PIN OUT926
    DIRECTION OUTPUT ;
    USE SIGNAL ;
    PORT
      LAYER Metal2 ;
      RECT 3393.720 0.000 3394.080 0.500 ;
    END
  END OUT926
  PIN OUT927
    DIRECTION OUTPUT ;
    USE SIGNAL ;
    PORT
      LAYER Metal2 ;
      RECT 3397.220 0.000 3397.580 0.500 ;
    END
  END OUT927
  PIN OUT928
    DIRECTION OUTPUT ;
    USE SIGNAL ;
    PORT
      LAYER Metal2 ;
      RECT 3400.720 0.000 3401.080 0.500 ;
    END
  END OUT928
  PIN OUT929
    DIRECTION OUTPUT ;
    USE SIGNAL ;
    PORT
      LAYER Metal2 ;
      RECT 3404.220 0.000 3404.580 0.500 ;
    END
  END OUT929
  PIN OUT930
    DIRECTION OUTPUT ;
    USE SIGNAL ;
    PORT
      LAYER Metal2 ;
      RECT 3407.720 0.000 3408.080 0.500 ;
    END
  END OUT930
  PIN OUT931
    DIRECTION OUTPUT ;
    USE SIGNAL ;
    PORT
      LAYER Metal2 ;
      RECT 3411.220 0.000 3411.580 0.500 ;
    END
  END OUT931
  PIN OUT932
    DIRECTION OUTPUT ;
    USE SIGNAL ;
    PORT
      LAYER Metal2 ;
      RECT 3414.720 0.000 3415.080 0.500 ;
    END
  END OUT932
  PIN OUT933
    DIRECTION OUTPUT ;
    USE SIGNAL ;
    PORT
      LAYER Metal2 ;
      RECT 3418.220 0.000 3418.580 0.500 ;
    END
  END OUT933
  PIN OUT934
    DIRECTION OUTPUT ;
    USE SIGNAL ;
    PORT
      LAYER Metal2 ;
      RECT 3421.720 0.000 3422.080 0.500 ;
    END
  END OUT934
  PIN OUT935
    DIRECTION OUTPUT ;
    USE SIGNAL ;
    PORT
      LAYER Metal2 ;
      RECT 3425.220 0.000 3425.580 0.500 ;
    END
  END OUT935
  PIN OUT936
    DIRECTION OUTPUT ;
    USE SIGNAL ;
    PORT
      LAYER Metal2 ;
      RECT 3428.720 0.000 3429.080 0.500 ;
    END
  END OUT936
  PIN OUT937
    DIRECTION OUTPUT ;
    USE SIGNAL ;
    PORT
      LAYER Metal2 ;
      RECT 3432.220 0.000 3432.580 0.500 ;
    END
  END OUT937
  PIN OUT938
    DIRECTION OUTPUT ;
    USE SIGNAL ;
    PORT
      LAYER Metal2 ;
      RECT 3435.720 0.000 3436.080 0.500 ;
    END
  END OUT938
  PIN OUT939
    DIRECTION OUTPUT ;
    USE SIGNAL ;
    PORT
      LAYER Metal2 ;
      RECT 3439.220 0.000 3439.580 0.500 ;
    END
  END OUT939
  PIN OUT940
    DIRECTION OUTPUT ;
    USE SIGNAL ;
    PORT
      LAYER Metal2 ;
      RECT 3442.720 0.000 3443.080 0.500 ;
    END
  END OUT940
  PIN OUT941
    DIRECTION OUTPUT ;
    USE SIGNAL ;
    PORT
      LAYER Metal2 ;
      RECT 3446.220 0.000 3446.580 0.500 ;
    END
  END OUT941
  PIN OUT942
    DIRECTION OUTPUT ;
    USE SIGNAL ;
    PORT
      LAYER Metal2 ;
      RECT 3449.720 0.000 3450.080 0.500 ;
    END
  END OUT942
  PIN OUT943
    DIRECTION OUTPUT ;
    USE SIGNAL ;
    PORT
      LAYER Metal2 ;
      RECT 3453.220 0.000 3453.580 0.500 ;
    END
  END OUT943
  PIN OUT944
    DIRECTION OUTPUT ;
    USE SIGNAL ;
    PORT
      LAYER Metal2 ;
      RECT 3456.720 0.000 3457.080 0.500 ;
    END
  END OUT944
  PIN OUT945
    DIRECTION OUTPUT ;
    USE SIGNAL ;
    PORT
      LAYER Metal2 ;
      RECT 3460.220 0.000 3460.580 0.500 ;
    END
  END OUT945
  PIN OUT946
    DIRECTION OUTPUT ;
    USE SIGNAL ;
    PORT
      LAYER Metal2 ;
      RECT 3463.720 0.000 3464.080 0.500 ;
    END
  END OUT946
  PIN OUT947
    DIRECTION OUTPUT ;
    USE SIGNAL ;
    PORT
      LAYER Metal2 ;
      RECT 3467.220 0.000 3467.580 0.500 ;
    END
  END OUT947
  PIN OUT948
    DIRECTION OUTPUT ;
    USE SIGNAL ;
    PORT
      LAYER Metal2 ;
      RECT 3470.720 0.000 3471.080 0.500 ;
    END
  END OUT948
  PIN OUT949
    DIRECTION OUTPUT ;
    USE SIGNAL ;
    PORT
      LAYER Metal2 ;
      RECT 3474.220 0.000 3474.580 0.500 ;
    END
  END OUT949
  PIN OUT950
    DIRECTION OUTPUT ;
    USE SIGNAL ;
    PORT
      LAYER Metal2 ;
      RECT 3477.720 0.000 3478.080 0.500 ;
    END
  END OUT950
  PIN OUT951
    DIRECTION OUTPUT ;
    USE SIGNAL ;
    PORT
      LAYER Metal2 ;
      RECT 3481.220 0.000 3481.580 0.500 ;
    END
  END OUT951
  PIN OUT952
    DIRECTION OUTPUT ;
    USE SIGNAL ;
    PORT
      LAYER Metal2 ;
      RECT 3484.720 0.000 3485.080 0.500 ;
    END
  END OUT952
  PIN OUT953
    DIRECTION OUTPUT ;
    USE SIGNAL ;
    PORT
      LAYER Metal2 ;
      RECT 3488.220 0.000 3488.580 0.500 ;
    END
  END OUT953
  PIN OUT954
    DIRECTION OUTPUT ;
    USE SIGNAL ;
    PORT
      LAYER Metal2 ;
      RECT 3491.720 0.000 3492.080 0.500 ;
    END
  END OUT954
  PIN OUT955
    DIRECTION OUTPUT ;
    USE SIGNAL ;
    PORT
      LAYER Metal2 ;
      RECT 3495.220 0.000 3495.580 0.500 ;
    END
  END OUT955
  PIN OUT956
    DIRECTION OUTPUT ;
    USE SIGNAL ;
    PORT
      LAYER Metal2 ;
      RECT 3498.720 0.000 3499.080 0.500 ;
    END
  END OUT956
  PIN OUT957
    DIRECTION OUTPUT ;
    USE SIGNAL ;
    PORT
      LAYER Metal2 ;
      RECT 3502.220 0.000 3502.580 0.500 ;
    END
  END OUT957
  PIN OUT958
    DIRECTION OUTPUT ;
    USE SIGNAL ;
    PORT
      LAYER Metal2 ;
      RECT 3505.720 0.000 3506.080 0.500 ;
    END
  END OUT958
  PIN OUT959
    DIRECTION OUTPUT ;
    USE SIGNAL ;
    PORT
      LAYER Metal2 ;
      RECT 3509.220 0.000 3509.580 0.500 ;
    END
  END OUT959
  PIN OUT960
    DIRECTION OUTPUT ;
    USE SIGNAL ;
    PORT
      LAYER Metal2 ;
      RECT 3512.720 0.000 3513.080 0.500 ;
    END
  END OUT960
  PIN OUT961
    DIRECTION OUTPUT ;
    USE SIGNAL ;
    PORT
      LAYER Metal2 ;
      RECT 3516.220 0.000 3516.580 0.500 ;
    END
  END OUT961
  PIN OUT962
    DIRECTION OUTPUT ;
    USE SIGNAL ;
    PORT
      LAYER Metal2 ;
      RECT 3519.720 0.000 3520.080 0.500 ;
    END
  END OUT962
  PIN OUT963
    DIRECTION OUTPUT ;
    USE SIGNAL ;
    PORT
      LAYER Metal2 ;
      RECT 3523.220 0.000 3523.580 0.500 ;
    END
  END OUT963
  PIN OUT964
    DIRECTION OUTPUT ;
    USE SIGNAL ;
    PORT
      LAYER Metal2 ;
      RECT 3526.720 0.000 3527.080 0.500 ;
    END
  END OUT964
  PIN OUT965
    DIRECTION OUTPUT ;
    USE SIGNAL ;
    PORT
      LAYER Metal2 ;
      RECT 3530.220 0.000 3530.580 0.500 ;
    END
  END OUT965
  PIN OUT966
    DIRECTION OUTPUT ;
    USE SIGNAL ;
    PORT
      LAYER Metal2 ;
      RECT 3533.720 0.000 3534.080 0.500 ;
    END
  END OUT966
  PIN OUT967
    DIRECTION OUTPUT ;
    USE SIGNAL ;
    PORT
      LAYER Metal2 ;
      RECT 3537.220 0.000 3537.580 0.500 ;
    END
  END OUT967
  PIN OUT968
    DIRECTION OUTPUT ;
    USE SIGNAL ;
    PORT
      LAYER Metal2 ;
      RECT 3540.720 0.000 3541.080 0.500 ;
    END
  END OUT968
  PIN OUT969
    DIRECTION OUTPUT ;
    USE SIGNAL ;
    PORT
      LAYER Metal2 ;
      RECT 3544.220 0.000 3544.580 0.500 ;
    END
  END OUT969
  PIN OUT970
    DIRECTION OUTPUT ;
    USE SIGNAL ;
    PORT
      LAYER Metal2 ;
      RECT 3547.720 0.000 3548.080 0.500 ;
    END
  END OUT970
  PIN OUT971
    DIRECTION OUTPUT ;
    USE SIGNAL ;
    PORT
      LAYER Metal2 ;
      RECT 3551.220 0.000 3551.580 0.500 ;
    END
  END OUT971
  PIN OUT972
    DIRECTION OUTPUT ;
    USE SIGNAL ;
    PORT
      LAYER Metal2 ;
      RECT 3554.720 0.000 3555.080 0.500 ;
    END
  END OUT972
  PIN OUT973
    DIRECTION OUTPUT ;
    USE SIGNAL ;
    PORT
      LAYER Metal2 ;
      RECT 3558.220 0.000 3558.580 0.500 ;
    END
  END OUT973
  PIN OUT974
    DIRECTION OUTPUT ;
    USE SIGNAL ;
    PORT
      LAYER Metal2 ;
      RECT 3561.720 0.000 3562.080 0.500 ;
    END
  END OUT974
  PIN OUT975
    DIRECTION OUTPUT ;
    USE SIGNAL ;
    PORT
      LAYER Metal2 ;
      RECT 3565.220 0.000 3565.580 0.500 ;
    END
  END OUT975
  PIN OUT976
    DIRECTION OUTPUT ;
    USE SIGNAL ;
    PORT
      LAYER Metal2 ;
      RECT 3568.720 0.000 3569.080 0.500 ;
    END
  END OUT976
  PIN OUT977
    DIRECTION OUTPUT ;
    USE SIGNAL ;
    PORT
      LAYER Metal2 ;
      RECT 3572.220 0.000 3572.580 0.500 ;
    END
  END OUT977
  PIN OUT978
    DIRECTION OUTPUT ;
    USE SIGNAL ;
    PORT
      LAYER Metal2 ;
      RECT 3575.720 0.000 3576.080 0.500 ;
    END
  END OUT978
  PIN OUT979
    DIRECTION OUTPUT ;
    USE SIGNAL ;
    PORT
      LAYER Metal2 ;
      RECT 3579.220 0.000 3579.580 0.500 ;
    END
  END OUT979
  PIN OUT980
    DIRECTION OUTPUT ;
    USE SIGNAL ;
    PORT
      LAYER Metal2 ;
      RECT 3582.720 0.000 3583.080 0.500 ;
    END
  END OUT980
  PIN OUT981
    DIRECTION OUTPUT ;
    USE SIGNAL ;
    PORT
      LAYER Metal2 ;
      RECT 3586.220 0.000 3586.580 0.500 ;
    END
  END OUT981
  PIN OUT982
    DIRECTION OUTPUT ;
    USE SIGNAL ;
    PORT
      LAYER Metal2 ;
      RECT 3589.720 0.000 3590.080 0.500 ;
    END
  END OUT982
  PIN OUT983
    DIRECTION OUTPUT ;
    USE SIGNAL ;
    PORT
      LAYER Metal2 ;
      RECT 3593.220 0.000 3593.580 0.500 ;
    END
  END OUT983
  PIN OUT984
    DIRECTION OUTPUT ;
    USE SIGNAL ;
    PORT
      LAYER Metal2 ;
      RECT 3596.720 0.000 3597.080 0.500 ;
    END
  END OUT984
  PIN OUT985
    DIRECTION OUTPUT ;
    USE SIGNAL ;
    PORT
      LAYER Metal2 ;
      RECT 3600.220 0.000 3600.580 0.500 ;
    END
  END OUT985
  PIN OUT986
    DIRECTION OUTPUT ;
    USE SIGNAL ;
    PORT
      LAYER Metal2 ;
      RECT 3603.720 0.000 3604.080 0.500 ;
    END
  END OUT986
  PIN OUT987
    DIRECTION OUTPUT ;
    USE SIGNAL ;
    PORT
      LAYER Metal2 ;
      RECT 3607.220 0.000 3607.580 0.500 ;
    END
  END OUT987
  PIN OUT988
    DIRECTION OUTPUT ;
    USE SIGNAL ;
    PORT
      LAYER Metal2 ;
      RECT 3610.720 0.000 3611.080 0.500 ;
    END
  END OUT988
  PIN OUT989
    DIRECTION OUTPUT ;
    USE SIGNAL ;
    PORT
      LAYER Metal2 ;
      RECT 3614.220 0.000 3614.580 0.500 ;
    END
  END OUT989
  PIN OUT990
    DIRECTION OUTPUT ;
    USE SIGNAL ;
    PORT
      LAYER Metal2 ;
      RECT 3617.720 0.000 3618.080 0.500 ;
    END
  END OUT990
  PIN OUT991
    DIRECTION OUTPUT ;
    USE SIGNAL ;
    PORT
      LAYER Metal2 ;
      RECT 3621.220 0.000 3621.580 0.500 ;
    END
  END OUT991
  PIN OUT992
    DIRECTION OUTPUT ;
    USE SIGNAL ;
    PORT
      LAYER Metal2 ;
      RECT 3624.720 0.000 3625.080 0.500 ;
    END
  END OUT992
  PIN OUT993
    DIRECTION OUTPUT ;
    USE SIGNAL ;
    PORT
      LAYER Metal2 ;
      RECT 3628.220 0.000 3628.580 0.500 ;
    END
  END OUT993
  PIN OUT994
    DIRECTION OUTPUT ;
    USE SIGNAL ;
    PORT
      LAYER Metal2 ;
      RECT 3631.720 0.000 3632.080 0.500 ;
    END
  END OUT994
  PIN OUT995
    DIRECTION OUTPUT ;
    USE SIGNAL ;
    PORT
      LAYER Metal2 ;
      RECT 3635.220 0.000 3635.580 0.500 ;
    END
  END OUT995
  PIN OUT996
    DIRECTION OUTPUT ;
    USE SIGNAL ;
    PORT
      LAYER Metal2 ;
      RECT 3638.720 0.000 3639.080 0.500 ;
    END
  END OUT996
  PIN OUT997
    DIRECTION OUTPUT ;
    USE SIGNAL ;
    PORT
      LAYER Metal2 ;
      RECT 3642.220 0.000 3642.580 0.500 ;
    END
  END OUT997
  PIN OUT998
    DIRECTION OUTPUT ;
    USE SIGNAL ;
    PORT
      LAYER Metal2 ;
      RECT 3645.720 0.000 3646.080 0.500 ;
    END
  END OUT998
  PIN OUT999
    DIRECTION OUTPUT ;
    USE SIGNAL ;
    PORT
      LAYER Metal2 ;
      RECT 3649.220 0.000 3649.580 0.500 ;
    END
  END OUT999
  PIN OUT1000
    DIRECTION OUTPUT ;
    USE SIGNAL ;
    PORT
      LAYER Metal2 ;
      RECT 3652.720 0.000 3653.080 0.500 ;
    END
  END OUT1000
  PIN OUT1001
    DIRECTION OUTPUT ;
    USE SIGNAL ;
    PORT
      LAYER Metal2 ;
      RECT 3656.220 0.000 3656.580 0.500 ;
    END
  END OUT1001
  PIN OUT1002
    DIRECTION OUTPUT ;
    USE SIGNAL ;
    PORT
      LAYER Metal2 ;
      RECT 3659.720 0.000 3660.080 0.500 ;
    END
  END OUT1002
  PIN OUT1003
    DIRECTION OUTPUT ;
    USE SIGNAL ;
    PORT
      LAYER Metal2 ;
      RECT 3663.220 0.000 3663.580 0.500 ;
    END
  END OUT1003
  PIN OUT1004
    DIRECTION OUTPUT ;
    USE SIGNAL ;
    PORT
      LAYER Metal2 ;
      RECT 3666.720 0.000 3667.080 0.500 ;
    END
  END OUT1004
  PIN OUT1005
    DIRECTION OUTPUT ;
    USE SIGNAL ;
    PORT
      LAYER Metal2 ;
      RECT 3670.220 0.000 3670.580 0.500 ;
    END
  END OUT1005
  PIN OUT1006
    DIRECTION OUTPUT ;
    USE SIGNAL ;
    PORT
      LAYER Metal2 ;
      RECT 3673.720 0.000 3674.080 0.500 ;
    END
  END OUT1006
  PIN OUT1007
    DIRECTION OUTPUT ;
    USE SIGNAL ;
    PORT
      LAYER Metal2 ;
      RECT 3677.220 0.000 3677.580 0.500 ;
    END
  END OUT1007
  PIN OUT1008
    DIRECTION OUTPUT ;
    USE SIGNAL ;
    PORT
      LAYER Metal2 ;
      RECT 3680.720 0.000 3681.080 0.500 ;
    END
  END OUT1008
  PIN OUT1009
    DIRECTION OUTPUT ;
    USE SIGNAL ;
    PORT
      LAYER Metal2 ;
      RECT 3684.220 0.000 3684.580 0.500 ;
    END
  END OUT1009
  PIN OUT1010
    DIRECTION OUTPUT ;
    USE SIGNAL ;
    PORT
      LAYER Metal2 ;
      RECT 3687.720 0.000 3688.080 0.500 ;
    END
  END OUT1010
  PIN OUT1011
    DIRECTION OUTPUT ;
    USE SIGNAL ;
    PORT
      LAYER Metal2 ;
      RECT 3691.220 0.000 3691.580 0.500 ;
    END
  END OUT1011
  PIN OUT1012
    DIRECTION OUTPUT ;
    USE SIGNAL ;
    PORT
      LAYER Metal2 ;
      RECT 3694.720 0.000 3695.080 0.500 ;
    END
  END OUT1012
  PIN OUT1013
    DIRECTION OUTPUT ;
    USE SIGNAL ;
    PORT
      LAYER Metal2 ;
      RECT 3698.220 0.000 3698.580 0.500 ;
    END
  END OUT1013
  PIN OUT1014
    DIRECTION OUTPUT ;
    USE SIGNAL ;
    PORT
      LAYER Metal2 ;
      RECT 3701.720 0.000 3702.080 0.500 ;
    END
  END OUT1014
  PIN OUT1015
    DIRECTION OUTPUT ;
    USE SIGNAL ;
    PORT
      LAYER Metal2 ;
      RECT 3705.220 0.000 3705.580 0.500 ;
    END
  END OUT1015
  PIN OUT1016
    DIRECTION OUTPUT ;
    USE SIGNAL ;
    PORT
      LAYER Metal2 ;
      RECT 3708.720 0.000 3709.080 0.500 ;
    END
  END OUT1016
  PIN OUT1017
    DIRECTION OUTPUT ;
    USE SIGNAL ;
    PORT
      LAYER Metal2 ;
      RECT 3712.220 0.000 3712.580 0.500 ;
    END
  END OUT1017
  PIN OUT1018
    DIRECTION OUTPUT ;
    USE SIGNAL ;
    PORT
      LAYER Metal2 ;
      RECT 3715.720 0.000 3716.080 0.500 ;
    END
  END OUT1018
  PIN OUT1019
    DIRECTION OUTPUT ;
    USE SIGNAL ;
    PORT
      LAYER Metal2 ;
      RECT 3719.220 0.000 3719.580 0.500 ;
    END
  END OUT1019
  PIN OUT1020
    DIRECTION OUTPUT ;
    USE SIGNAL ;
    PORT
      LAYER Metal2 ;
      RECT 3722.720 0.000 3723.080 0.500 ;
    END
  END OUT1020
  PIN OUT1021
    DIRECTION OUTPUT ;
    USE SIGNAL ;
    PORT
      LAYER Metal2 ;
      RECT 3726.220 0.000 3726.580 0.500 ;
    END
  END OUT1021
  PIN OUT1022
    DIRECTION OUTPUT ;
    USE SIGNAL ;
    PORT
      LAYER Metal2 ;
      RECT 3729.720 0.000 3730.080 0.500 ;
    END
  END OUT1022
  PIN OUT1023
    DIRECTION OUTPUT ;
    USE SIGNAL ;
    PORT
      LAYER Metal2 ;
      RECT 3733.220 0.000 3733.580 0.500 ;
    END
  END OUT1023
  PIN OUT1024
    DIRECTION OUTPUT ;
    USE SIGNAL ;
    PORT
      LAYER Metal2 ;
      RECT 3756.720 0.000 3757.080 0.500 ;
    END
  END OUT1024
  PIN OUT1025
    DIRECTION OUTPUT ;
    USE SIGNAL ;
    PORT
      LAYER Metal2 ;
      RECT 3760.220 0.000 3760.580 0.500 ;
    END
  END OUT1025
  PIN OUT1026
    DIRECTION OUTPUT ;
    USE SIGNAL ;
    PORT
      LAYER Metal2 ;
      RECT 3763.720 0.000 3764.080 0.500 ;
    END
  END OUT1026
  PIN OUT1027
    DIRECTION OUTPUT ;
    USE SIGNAL ;
    PORT
      LAYER Metal2 ;
      RECT 3767.220 0.000 3767.580 0.500 ;
    END
  END OUT1027
  PIN OUT1028
    DIRECTION OUTPUT ;
    USE SIGNAL ;
    PORT
      LAYER Metal2 ;
      RECT 3770.720 0.000 3771.080 0.500 ;
    END
  END OUT1028
  PIN OUT1029
    DIRECTION OUTPUT ;
    USE SIGNAL ;
    PORT
      LAYER Metal2 ;
      RECT 3774.220 0.000 3774.580 0.500 ;
    END
  END OUT1029
  PIN OUT1030
    DIRECTION OUTPUT ;
    USE SIGNAL ;
    PORT
      LAYER Metal2 ;
      RECT 3777.720 0.000 3778.080 0.500 ;
    END
  END OUT1030
  PIN OUT1031
    DIRECTION OUTPUT ;
    USE SIGNAL ;
    PORT
      LAYER Metal2 ;
      RECT 3781.220 0.000 3781.580 0.500 ;
    END
  END OUT1031
  PIN OUT1032
    DIRECTION OUTPUT ;
    USE SIGNAL ;
    PORT
      LAYER Metal2 ;
      RECT 3784.720 0.000 3785.080 0.500 ;
    END
  END OUT1032
  PIN OUT1033
    DIRECTION OUTPUT ;
    USE SIGNAL ;
    PORT
      LAYER Metal2 ;
      RECT 3788.220 0.000 3788.580 0.500 ;
    END
  END OUT1033
  PIN OUT1034
    DIRECTION OUTPUT ;
    USE SIGNAL ;
    PORT
      LAYER Metal2 ;
      RECT 3791.720 0.000 3792.080 0.500 ;
    END
  END OUT1034
  PIN OUT1035
    DIRECTION OUTPUT ;
    USE SIGNAL ;
    PORT
      LAYER Metal2 ;
      RECT 3795.220 0.000 3795.580 0.500 ;
    END
  END OUT1035
  PIN OUT1036
    DIRECTION OUTPUT ;
    USE SIGNAL ;
    PORT
      LAYER Metal2 ;
      RECT 3798.720 0.000 3799.080 0.500 ;
    END
  END OUT1036
  PIN OUT1037
    DIRECTION OUTPUT ;
    USE SIGNAL ;
    PORT
      LAYER Metal2 ;
      RECT 3802.220 0.000 3802.580 0.500 ;
    END
  END OUT1037
  PIN OUT1038
    DIRECTION OUTPUT ;
    USE SIGNAL ;
    PORT
      LAYER Metal2 ;
      RECT 3805.720 0.000 3806.080 0.500 ;
    END
  END OUT1038
  PIN OUT1039
    DIRECTION OUTPUT ;
    USE SIGNAL ;
    PORT
      LAYER Metal2 ;
      RECT 3809.220 0.000 3809.580 0.500 ;
    END
  END OUT1039
  PIN OUT1040
    DIRECTION OUTPUT ;
    USE SIGNAL ;
    PORT
      LAYER Metal2 ;
      RECT 3812.720 0.000 3813.080 0.500 ;
    END
  END OUT1040
  PIN OUT1041
    DIRECTION OUTPUT ;
    USE SIGNAL ;
    PORT
      LAYER Metal2 ;
      RECT 3816.220 0.000 3816.580 0.500 ;
    END
  END OUT1041
  PIN OUT1042
    DIRECTION OUTPUT ;
    USE SIGNAL ;
    PORT
      LAYER Metal2 ;
      RECT 3819.720 0.000 3820.080 0.500 ;
    END
  END OUT1042
  PIN OUT1043
    DIRECTION OUTPUT ;
    USE SIGNAL ;
    PORT
      LAYER Metal2 ;
      RECT 3823.220 0.000 3823.580 0.500 ;
    END
  END OUT1043
  PIN OUT1044
    DIRECTION OUTPUT ;
    USE SIGNAL ;
    PORT
      LAYER Metal2 ;
      RECT 3826.720 0.000 3827.080 0.500 ;
    END
  END OUT1044
  PIN OUT1045
    DIRECTION OUTPUT ;
    USE SIGNAL ;
    PORT
      LAYER Metal2 ;
      RECT 3830.220 0.000 3830.580 0.500 ;
    END
  END OUT1045
  PIN OUT1046
    DIRECTION OUTPUT ;
    USE SIGNAL ;
    PORT
      LAYER Metal2 ;
      RECT 3833.720 0.000 3834.080 0.500 ;
    END
  END OUT1046
  PIN OUT1047
    DIRECTION OUTPUT ;
    USE SIGNAL ;
    PORT
      LAYER Metal2 ;
      RECT 3837.220 0.000 3837.580 0.500 ;
    END
  END OUT1047
  PIN OUT1048
    DIRECTION OUTPUT ;
    USE SIGNAL ;
    PORT
      LAYER Metal2 ;
      RECT 3840.720 0.000 3841.080 0.500 ;
    END
  END OUT1048
  PIN OUT1049
    DIRECTION OUTPUT ;
    USE SIGNAL ;
    PORT
      LAYER Metal2 ;
      RECT 3844.220 0.000 3844.580 0.500 ;
    END
  END OUT1049
  PIN OUT1050
    DIRECTION OUTPUT ;
    USE SIGNAL ;
    PORT
      LAYER Metal2 ;
      RECT 3847.720 0.000 3848.080 0.500 ;
    END
  END OUT1050
  PIN OUT1051
    DIRECTION OUTPUT ;
    USE SIGNAL ;
    PORT
      LAYER Metal2 ;
      RECT 3851.220 0.000 3851.580 0.500 ;
    END
  END OUT1051
  PIN OUT1052
    DIRECTION OUTPUT ;
    USE SIGNAL ;
    PORT
      LAYER Metal2 ;
      RECT 3854.720 0.000 3855.080 0.500 ;
    END
  END OUT1052
  PIN OUT1053
    DIRECTION OUTPUT ;
    USE SIGNAL ;
    PORT
      LAYER Metal2 ;
      RECT 3858.220 0.000 3858.580 0.500 ;
    END
  END OUT1053
  PIN OUT1054
    DIRECTION OUTPUT ;
    USE SIGNAL ;
    PORT
      LAYER Metal2 ;
      RECT 3861.720 0.000 3862.080 0.500 ;
    END
  END OUT1054
  PIN OUT1055
    DIRECTION OUTPUT ;
    USE SIGNAL ;
    PORT
      LAYER Metal2 ;
      RECT 3865.220 0.000 3865.580 0.500 ;
    END
  END OUT1055
  PIN OUT1056
    DIRECTION OUTPUT ;
    USE SIGNAL ;
    PORT
      LAYER Metal2 ;
      RECT 3868.720 0.000 3869.080 0.500 ;
    END
  END OUT1056
  PIN OUT1057
    DIRECTION OUTPUT ;
    USE SIGNAL ;
    PORT
      LAYER Metal2 ;
      RECT 3872.220 0.000 3872.580 0.500 ;
    END
  END OUT1057
  PIN OUT1058
    DIRECTION OUTPUT ;
    USE SIGNAL ;
    PORT
      LAYER Metal2 ;
      RECT 3875.720 0.000 3876.080 0.500 ;
    END
  END OUT1058
  PIN OUT1059
    DIRECTION OUTPUT ;
    USE SIGNAL ;
    PORT
      LAYER Metal2 ;
      RECT 3879.220 0.000 3879.580 0.500 ;
    END
  END OUT1059
  PIN OUT1060
    DIRECTION OUTPUT ;
    USE SIGNAL ;
    PORT
      LAYER Metal2 ;
      RECT 3882.720 0.000 3883.080 0.500 ;
    END
  END OUT1060
  PIN OUT1061
    DIRECTION OUTPUT ;
    USE SIGNAL ;
    PORT
      LAYER Metal2 ;
      RECT 3886.220 0.000 3886.580 0.500 ;
    END
  END OUT1061
  PIN OUT1062
    DIRECTION OUTPUT ;
    USE SIGNAL ;
    PORT
      LAYER Metal2 ;
      RECT 3889.720 0.000 3890.080 0.500 ;
    END
  END OUT1062
  PIN OUT1063
    DIRECTION OUTPUT ;
    USE SIGNAL ;
    PORT
      LAYER Metal2 ;
      RECT 3893.220 0.000 3893.580 0.500 ;
    END
  END OUT1063
  PIN OUT1064
    DIRECTION OUTPUT ;
    USE SIGNAL ;
    PORT
      LAYER Metal2 ;
      RECT 3896.720 0.000 3897.080 0.500 ;
    END
  END OUT1064
  PIN OUT1065
    DIRECTION OUTPUT ;
    USE SIGNAL ;
    PORT
      LAYER Metal2 ;
      RECT 3900.220 0.000 3900.580 0.500 ;
    END
  END OUT1065
  PIN OUT1066
    DIRECTION OUTPUT ;
    USE SIGNAL ;
    PORT
      LAYER Metal2 ;
      RECT 3903.720 0.000 3904.080 0.500 ;
    END
  END OUT1066
  PIN OUT1067
    DIRECTION OUTPUT ;
    USE SIGNAL ;
    PORT
      LAYER Metal2 ;
      RECT 3907.220 0.000 3907.580 0.500 ;
    END
  END OUT1067
  PIN OUT1068
    DIRECTION OUTPUT ;
    USE SIGNAL ;
    PORT
      LAYER Metal2 ;
      RECT 3910.720 0.000 3911.080 0.500 ;
    END
  END OUT1068
  PIN OUT1069
    DIRECTION OUTPUT ;
    USE SIGNAL ;
    PORT
      LAYER Metal2 ;
      RECT 3914.220 0.000 3914.580 0.500 ;
    END
  END OUT1069
  PIN OUT1070
    DIRECTION OUTPUT ;
    USE SIGNAL ;
    PORT
      LAYER Metal2 ;
      RECT 3917.720 0.000 3918.080 0.500 ;
    END
  END OUT1070
  PIN OUT1071
    DIRECTION OUTPUT ;
    USE SIGNAL ;
    PORT
      LAYER Metal2 ;
      RECT 3921.220 0.000 3921.580 0.500 ;
    END
  END OUT1071
  PIN OUT1072
    DIRECTION OUTPUT ;
    USE SIGNAL ;
    PORT
      LAYER Metal2 ;
      RECT 3924.720 0.000 3925.080 0.500 ;
    END
  END OUT1072
  PIN OUT1073
    DIRECTION OUTPUT ;
    USE SIGNAL ;
    PORT
      LAYER Metal2 ;
      RECT 3928.220 0.000 3928.580 0.500 ;
    END
  END OUT1073
  PIN OUT1074
    DIRECTION OUTPUT ;
    USE SIGNAL ;
    PORT
      LAYER Metal2 ;
      RECT 3931.720 0.000 3932.080 0.500 ;
    END
  END OUT1074
  PIN OUT1075
    DIRECTION OUTPUT ;
    USE SIGNAL ;
    PORT
      LAYER Metal2 ;
      RECT 3935.220 0.000 3935.580 0.500 ;
    END
  END OUT1075
  PIN OUT1076
    DIRECTION OUTPUT ;
    USE SIGNAL ;
    PORT
      LAYER Metal2 ;
      RECT 3938.720 0.000 3939.080 0.500 ;
    END
  END OUT1076
  PIN OUT1077
    DIRECTION OUTPUT ;
    USE SIGNAL ;
    PORT
      LAYER Metal2 ;
      RECT 3942.220 0.000 3942.580 0.500 ;
    END
  END OUT1077
  PIN OUT1078
    DIRECTION OUTPUT ;
    USE SIGNAL ;
    PORT
      LAYER Metal2 ;
      RECT 3945.720 0.000 3946.080 0.500 ;
    END
  END OUT1078
  PIN OUT1079
    DIRECTION OUTPUT ;
    USE SIGNAL ;
    PORT
      LAYER Metal2 ;
      RECT 3949.220 0.000 3949.580 0.500 ;
    END
  END OUT1079
  PIN OUT1080
    DIRECTION OUTPUT ;
    USE SIGNAL ;
    PORT
      LAYER Metal2 ;
      RECT 3952.720 0.000 3953.080 0.500 ;
    END
  END OUT1080
  PIN OUT1081
    DIRECTION OUTPUT ;
    USE SIGNAL ;
    PORT
      LAYER Metal2 ;
      RECT 3956.220 0.000 3956.580 0.500 ;
    END
  END OUT1081
  PIN OUT1082
    DIRECTION OUTPUT ;
    USE SIGNAL ;
    PORT
      LAYER Metal2 ;
      RECT 3959.720 0.000 3960.080 0.500 ;
    END
  END OUT1082
  PIN OUT1083
    DIRECTION OUTPUT ;
    USE SIGNAL ;
    PORT
      LAYER Metal2 ;
      RECT 3963.220 0.000 3963.580 0.500 ;
    END
  END OUT1083
  PIN OUT1084
    DIRECTION OUTPUT ;
    USE SIGNAL ;
    PORT
      LAYER Metal2 ;
      RECT 3966.720 0.000 3967.080 0.500 ;
    END
  END OUT1084
  PIN OUT1085
    DIRECTION OUTPUT ;
    USE SIGNAL ;
    PORT
      LAYER Metal2 ;
      RECT 3970.220 0.000 3970.580 0.500 ;
    END
  END OUT1085
  PIN OUT1086
    DIRECTION OUTPUT ;
    USE SIGNAL ;
    PORT
      LAYER Metal2 ;
      RECT 3973.720 0.000 3974.080 0.500 ;
    END
  END OUT1086
  PIN OUT1087
    DIRECTION OUTPUT ;
    USE SIGNAL ;
    PORT
      LAYER Metal2 ;
      RECT 3977.220 0.000 3977.580 0.500 ;
    END
  END OUT1087
  PIN OUT1088
    DIRECTION OUTPUT ;
    USE SIGNAL ;
    PORT
      LAYER Metal2 ;
      RECT 3980.720 0.000 3981.080 0.500 ;
    END
  END OUT1088
  PIN OUT1089
    DIRECTION OUTPUT ;
    USE SIGNAL ;
    PORT
      LAYER Metal2 ;
      RECT 3984.220 0.000 3984.580 0.500 ;
    END
  END OUT1089
  PIN OUT1090
    DIRECTION OUTPUT ;
    USE SIGNAL ;
    PORT
      LAYER Metal2 ;
      RECT 3987.720 0.000 3988.080 0.500 ;
    END
  END OUT1090
  PIN OUT1091
    DIRECTION OUTPUT ;
    USE SIGNAL ;
    PORT
      LAYER Metal2 ;
      RECT 3991.220 0.000 3991.580 0.500 ;
    END
  END OUT1091
  PIN OUT1092
    DIRECTION OUTPUT ;
    USE SIGNAL ;
    PORT
      LAYER Metal2 ;
      RECT 3994.720 0.000 3995.080 0.500 ;
    END
  END OUT1092
  PIN OUT1093
    DIRECTION OUTPUT ;
    USE SIGNAL ;
    PORT
      LAYER Metal2 ;
      RECT 3998.220 0.000 3998.580 0.500 ;
    END
  END OUT1093
  PIN OUT1094
    DIRECTION OUTPUT ;
    USE SIGNAL ;
    PORT
      LAYER Metal2 ;
      RECT 4001.720 0.000 4002.080 0.500 ;
    END
  END OUT1094
  PIN OUT1095
    DIRECTION OUTPUT ;
    USE SIGNAL ;
    PORT
      LAYER Metal2 ;
      RECT 4005.220 0.000 4005.580 0.500 ;
    END
  END OUT1095
  PIN OUT1096
    DIRECTION OUTPUT ;
    USE SIGNAL ;
    PORT
      LAYER Metal2 ;
      RECT 4008.720 0.000 4009.080 0.500 ;
    END
  END OUT1096
  PIN OUT1097
    DIRECTION OUTPUT ;
    USE SIGNAL ;
    PORT
      LAYER Metal2 ;
      RECT 4012.220 0.000 4012.580 0.500 ;
    END
  END OUT1097
  PIN OUT1098
    DIRECTION OUTPUT ;
    USE SIGNAL ;
    PORT
      LAYER Metal2 ;
      RECT 4015.720 0.000 4016.080 0.500 ;
    END
  END OUT1098
  PIN OUT1099
    DIRECTION OUTPUT ;
    USE SIGNAL ;
    PORT
      LAYER Metal2 ;
      RECT 4019.220 0.000 4019.580 0.500 ;
    END
  END OUT1099
  PIN OUT1100
    DIRECTION OUTPUT ;
    USE SIGNAL ;
    PORT
      LAYER Metal2 ;
      RECT 4022.720 0.000 4023.080 0.500 ;
    END
  END OUT1100
  PIN OUT1101
    DIRECTION OUTPUT ;
    USE SIGNAL ;
    PORT
      LAYER Metal2 ;
      RECT 4026.220 0.000 4026.580 0.500 ;
    END
  END OUT1101
  PIN OUT1102
    DIRECTION OUTPUT ;
    USE SIGNAL ;
    PORT
      LAYER Metal2 ;
      RECT 4029.720 0.000 4030.080 0.500 ;
    END
  END OUT1102
  PIN OUT1103
    DIRECTION OUTPUT ;
    USE SIGNAL ;
    PORT
      LAYER Metal2 ;
      RECT 4033.220 0.000 4033.580 0.500 ;
    END
  END OUT1103
  PIN OUT1104
    DIRECTION OUTPUT ;
    USE SIGNAL ;
    PORT
      LAYER Metal2 ;
      RECT 4036.720 0.000 4037.080 0.500 ;
    END
  END OUT1104
  PIN OUT1105
    DIRECTION OUTPUT ;
    USE SIGNAL ;
    PORT
      LAYER Metal2 ;
      RECT 4040.220 0.000 4040.580 0.500 ;
    END
  END OUT1105
  PIN OUT1106
    DIRECTION OUTPUT ;
    USE SIGNAL ;
    PORT
      LAYER Metal2 ;
      RECT 4043.720 0.000 4044.080 0.500 ;
    END
  END OUT1106
  PIN OUT1107
    DIRECTION OUTPUT ;
    USE SIGNAL ;
    PORT
      LAYER Metal2 ;
      RECT 4047.220 0.000 4047.580 0.500 ;
    END
  END OUT1107
  PIN OUT1108
    DIRECTION OUTPUT ;
    USE SIGNAL ;
    PORT
      LAYER Metal2 ;
      RECT 4050.720 0.000 4051.080 0.500 ;
    END
  END OUT1108
  PIN OUT1109
    DIRECTION OUTPUT ;
    USE SIGNAL ;
    PORT
      LAYER Metal2 ;
      RECT 4054.220 0.000 4054.580 0.500 ;
    END
  END OUT1109
  PIN OUT1110
    DIRECTION OUTPUT ;
    USE SIGNAL ;
    PORT
      LAYER Metal2 ;
      RECT 4057.720 0.000 4058.080 0.500 ;
    END
  END OUT1110
  PIN OUT1111
    DIRECTION OUTPUT ;
    USE SIGNAL ;
    PORT
      LAYER Metal2 ;
      RECT 4061.220 0.000 4061.580 0.500 ;
    END
  END OUT1111
  PIN OUT1112
    DIRECTION OUTPUT ;
    USE SIGNAL ;
    PORT
      LAYER Metal2 ;
      RECT 4064.720 0.000 4065.080 0.500 ;
    END
  END OUT1112
  PIN OUT1113
    DIRECTION OUTPUT ;
    USE SIGNAL ;
    PORT
      LAYER Metal2 ;
      RECT 4068.220 0.000 4068.580 0.500 ;
    END
  END OUT1113
  PIN OUT1114
    DIRECTION OUTPUT ;
    USE SIGNAL ;
    PORT
      LAYER Metal2 ;
      RECT 4071.720 0.000 4072.080 0.500 ;
    END
  END OUT1114
  PIN OUT1115
    DIRECTION OUTPUT ;
    USE SIGNAL ;
    PORT
      LAYER Metal2 ;
      RECT 4075.220 0.000 4075.580 0.500 ;
    END
  END OUT1115
  PIN OUT1116
    DIRECTION OUTPUT ;
    USE SIGNAL ;
    PORT
      LAYER Metal2 ;
      RECT 4078.720 0.000 4079.080 0.500 ;
    END
  END OUT1116
  PIN OUT1117
    DIRECTION OUTPUT ;
    USE SIGNAL ;
    PORT
      LAYER Metal2 ;
      RECT 4082.220 0.000 4082.580 0.500 ;
    END
  END OUT1117
  PIN OUT1118
    DIRECTION OUTPUT ;
    USE SIGNAL ;
    PORT
      LAYER Metal2 ;
      RECT 4085.720 0.000 4086.080 0.500 ;
    END
  END OUT1118
  PIN OUT1119
    DIRECTION OUTPUT ;
    USE SIGNAL ;
    PORT
      LAYER Metal2 ;
      RECT 4089.220 0.000 4089.580 0.500 ;
    END
  END OUT1119
  PIN OUT1120
    DIRECTION OUTPUT ;
    USE SIGNAL ;
    PORT
      LAYER Metal2 ;
      RECT 4092.720 0.000 4093.080 0.500 ;
    END
  END OUT1120
  PIN OUT1121
    DIRECTION OUTPUT ;
    USE SIGNAL ;
    PORT
      LAYER Metal2 ;
      RECT 4096.220 0.000 4096.580 0.500 ;
    END
  END OUT1121
  PIN OUT1122
    DIRECTION OUTPUT ;
    USE SIGNAL ;
    PORT
      LAYER Metal2 ;
      RECT 4099.720 0.000 4100.080 0.500 ;
    END
  END OUT1122
  PIN OUT1123
    DIRECTION OUTPUT ;
    USE SIGNAL ;
    PORT
      LAYER Metal2 ;
      RECT 4103.220 0.000 4103.580 0.500 ;
    END
  END OUT1123
  PIN OUT1124
    DIRECTION OUTPUT ;
    USE SIGNAL ;
    PORT
      LAYER Metal2 ;
      RECT 4106.720 0.000 4107.080 0.500 ;
    END
  END OUT1124
  PIN OUT1125
    DIRECTION OUTPUT ;
    USE SIGNAL ;
    PORT
      LAYER Metal2 ;
      RECT 4110.220 0.000 4110.580 0.500 ;
    END
  END OUT1125
  PIN OUT1126
    DIRECTION OUTPUT ;
    USE SIGNAL ;
    PORT
      LAYER Metal2 ;
      RECT 4113.720 0.000 4114.080 0.500 ;
    END
  END OUT1126
  PIN OUT1127
    DIRECTION OUTPUT ;
    USE SIGNAL ;
    PORT
      LAYER Metal2 ;
      RECT 4117.220 0.000 4117.580 0.500 ;
    END
  END OUT1127
  PIN OUT1128
    DIRECTION OUTPUT ;
    USE SIGNAL ;
    PORT
      LAYER Metal2 ;
      RECT 4120.720 0.000 4121.080 0.500 ;
    END
  END OUT1128
  PIN OUT1129
    DIRECTION OUTPUT ;
    USE SIGNAL ;
    PORT
      LAYER Metal2 ;
      RECT 4124.220 0.000 4124.580 0.500 ;
    END
  END OUT1129
  PIN OUT1130
    DIRECTION OUTPUT ;
    USE SIGNAL ;
    PORT
      LAYER Metal2 ;
      RECT 4127.720 0.000 4128.080 0.500 ;
    END
  END OUT1130
  PIN OUT1131
    DIRECTION OUTPUT ;
    USE SIGNAL ;
    PORT
      LAYER Metal2 ;
      RECT 4131.220 0.000 4131.580 0.500 ;
    END
  END OUT1131
  PIN OUT1132
    DIRECTION OUTPUT ;
    USE SIGNAL ;
    PORT
      LAYER Metal2 ;
      RECT 4134.720 0.000 4135.080 0.500 ;
    END
  END OUT1132
  PIN OUT1133
    DIRECTION OUTPUT ;
    USE SIGNAL ;
    PORT
      LAYER Metal2 ;
      RECT 4138.220 0.000 4138.580 0.500 ;
    END
  END OUT1133
  PIN OUT1134
    DIRECTION OUTPUT ;
    USE SIGNAL ;
    PORT
      LAYER Metal2 ;
      RECT 4141.720 0.000 4142.080 0.500 ;
    END
  END OUT1134
  PIN OUT1135
    DIRECTION OUTPUT ;
    USE SIGNAL ;
    PORT
      LAYER Metal2 ;
      RECT 4145.220 0.000 4145.580 0.500 ;
    END
  END OUT1135
  PIN OUT1136
    DIRECTION OUTPUT ;
    USE SIGNAL ;
    PORT
      LAYER Metal2 ;
      RECT 4148.720 0.000 4149.080 0.500 ;
    END
  END OUT1136
  PIN OUT1137
    DIRECTION OUTPUT ;
    USE SIGNAL ;
    PORT
      LAYER Metal2 ;
      RECT 4152.220 0.000 4152.580 0.500 ;
    END
  END OUT1137
  PIN OUT1138
    DIRECTION OUTPUT ;
    USE SIGNAL ;
    PORT
      LAYER Metal2 ;
      RECT 4155.720 0.000 4156.080 0.500 ;
    END
  END OUT1138
  PIN OUT1139
    DIRECTION OUTPUT ;
    USE SIGNAL ;
    PORT
      LAYER Metal2 ;
      RECT 4159.220 0.000 4159.580 0.500 ;
    END
  END OUT1139
  PIN OUT1140
    DIRECTION OUTPUT ;
    USE SIGNAL ;
    PORT
      LAYER Metal2 ;
      RECT 4162.720 0.000 4163.080 0.500 ;
    END
  END OUT1140
  PIN OUT1141
    DIRECTION OUTPUT ;
    USE SIGNAL ;
    PORT
      LAYER Metal2 ;
      RECT 4166.220 0.000 4166.580 0.500 ;
    END
  END OUT1141
  PIN OUT1142
    DIRECTION OUTPUT ;
    USE SIGNAL ;
    PORT
      LAYER Metal2 ;
      RECT 4169.720 0.000 4170.080 0.500 ;
    END
  END OUT1142
  PIN OUT1143
    DIRECTION OUTPUT ;
    USE SIGNAL ;
    PORT
      LAYER Metal2 ;
      RECT 4173.220 0.000 4173.580 0.500 ;
    END
  END OUT1143
  PIN OUT1144
    DIRECTION OUTPUT ;
    USE SIGNAL ;
    PORT
      LAYER Metal2 ;
      RECT 4176.720 0.000 4177.080 0.500 ;
    END
  END OUT1144
  PIN OUT1145
    DIRECTION OUTPUT ;
    USE SIGNAL ;
    PORT
      LAYER Metal2 ;
      RECT 4180.220 0.000 4180.580 0.500 ;
    END
  END OUT1145
  PIN OUT1146
    DIRECTION OUTPUT ;
    USE SIGNAL ;
    PORT
      LAYER Metal2 ;
      RECT 4183.720 0.000 4184.080 0.500 ;
    END
  END OUT1146
  PIN OUT1147
    DIRECTION OUTPUT ;
    USE SIGNAL ;
    PORT
      LAYER Metal2 ;
      RECT 4187.220 0.000 4187.580 0.500 ;
    END
  END OUT1147
  PIN OUT1148
    DIRECTION OUTPUT ;
    USE SIGNAL ;
    PORT
      LAYER Metal2 ;
      RECT 4190.720 0.000 4191.080 0.500 ;
    END
  END OUT1148
  PIN OUT1149
    DIRECTION OUTPUT ;
    USE SIGNAL ;
    PORT
      LAYER Metal2 ;
      RECT 4194.220 0.000 4194.580 0.500 ;
    END
  END OUT1149
  PIN OUT1150
    DIRECTION OUTPUT ;
    USE SIGNAL ;
    PORT
      LAYER Metal2 ;
      RECT 4197.720 0.000 4198.080 0.500 ;
    END
  END OUT1150
  PIN OUT1151
    DIRECTION OUTPUT ;
    USE SIGNAL ;
    PORT
      LAYER Metal2 ;
      RECT 4201.220 0.000 4201.580 0.500 ;
    END
  END OUT1151
  PIN OUT1152
    DIRECTION OUTPUT ;
    USE SIGNAL ;
    PORT
      LAYER Metal2 ;
      RECT 4224.720 0.000 4225.080 0.500 ;
    END
  END OUT1152
  PIN OUT1153
    DIRECTION OUTPUT ;
    USE SIGNAL ;
    PORT
      LAYER Metal2 ;
      RECT 4228.220 0.000 4228.580 0.500 ;
    END
  END OUT1153
  PIN OUT1154
    DIRECTION OUTPUT ;
    USE SIGNAL ;
    PORT
      LAYER Metal2 ;
      RECT 4231.720 0.000 4232.080 0.500 ;
    END
  END OUT1154
  PIN OUT1155
    DIRECTION OUTPUT ;
    USE SIGNAL ;
    PORT
      LAYER Metal2 ;
      RECT 4235.220 0.000 4235.580 0.500 ;
    END
  END OUT1155
  PIN OUT1156
    DIRECTION OUTPUT ;
    USE SIGNAL ;
    PORT
      LAYER Metal2 ;
      RECT 4238.720 0.000 4239.080 0.500 ;
    END
  END OUT1156
  PIN OUT1157
    DIRECTION OUTPUT ;
    USE SIGNAL ;
    PORT
      LAYER Metal2 ;
      RECT 4242.220 0.000 4242.580 0.500 ;
    END
  END OUT1157
  PIN OUT1158
    DIRECTION OUTPUT ;
    USE SIGNAL ;
    PORT
      LAYER Metal2 ;
      RECT 4245.720 0.000 4246.080 0.500 ;
    END
  END OUT1158
  PIN OUT1159
    DIRECTION OUTPUT ;
    USE SIGNAL ;
    PORT
      LAYER Metal2 ;
      RECT 4249.220 0.000 4249.580 0.500 ;
    END
  END OUT1159
  PIN OUT1160
    DIRECTION OUTPUT ;
    USE SIGNAL ;
    PORT
      LAYER Metal2 ;
      RECT 4252.720 0.000 4253.080 0.500 ;
    END
  END OUT1160
  PIN OUT1161
    DIRECTION OUTPUT ;
    USE SIGNAL ;
    PORT
      LAYER Metal2 ;
      RECT 4256.220 0.000 4256.580 0.500 ;
    END
  END OUT1161
  PIN OUT1162
    DIRECTION OUTPUT ;
    USE SIGNAL ;
    PORT
      LAYER Metal2 ;
      RECT 4259.720 0.000 4260.080 0.500 ;
    END
  END OUT1162
  PIN OUT1163
    DIRECTION OUTPUT ;
    USE SIGNAL ;
    PORT
      LAYER Metal2 ;
      RECT 4263.220 0.000 4263.580 0.500 ;
    END
  END OUT1163
  PIN OUT1164
    DIRECTION OUTPUT ;
    USE SIGNAL ;
    PORT
      LAYER Metal2 ;
      RECT 4266.720 0.000 4267.080 0.500 ;
    END
  END OUT1164
  PIN OUT1165
    DIRECTION OUTPUT ;
    USE SIGNAL ;
    PORT
      LAYER Metal2 ;
      RECT 4270.220 0.000 4270.580 0.500 ;
    END
  END OUT1165
  PIN OUT1166
    DIRECTION OUTPUT ;
    USE SIGNAL ;
    PORT
      LAYER Metal2 ;
      RECT 4273.720 0.000 4274.080 0.500 ;
    END
  END OUT1166
  PIN OUT1167
    DIRECTION OUTPUT ;
    USE SIGNAL ;
    PORT
      LAYER Metal2 ;
      RECT 4277.220 0.000 4277.580 0.500 ;
    END
  END OUT1167
  PIN OUT1168
    DIRECTION OUTPUT ;
    USE SIGNAL ;
    PORT
      LAYER Metal2 ;
      RECT 4280.720 0.000 4281.080 0.500 ;
    END
  END OUT1168
  PIN OUT1169
    DIRECTION OUTPUT ;
    USE SIGNAL ;
    PORT
      LAYER Metal2 ;
      RECT 4284.220 0.000 4284.580 0.500 ;
    END
  END OUT1169
  PIN OUT1170
    DIRECTION OUTPUT ;
    USE SIGNAL ;
    PORT
      LAYER Metal2 ;
      RECT 4287.720 0.000 4288.080 0.500 ;
    END
  END OUT1170
  PIN OUT1171
    DIRECTION OUTPUT ;
    USE SIGNAL ;
    PORT
      LAYER Metal2 ;
      RECT 4291.220 0.000 4291.580 0.500 ;
    END
  END OUT1171
  PIN OUT1172
    DIRECTION OUTPUT ;
    USE SIGNAL ;
    PORT
      LAYER Metal2 ;
      RECT 4294.720 0.000 4295.080 0.500 ;
    END
  END OUT1172
  PIN OUT1173
    DIRECTION OUTPUT ;
    USE SIGNAL ;
    PORT
      LAYER Metal2 ;
      RECT 4298.220 0.000 4298.580 0.500 ;
    END
  END OUT1173
  PIN OUT1174
    DIRECTION OUTPUT ;
    USE SIGNAL ;
    PORT
      LAYER Metal2 ;
      RECT 4301.720 0.000 4302.080 0.500 ;
    END
  END OUT1174
  PIN OUT1175
    DIRECTION OUTPUT ;
    USE SIGNAL ;
    PORT
      LAYER Metal2 ;
      RECT 4305.220 0.000 4305.580 0.500 ;
    END
  END OUT1175
  PIN OUT1176
    DIRECTION OUTPUT ;
    USE SIGNAL ;
    PORT
      LAYER Metal2 ;
      RECT 4308.720 0.000 4309.080 0.500 ;
    END
  END OUT1176
  PIN OUT1177
    DIRECTION OUTPUT ;
    USE SIGNAL ;
    PORT
      LAYER Metal2 ;
      RECT 4312.220 0.000 4312.580 0.500 ;
    END
  END OUT1177
  PIN OUT1178
    DIRECTION OUTPUT ;
    USE SIGNAL ;
    PORT
      LAYER Metal2 ;
      RECT 4315.720 0.000 4316.080 0.500 ;
    END
  END OUT1178
  PIN OUT1179
    DIRECTION OUTPUT ;
    USE SIGNAL ;
    PORT
      LAYER Metal2 ;
      RECT 4319.220 0.000 4319.580 0.500 ;
    END
  END OUT1179
  PIN OUT1180
    DIRECTION OUTPUT ;
    USE SIGNAL ;
    PORT
      LAYER Metal2 ;
      RECT 4322.720 0.000 4323.080 0.500 ;
    END
  END OUT1180
  PIN OUT1181
    DIRECTION OUTPUT ;
    USE SIGNAL ;
    PORT
      LAYER Metal2 ;
      RECT 4326.220 0.000 4326.580 0.500 ;
    END
  END OUT1181
  PIN OUT1182
    DIRECTION OUTPUT ;
    USE SIGNAL ;
    PORT
      LAYER Metal2 ;
      RECT 4329.720 0.000 4330.080 0.500 ;
    END
  END OUT1182
  PIN OUT1183
    DIRECTION OUTPUT ;
    USE SIGNAL ;
    PORT
      LAYER Metal2 ;
      RECT 4333.220 0.000 4333.580 0.500 ;
    END
  END OUT1183
  PIN OUT1184
    DIRECTION OUTPUT ;
    USE SIGNAL ;
    PORT
      LAYER Metal2 ;
      RECT 4336.720 0.000 4337.080 0.500 ;
    END
  END OUT1184
  PIN OUT1185
    DIRECTION OUTPUT ;
    USE SIGNAL ;
    PORT
      LAYER Metal2 ;
      RECT 4340.220 0.000 4340.580 0.500 ;
    END
  END OUT1185
  PIN OUT1186
    DIRECTION OUTPUT ;
    USE SIGNAL ;
    PORT
      LAYER Metal2 ;
      RECT 4343.720 0.000 4344.080 0.500 ;
    END
  END OUT1186
  PIN OUT1187
    DIRECTION OUTPUT ;
    USE SIGNAL ;
    PORT
      LAYER Metal2 ;
      RECT 4347.220 0.000 4347.580 0.500 ;
    END
  END OUT1187
  PIN OUT1188
    DIRECTION OUTPUT ;
    USE SIGNAL ;
    PORT
      LAYER Metal2 ;
      RECT 4350.720 0.000 4351.080 0.500 ;
    END
  END OUT1188
  PIN OUT1189
    DIRECTION OUTPUT ;
    USE SIGNAL ;
    PORT
      LAYER Metal2 ;
      RECT 4354.220 0.000 4354.580 0.500 ;
    END
  END OUT1189
  PIN OUT1190
    DIRECTION OUTPUT ;
    USE SIGNAL ;
    PORT
      LAYER Metal2 ;
      RECT 4357.720 0.000 4358.080 0.500 ;
    END
  END OUT1190
  PIN OUT1191
    DIRECTION OUTPUT ;
    USE SIGNAL ;
    PORT
      LAYER Metal2 ;
      RECT 4361.220 0.000 4361.580 0.500 ;
    END
  END OUT1191
  PIN OUT1192
    DIRECTION OUTPUT ;
    USE SIGNAL ;
    PORT
      LAYER Metal2 ;
      RECT 4364.720 0.000 4365.080 0.500 ;
    END
  END OUT1192
  PIN OUT1193
    DIRECTION OUTPUT ;
    USE SIGNAL ;
    PORT
      LAYER Metal2 ;
      RECT 4368.220 0.000 4368.580 0.500 ;
    END
  END OUT1193
  PIN OUT1194
    DIRECTION OUTPUT ;
    USE SIGNAL ;
    PORT
      LAYER Metal2 ;
      RECT 4371.720 0.000 4372.080 0.500 ;
    END
  END OUT1194
  PIN OUT1195
    DIRECTION OUTPUT ;
    USE SIGNAL ;
    PORT
      LAYER Metal2 ;
      RECT 4375.220 0.000 4375.580 0.500 ;
    END
  END OUT1195
  PIN OUT1196
    DIRECTION OUTPUT ;
    USE SIGNAL ;
    PORT
      LAYER Metal2 ;
      RECT 4378.720 0.000 4379.080 0.500 ;
    END
  END OUT1196
  PIN OUT1197
    DIRECTION OUTPUT ;
    USE SIGNAL ;
    PORT
      LAYER Metal2 ;
      RECT 4382.220 0.000 4382.580 0.500 ;
    END
  END OUT1197
  PIN OUT1198
    DIRECTION OUTPUT ;
    USE SIGNAL ;
    PORT
      LAYER Metal2 ;
      RECT 4385.720 0.000 4386.080 0.500 ;
    END
  END OUT1198
  PIN OUT1199
    DIRECTION OUTPUT ;
    USE SIGNAL ;
    PORT
      LAYER Metal2 ;
      RECT 4389.220 0.000 4389.580 0.500 ;
    END
  END OUT1199
  PIN OUT1200
    DIRECTION OUTPUT ;
    USE SIGNAL ;
    PORT
      LAYER Metal2 ;
      RECT 4392.720 0.000 4393.080 0.500 ;
    END
  END OUT1200
  PIN OUT1201
    DIRECTION OUTPUT ;
    USE SIGNAL ;
    PORT
      LAYER Metal2 ;
      RECT 4396.220 0.000 4396.580 0.500 ;
    END
  END OUT1201
  PIN OUT1202
    DIRECTION OUTPUT ;
    USE SIGNAL ;
    PORT
      LAYER Metal2 ;
      RECT 4399.720 0.000 4400.080 0.500 ;
    END
  END OUT1202
  PIN OUT1203
    DIRECTION OUTPUT ;
    USE SIGNAL ;
    PORT
      LAYER Metal2 ;
      RECT 4403.220 0.000 4403.580 0.500 ;
    END
  END OUT1203
  PIN OUT1204
    DIRECTION OUTPUT ;
    USE SIGNAL ;
    PORT
      LAYER Metal2 ;
      RECT 4406.720 0.000 4407.080 0.500 ;
    END
  END OUT1204
  PIN OUT1205
    DIRECTION OUTPUT ;
    USE SIGNAL ;
    PORT
      LAYER Metal2 ;
      RECT 4410.220 0.000 4410.580 0.500 ;
    END
  END OUT1205
  PIN OUT1206
    DIRECTION OUTPUT ;
    USE SIGNAL ;
    PORT
      LAYER Metal2 ;
      RECT 4413.720 0.000 4414.080 0.500 ;
    END
  END OUT1206
  PIN OUT1207
    DIRECTION OUTPUT ;
    USE SIGNAL ;
    PORT
      LAYER Metal2 ;
      RECT 4417.220 0.000 4417.580 0.500 ;
    END
  END OUT1207
  PIN OUT1208
    DIRECTION OUTPUT ;
    USE SIGNAL ;
    PORT
      LAYER Metal2 ;
      RECT 4420.720 0.000 4421.080 0.500 ;
    END
  END OUT1208
  PIN OUT1209
    DIRECTION OUTPUT ;
    USE SIGNAL ;
    PORT
      LAYER Metal2 ;
      RECT 4424.220 0.000 4424.580 0.500 ;
    END
  END OUT1209
  PIN OUT1210
    DIRECTION OUTPUT ;
    USE SIGNAL ;
    PORT
      LAYER Metal2 ;
      RECT 4427.720 0.000 4428.080 0.500 ;
    END
  END OUT1210
  PIN OUT1211
    DIRECTION OUTPUT ;
    USE SIGNAL ;
    PORT
      LAYER Metal2 ;
      RECT 4431.220 0.000 4431.580 0.500 ;
    END
  END OUT1211
  PIN OUT1212
    DIRECTION OUTPUT ;
    USE SIGNAL ;
    PORT
      LAYER Metal2 ;
      RECT 4434.720 0.000 4435.080 0.500 ;
    END
  END OUT1212
  PIN OUT1213
    DIRECTION OUTPUT ;
    USE SIGNAL ;
    PORT
      LAYER Metal2 ;
      RECT 4438.220 0.000 4438.580 0.500 ;
    END
  END OUT1213
  PIN OUT1214
    DIRECTION OUTPUT ;
    USE SIGNAL ;
    PORT
      LAYER Metal2 ;
      RECT 4441.720 0.000 4442.080 0.500 ;
    END
  END OUT1214
  PIN OUT1215
    DIRECTION OUTPUT ;
    USE SIGNAL ;
    PORT
      LAYER Metal2 ;
      RECT 4445.220 0.000 4445.580 0.500 ;
    END
  END OUT1215
  PIN OUT1216
    DIRECTION OUTPUT ;
    USE SIGNAL ;
    PORT
      LAYER Metal2 ;
      RECT 4448.720 0.000 4449.080 0.500 ;
    END
  END OUT1216
  PIN OUT1217
    DIRECTION OUTPUT ;
    USE SIGNAL ;
    PORT
      LAYER Metal2 ;
      RECT 4452.220 0.000 4452.580 0.500 ;
    END
  END OUT1217
  PIN OUT1218
    DIRECTION OUTPUT ;
    USE SIGNAL ;
    PORT
      LAYER Metal2 ;
      RECT 4455.720 0.000 4456.080 0.500 ;
    END
  END OUT1218
  PIN OUT1219
    DIRECTION OUTPUT ;
    USE SIGNAL ;
    PORT
      LAYER Metal2 ;
      RECT 4459.220 0.000 4459.580 0.500 ;
    END
  END OUT1219
  PIN OUT1220
    DIRECTION OUTPUT ;
    USE SIGNAL ;
    PORT
      LAYER Metal2 ;
      RECT 4462.720 0.000 4463.080 0.500 ;
    END
  END OUT1220
  PIN OUT1221
    DIRECTION OUTPUT ;
    USE SIGNAL ;
    PORT
      LAYER Metal2 ;
      RECT 4466.220 0.000 4466.580 0.500 ;
    END
  END OUT1221
  PIN OUT1222
    DIRECTION OUTPUT ;
    USE SIGNAL ;
    PORT
      LAYER Metal2 ;
      RECT 4469.720 0.000 4470.080 0.500 ;
    END
  END OUT1222
  PIN OUT1223
    DIRECTION OUTPUT ;
    USE SIGNAL ;
    PORT
      LAYER Metal2 ;
      RECT 4473.220 0.000 4473.580 0.500 ;
    END
  END OUT1223
  PIN OUT1224
    DIRECTION OUTPUT ;
    USE SIGNAL ;
    PORT
      LAYER Metal2 ;
      RECT 4476.720 0.000 4477.080 0.500 ;
    END
  END OUT1224
  PIN OUT1225
    DIRECTION OUTPUT ;
    USE SIGNAL ;
    PORT
      LAYER Metal2 ;
      RECT 4480.220 0.000 4480.580 0.500 ;
    END
  END OUT1225
  PIN OUT1226
    DIRECTION OUTPUT ;
    USE SIGNAL ;
    PORT
      LAYER Metal2 ;
      RECT 4483.720 0.000 4484.080 0.500 ;
    END
  END OUT1226
  PIN OUT1227
    DIRECTION OUTPUT ;
    USE SIGNAL ;
    PORT
      LAYER Metal2 ;
      RECT 4487.220 0.000 4487.580 0.500 ;
    END
  END OUT1227
  PIN OUT1228
    DIRECTION OUTPUT ;
    USE SIGNAL ;
    PORT
      LAYER Metal2 ;
      RECT 4490.720 0.000 4491.080 0.500 ;
    END
  END OUT1228
  PIN OUT1229
    DIRECTION OUTPUT ;
    USE SIGNAL ;
    PORT
      LAYER Metal2 ;
      RECT 4494.220 0.000 4494.580 0.500 ;
    END
  END OUT1229
  PIN OUT1230
    DIRECTION OUTPUT ;
    USE SIGNAL ;
    PORT
      LAYER Metal2 ;
      RECT 4497.720 0.000 4498.080 0.500 ;
    END
  END OUT1230
  PIN OUT1231
    DIRECTION OUTPUT ;
    USE SIGNAL ;
    PORT
      LAYER Metal2 ;
      RECT 4501.220 0.000 4501.580 0.500 ;
    END
  END OUT1231
  PIN OUT1232
    DIRECTION OUTPUT ;
    USE SIGNAL ;
    PORT
      LAYER Metal2 ;
      RECT 4504.720 0.000 4505.080 0.500 ;
    END
  END OUT1232
  PIN OUT1233
    DIRECTION OUTPUT ;
    USE SIGNAL ;
    PORT
      LAYER Metal2 ;
      RECT 4508.220 0.000 4508.580 0.500 ;
    END
  END OUT1233
  PIN OUT1234
    DIRECTION OUTPUT ;
    USE SIGNAL ;
    PORT
      LAYER Metal2 ;
      RECT 4511.720 0.000 4512.080 0.500 ;
    END
  END OUT1234
  PIN OUT1235
    DIRECTION OUTPUT ;
    USE SIGNAL ;
    PORT
      LAYER Metal2 ;
      RECT 4515.220 0.000 4515.580 0.500 ;
    END
  END OUT1235
  PIN OUT1236
    DIRECTION OUTPUT ;
    USE SIGNAL ;
    PORT
      LAYER Metal2 ;
      RECT 4518.720 0.000 4519.080 0.500 ;
    END
  END OUT1236
  PIN OUT1237
    DIRECTION OUTPUT ;
    USE SIGNAL ;
    PORT
      LAYER Metal2 ;
      RECT 4522.220 0.000 4522.580 0.500 ;
    END
  END OUT1237
  PIN OUT1238
    DIRECTION OUTPUT ;
    USE SIGNAL ;
    PORT
      LAYER Metal2 ;
      RECT 4525.720 0.000 4526.080 0.500 ;
    END
  END OUT1238
  PIN OUT1239
    DIRECTION OUTPUT ;
    USE SIGNAL ;
    PORT
      LAYER Metal2 ;
      RECT 4529.220 0.000 4529.580 0.500 ;
    END
  END OUT1239
  PIN OUT1240
    DIRECTION OUTPUT ;
    USE SIGNAL ;
    PORT
      LAYER Metal2 ;
      RECT 4532.720 0.000 4533.080 0.500 ;
    END
  END OUT1240
  PIN OUT1241
    DIRECTION OUTPUT ;
    USE SIGNAL ;
    PORT
      LAYER Metal2 ;
      RECT 4536.220 0.000 4536.580 0.500 ;
    END
  END OUT1241
  PIN OUT1242
    DIRECTION OUTPUT ;
    USE SIGNAL ;
    PORT
      LAYER Metal2 ;
      RECT 4539.720 0.000 4540.080 0.500 ;
    END
  END OUT1242
  PIN OUT1243
    DIRECTION OUTPUT ;
    USE SIGNAL ;
    PORT
      LAYER Metal2 ;
      RECT 4543.220 0.000 4543.580 0.500 ;
    END
  END OUT1243
  PIN OUT1244
    DIRECTION OUTPUT ;
    USE SIGNAL ;
    PORT
      LAYER Metal2 ;
      RECT 4546.720 0.000 4547.080 0.500 ;
    END
  END OUT1244
  PIN OUT1245
    DIRECTION OUTPUT ;
    USE SIGNAL ;
    PORT
      LAYER Metal2 ;
      RECT 4550.220 0.000 4550.580 0.500 ;
    END
  END OUT1245
  PIN OUT1246
    DIRECTION OUTPUT ;
    USE SIGNAL ;
    PORT
      LAYER Metal2 ;
      RECT 4553.720 0.000 4554.080 0.500 ;
    END
  END OUT1246
  PIN OUT1247
    DIRECTION OUTPUT ;
    USE SIGNAL ;
    PORT
      LAYER Metal2 ;
      RECT 4557.220 0.000 4557.580 0.500 ;
    END
  END OUT1247
  PIN OUT1248
    DIRECTION OUTPUT ;
    USE SIGNAL ;
    PORT
      LAYER Metal2 ;
      RECT 4560.720 0.000 4561.080 0.500 ;
    END
  END OUT1248
  PIN OUT1249
    DIRECTION OUTPUT ;
    USE SIGNAL ;
    PORT
      LAYER Metal2 ;
      RECT 4564.220 0.000 4564.580 0.500 ;
    END
  END OUT1249
  PIN OUT1250
    DIRECTION OUTPUT ;
    USE SIGNAL ;
    PORT
      LAYER Metal2 ;
      RECT 4567.720 0.000 4568.080 0.500 ;
    END
  END OUT1250
  PIN OUT1251
    DIRECTION OUTPUT ;
    USE SIGNAL ;
    PORT
      LAYER Metal2 ;
      RECT 4571.220 0.000 4571.580 0.500 ;
    END
  END OUT1251
  PIN OUT1252
    DIRECTION OUTPUT ;
    USE SIGNAL ;
    PORT
      LAYER Metal2 ;
      RECT 4574.720 0.000 4575.080 0.500 ;
    END
  END OUT1252
  PIN OUT1253
    DIRECTION OUTPUT ;
    USE SIGNAL ;
    PORT
      LAYER Metal2 ;
      RECT 4578.220 0.000 4578.580 0.500 ;
    END
  END OUT1253
  PIN OUT1254
    DIRECTION OUTPUT ;
    USE SIGNAL ;
    PORT
      LAYER Metal2 ;
      RECT 4581.720 0.000 4582.080 0.500 ;
    END
  END OUT1254
  PIN OUT1255
    DIRECTION OUTPUT ;
    USE SIGNAL ;
    PORT
      LAYER Metal2 ;
      RECT 4585.220 0.000 4585.580 0.500 ;
    END
  END OUT1255
  PIN OUT1256
    DIRECTION OUTPUT ;
    USE SIGNAL ;
    PORT
      LAYER Metal2 ;
      RECT 4588.720 0.000 4589.080 0.500 ;
    END
  END OUT1256
  PIN OUT1257
    DIRECTION OUTPUT ;
    USE SIGNAL ;
    PORT
      LAYER Metal2 ;
      RECT 4592.220 0.000 4592.580 0.500 ;
    END
  END OUT1257
  PIN OUT1258
    DIRECTION OUTPUT ;
    USE SIGNAL ;
    PORT
      LAYER Metal2 ;
      RECT 4595.720 0.000 4596.080 0.500 ;
    END
  END OUT1258
  PIN OUT1259
    DIRECTION OUTPUT ;
    USE SIGNAL ;
    PORT
      LAYER Metal2 ;
      RECT 4599.220 0.000 4599.580 0.500 ;
    END
  END OUT1259
  PIN OUT1260
    DIRECTION OUTPUT ;
    USE SIGNAL ;
    PORT
      LAYER Metal2 ;
      RECT 4602.720 0.000 4603.080 0.500 ;
    END
  END OUT1260
  PIN OUT1261
    DIRECTION OUTPUT ;
    USE SIGNAL ;
    PORT
      LAYER Metal2 ;
      RECT 4606.220 0.000 4606.580 0.500 ;
    END
  END OUT1261
  PIN OUT1262
    DIRECTION OUTPUT ;
    USE SIGNAL ;
    PORT
      LAYER Metal2 ;
      RECT 4609.720 0.000 4610.080 0.500 ;
    END
  END OUT1262
  PIN OUT1263
    DIRECTION OUTPUT ;
    USE SIGNAL ;
    PORT
      LAYER Metal2 ;
      RECT 4613.220 0.000 4613.580 0.500 ;
    END
  END OUT1263
  PIN OUT1264
    DIRECTION OUTPUT ;
    USE SIGNAL ;
    PORT
      LAYER Metal2 ;
      RECT 4616.720 0.000 4617.080 0.500 ;
    END
  END OUT1264
  PIN OUT1265
    DIRECTION OUTPUT ;
    USE SIGNAL ;
    PORT
      LAYER Metal2 ;
      RECT 4620.220 0.000 4620.580 0.500 ;
    END
  END OUT1265
  PIN OUT1266
    DIRECTION OUTPUT ;
    USE SIGNAL ;
    PORT
      LAYER Metal2 ;
      RECT 4623.720 0.000 4624.080 0.500 ;
    END
  END OUT1266
  PIN OUT1267
    DIRECTION OUTPUT ;
    USE SIGNAL ;
    PORT
      LAYER Metal2 ;
      RECT 4627.220 0.000 4627.580 0.500 ;
    END
  END OUT1267
  PIN OUT1268
    DIRECTION OUTPUT ;
    USE SIGNAL ;
    PORT
      LAYER Metal2 ;
      RECT 4630.720 0.000 4631.080 0.500 ;
    END
  END OUT1268
  PIN OUT1269
    DIRECTION OUTPUT ;
    USE SIGNAL ;
    PORT
      LAYER Metal2 ;
      RECT 4634.220 0.000 4634.580 0.500 ;
    END
  END OUT1269
  PIN OUT1270
    DIRECTION OUTPUT ;
    USE SIGNAL ;
    PORT
      LAYER Metal2 ;
      RECT 4637.720 0.000 4638.080 0.500 ;
    END
  END OUT1270
  PIN OUT1271
    DIRECTION OUTPUT ;
    USE SIGNAL ;
    PORT
      LAYER Metal2 ;
      RECT 4641.220 0.000 4641.580 0.500 ;
    END
  END OUT1271
  PIN OUT1272
    DIRECTION OUTPUT ;
    USE SIGNAL ;
    PORT
      LAYER Metal2 ;
      RECT 4644.720 0.000 4645.080 0.500 ;
    END
  END OUT1272
  PIN OUT1273
    DIRECTION OUTPUT ;
    USE SIGNAL ;
    PORT
      LAYER Metal2 ;
      RECT 4648.220 0.000 4648.580 0.500 ;
    END
  END OUT1273
  PIN OUT1274
    DIRECTION OUTPUT ;
    USE SIGNAL ;
    PORT
      LAYER Metal2 ;
      RECT 4651.720 0.000 4652.080 0.500 ;
    END
  END OUT1274
  PIN OUT1275
    DIRECTION OUTPUT ;
    USE SIGNAL ;
    PORT
      LAYER Metal2 ;
      RECT 4655.220 0.000 4655.580 0.500 ;
    END
  END OUT1275
  PIN OUT1276
    DIRECTION OUTPUT ;
    USE SIGNAL ;
    PORT
      LAYER Metal2 ;
      RECT 4658.720 0.000 4659.080 0.500 ;
    END
  END OUT1276
  PIN OUT1277
    DIRECTION OUTPUT ;
    USE SIGNAL ;
    PORT
      LAYER Metal2 ;
      RECT 4662.220 0.000 4662.580 0.500 ;
    END
  END OUT1277
  PIN OUT1278
    DIRECTION OUTPUT ;
    USE SIGNAL ;
    PORT
      LAYER Metal2 ;
      RECT 4665.720 0.000 4666.080 0.500 ;
    END
  END OUT1278
  PIN OUT1279
    DIRECTION OUTPUT ;
    USE SIGNAL ;
    PORT
      LAYER Metal2 ;
      RECT 4669.220 0.000 4669.580 0.500 ;
    END
  END OUT1279
  PIN WL0
    DIRECTION INPUT ;
    USE SIGNAL ;
    PORT
      LAYER Metal3 ;
      RECT 0.000 112.720 0.500 113.080 ;
    END
  END WL0
  PIN WL1
    DIRECTION INPUT ;
    USE SIGNAL ;
    PORT
      LAYER Metal3 ;
      RECT 0.000 114.160 0.500 114.520 ;
    END
  END WL1
  PIN WL2
    DIRECTION INPUT ;
    USE SIGNAL ;
    PORT
      LAYER Metal3 ;
      RECT 0.000 115.600 0.500 115.960 ;
    END
  END WL2
  PIN WL3
    DIRECTION INPUT ;
    USE SIGNAL ;
    PORT
      LAYER Metal3 ;
      RECT 0.000 117.040 0.500 117.400 ;
    END
  END WL3
  PIN WL4
    DIRECTION INPUT ;
    USE SIGNAL ;
    PORT
      LAYER Metal3 ;
      RECT 0.000 118.480 0.500 118.840 ;
    END
  END WL4
  PIN WL5
    DIRECTION INPUT ;
    USE SIGNAL ;
    PORT
      LAYER Metal3 ;
      RECT 0.000 119.920 0.500 120.280 ;
    END
  END WL5
  PIN WL6
    DIRECTION INPUT ;
    USE SIGNAL ;
    PORT
      LAYER Metal3 ;
      RECT 0.000 121.360 0.500 121.720 ;
    END
  END WL6
  PIN WL7
    DIRECTION INPUT ;
    USE SIGNAL ;
    PORT
      LAYER Metal3 ;
      RECT 0.000 122.800 0.500 123.160 ;
    END
  END WL7
  PIN WL8
    DIRECTION INPUT ;
    USE SIGNAL ;
    PORT
      LAYER Metal3 ;
      RECT 0.000 126.040 0.500 126.400 ;
    END
  END WL8
  PIN WL9
    DIRECTION INPUT ;
    USE SIGNAL ;
    PORT
      LAYER Metal3 ;
      RECT 0.000 127.480 0.500 127.840 ;
    END
  END WL9
  PIN WL10
    DIRECTION INPUT ;
    USE SIGNAL ;
    PORT
      LAYER Metal3 ;
      RECT 0.000 128.920 0.500 129.280 ;
    END
  END WL10
  PIN WL11
    DIRECTION INPUT ;
    USE SIGNAL ;
    PORT
      LAYER Metal3 ;
      RECT 0.000 130.360 0.500 130.720 ;
    END
  END WL11
  PIN WL12
    DIRECTION INPUT ;
    USE SIGNAL ;
    PORT
      LAYER Metal3 ;
      RECT 0.000 131.800 0.500 132.160 ;
    END
  END WL12
  PIN WL13
    DIRECTION INPUT ;
    USE SIGNAL ;
    PORT
      LAYER Metal3 ;
      RECT 0.000 133.240 0.500 133.600 ;
    END
  END WL13
  PIN WL14
    DIRECTION INPUT ;
    USE SIGNAL ;
    PORT
      LAYER Metal3 ;
      RECT 0.000 134.680 0.500 135.040 ;
    END
  END WL14
  PIN WL15
    DIRECTION INPUT ;
    USE SIGNAL ;
    PORT
      LAYER Metal3 ;
      RECT 0.000 136.120 0.500 136.480 ;
    END
  END WL15
  PIN WL16
    DIRECTION INPUT ;
    USE SIGNAL ;
    PORT
      LAYER Metal3 ;
      RECT 0.000 139.360 0.500 139.720 ;
    END
  END WL16
  PIN WL17
    DIRECTION INPUT ;
    USE SIGNAL ;
    PORT
      LAYER Metal3 ;
      RECT 0.000 140.800 0.500 141.160 ;
    END
  END WL17
  PIN WL18
    DIRECTION INPUT ;
    USE SIGNAL ;
    PORT
      LAYER Metal3 ;
      RECT 0.000 142.240 0.500 142.600 ;
    END
  END WL18
  PIN WL19
    DIRECTION INPUT ;
    USE SIGNAL ;
    PORT
      LAYER Metal3 ;
      RECT 0.000 143.680 0.500 144.040 ;
    END
  END WL19
  PIN WL20
    DIRECTION INPUT ;
    USE SIGNAL ;
    PORT
      LAYER Metal3 ;
      RECT 0.000 145.120 0.500 145.480 ;
    END
  END WL20
  PIN WL21
    DIRECTION INPUT ;
    USE SIGNAL ;
    PORT
      LAYER Metal3 ;
      RECT 0.000 146.560 0.500 146.920 ;
    END
  END WL21
  PIN WL22
    DIRECTION INPUT ;
    USE SIGNAL ;
    PORT
      LAYER Metal3 ;
      RECT 0.000 148.000 0.500 148.360 ;
    END
  END WL22
  PIN WL23
    DIRECTION INPUT ;
    USE SIGNAL ;
    PORT
      LAYER Metal3 ;
      RECT 0.000 149.440 0.500 149.800 ;
    END
  END WL23
  PIN WL24
    DIRECTION INPUT ;
    USE SIGNAL ;
    PORT
      LAYER Metal3 ;
      RECT 0.000 152.680 0.500 153.040 ;
    END
  END WL24
  PIN WL25
    DIRECTION INPUT ;
    USE SIGNAL ;
    PORT
      LAYER Metal3 ;
      RECT 0.000 154.120 0.500 154.480 ;
    END
  END WL25
  PIN WL26
    DIRECTION INPUT ;
    USE SIGNAL ;
    PORT
      LAYER Metal3 ;
      RECT 0.000 155.560 0.500 155.920 ;
    END
  END WL26
  PIN WL27
    DIRECTION INPUT ;
    USE SIGNAL ;
    PORT
      LAYER Metal3 ;
      RECT 0.000 157.000 0.500 157.360 ;
    END
  END WL27
  PIN WL28
    DIRECTION INPUT ;
    USE SIGNAL ;
    PORT
      LAYER Metal3 ;
      RECT 0.000 158.440 0.500 158.800 ;
    END
  END WL28
  PIN WL29
    DIRECTION INPUT ;
    USE SIGNAL ;
    PORT
      LAYER Metal3 ;
      RECT 0.000 159.880 0.500 160.240 ;
    END
  END WL29
  PIN WL30
    DIRECTION INPUT ;
    USE SIGNAL ;
    PORT
      LAYER Metal3 ;
      RECT 0.000 161.320 0.500 161.680 ;
    END
  END WL30
  PIN WL31
    DIRECTION INPUT ;
    USE SIGNAL ;
    PORT
      LAYER Metal3 ;
      RECT 0.000 162.760 0.500 163.120 ;
    END
  END WL31
  PIN WL32
    DIRECTION INPUT ;
    USE SIGNAL ;
    PORT
      LAYER Metal3 ;
      RECT 0.000 166.000 0.500 166.360 ;
    END
  END WL32
  PIN WL33
    DIRECTION INPUT ;
    USE SIGNAL ;
    PORT
      LAYER Metal3 ;
      RECT 0.000 167.440 0.500 167.800 ;
    END
  END WL33
  PIN WL34
    DIRECTION INPUT ;
    USE SIGNAL ;
    PORT
      LAYER Metal3 ;
      RECT 0.000 168.880 0.500 169.240 ;
    END
  END WL34
  PIN WL35
    DIRECTION INPUT ;
    USE SIGNAL ;
    PORT
      LAYER Metal3 ;
      RECT 0.000 170.320 0.500 170.680 ;
    END
  END WL35
  PIN WL36
    DIRECTION INPUT ;
    USE SIGNAL ;
    PORT
      LAYER Metal3 ;
      RECT 0.000 171.760 0.500 172.120 ;
    END
  END WL36
  PIN WL37
    DIRECTION INPUT ;
    USE SIGNAL ;
    PORT
      LAYER Metal3 ;
      RECT 0.000 173.200 0.500 173.560 ;
    END
  END WL37
  PIN WL38
    DIRECTION INPUT ;
    USE SIGNAL ;
    PORT
      LAYER Metal3 ;
      RECT 0.000 174.640 0.500 175.000 ;
    END
  END WL38
  PIN WL39
    DIRECTION INPUT ;
    USE SIGNAL ;
    PORT
      LAYER Metal3 ;
      RECT 0.000 176.080 0.500 176.440 ;
    END
  END WL39
  PIN WL40
    DIRECTION INPUT ;
    USE SIGNAL ;
    PORT
      LAYER Metal3 ;
      RECT 0.000 179.320 0.500 179.680 ;
    END
  END WL40
  PIN WL41
    DIRECTION INPUT ;
    USE SIGNAL ;
    PORT
      LAYER Metal3 ;
      RECT 0.000 180.760 0.500 181.120 ;
    END
  END WL41
  PIN WL42
    DIRECTION INPUT ;
    USE SIGNAL ;
    PORT
      LAYER Metal3 ;
      RECT 0.000 182.200 0.500 182.560 ;
    END
  END WL42
  PIN WL43
    DIRECTION INPUT ;
    USE SIGNAL ;
    PORT
      LAYER Metal3 ;
      RECT 0.000 183.640 0.500 184.000 ;
    END
  END WL43
  PIN WL44
    DIRECTION INPUT ;
    USE SIGNAL ;
    PORT
      LAYER Metal3 ;
      RECT 0.000 185.080 0.500 185.440 ;
    END
  END WL44
  PIN WL45
    DIRECTION INPUT ;
    USE SIGNAL ;
    PORT
      LAYER Metal3 ;
      RECT 0.000 186.520 0.500 186.880 ;
    END
  END WL45
  PIN WL46
    DIRECTION INPUT ;
    USE SIGNAL ;
    PORT
      LAYER Metal3 ;
      RECT 0.000 187.960 0.500 188.320 ;
    END
  END WL46
  PIN WL47
    DIRECTION INPUT ;
    USE SIGNAL ;
    PORT
      LAYER Metal3 ;
      RECT 0.000 189.400 0.500 189.760 ;
    END
  END WL47
  PIN WL48
    DIRECTION INPUT ;
    USE SIGNAL ;
    PORT
      LAYER Metal3 ;
      RECT 0.000 192.640 0.500 193.000 ;
    END
  END WL48
  PIN WL49
    DIRECTION INPUT ;
    USE SIGNAL ;
    PORT
      LAYER Metal3 ;
      RECT 0.000 194.080 0.500 194.440 ;
    END
  END WL49
  PIN WL50
    DIRECTION INPUT ;
    USE SIGNAL ;
    PORT
      LAYER Metal3 ;
      RECT 0.000 195.520 0.500 195.880 ;
    END
  END WL50
  PIN WL51
    DIRECTION INPUT ;
    USE SIGNAL ;
    PORT
      LAYER Metal3 ;
      RECT 0.000 196.960 0.500 197.320 ;
    END
  END WL51
  PIN WL52
    DIRECTION INPUT ;
    USE SIGNAL ;
    PORT
      LAYER Metal3 ;
      RECT 0.000 198.400 0.500 198.760 ;
    END
  END WL52
  PIN WL53
    DIRECTION INPUT ;
    USE SIGNAL ;
    PORT
      LAYER Metal3 ;
      RECT 0.000 199.840 0.500 200.200 ;
    END
  END WL53
  PIN WL54
    DIRECTION INPUT ;
    USE SIGNAL ;
    PORT
      LAYER Metal3 ;
      RECT 0.000 201.280 0.500 201.640 ;
    END
  END WL54
  PIN WL55
    DIRECTION INPUT ;
    USE SIGNAL ;
    PORT
      LAYER Metal3 ;
      RECT 0.000 202.720 0.500 203.080 ;
    END
  END WL55
  PIN WL56
    DIRECTION INPUT ;
    USE SIGNAL ;
    PORT
      LAYER Metal3 ;
      RECT 0.000 205.960 0.500 206.320 ;
    END
  END WL56
  PIN WL57
    DIRECTION INPUT ;
    USE SIGNAL ;
    PORT
      LAYER Metal3 ;
      RECT 0.000 207.400 0.500 207.760 ;
    END
  END WL57
  PIN WL58
    DIRECTION INPUT ;
    USE SIGNAL ;
    PORT
      LAYER Metal3 ;
      RECT 0.000 208.840 0.500 209.200 ;
    END
  END WL58
  PIN WL59
    DIRECTION INPUT ;
    USE SIGNAL ;
    PORT
      LAYER Metal3 ;
      RECT 0.000 210.280 0.500 210.640 ;
    END
  END WL59
  PIN WL60
    DIRECTION INPUT ;
    USE SIGNAL ;
    PORT
      LAYER Metal3 ;
      RECT 0.000 211.720 0.500 212.080 ;
    END
  END WL60
  PIN WL61
    DIRECTION INPUT ;
    USE SIGNAL ;
    PORT
      LAYER Metal3 ;
      RECT 0.000 213.160 0.500 213.520 ;
    END
  END WL61
  PIN WL62
    DIRECTION INPUT ;
    USE SIGNAL ;
    PORT
      LAYER Metal3 ;
      RECT 0.000 214.600 0.500 214.960 ;
    END
  END WL62
  PIN WL63
    DIRECTION INPUT ;
    USE SIGNAL ;
    PORT
      LAYER Metal3 ;
      RECT 0.000 216.040 0.500 216.400 ;
    END
  END WL63
  PIN PC
    DIRECTION INPUT ;
    USE SIGNAL ;
    PORT
      LAYER Metal3 ;
      RECT 0.000 8.380 0.500 8.740 ;
    END
  END PC
  PIN VSS
    DIRECTION INOUT ;
    USE GROUND ;
    PORT
      LAYER Metal4 ;
      RECT 0.790 217.000 1.210 220.000 ;
      LAYER Metal5 ;
      RECT 0.600 218.600 1.400 219.400 ;
    END
  END VSS
  PIN VDD
    DIRECTION INOUT ;
    USE POWER ;
    PORT
      LAYER Metal4 ;
      RECT 2.790 217.000 3.210 220.000 ;
      LAYER Metal5 ;
      RECT 2.600 218.600 3.400 219.400 ;
    END
  END VDD
  OBS
    LAYER Metal1 ;
    RECT 0 0 4670 220 ;
    LAYER Metal2 ;
    RECT 0 0 4670 220 ;
    LAYER Metal3 ;
    RECT 0 0 4670 220 ;
    LAYER Metal4 ;
    RECT 0 0 4670 220 ;
    LAYER Metal5 ;
    RECT 0 0 4670 220 ;
  END
END RV_K64_READOUT_TILE_00
END LIBRARY
